VERSION 5.7 ;
  NOWIREEXTENSIONATPIN ON ;
  DIVIDERCHAR "/" ;
  BUSBITCHARS "[]" ;
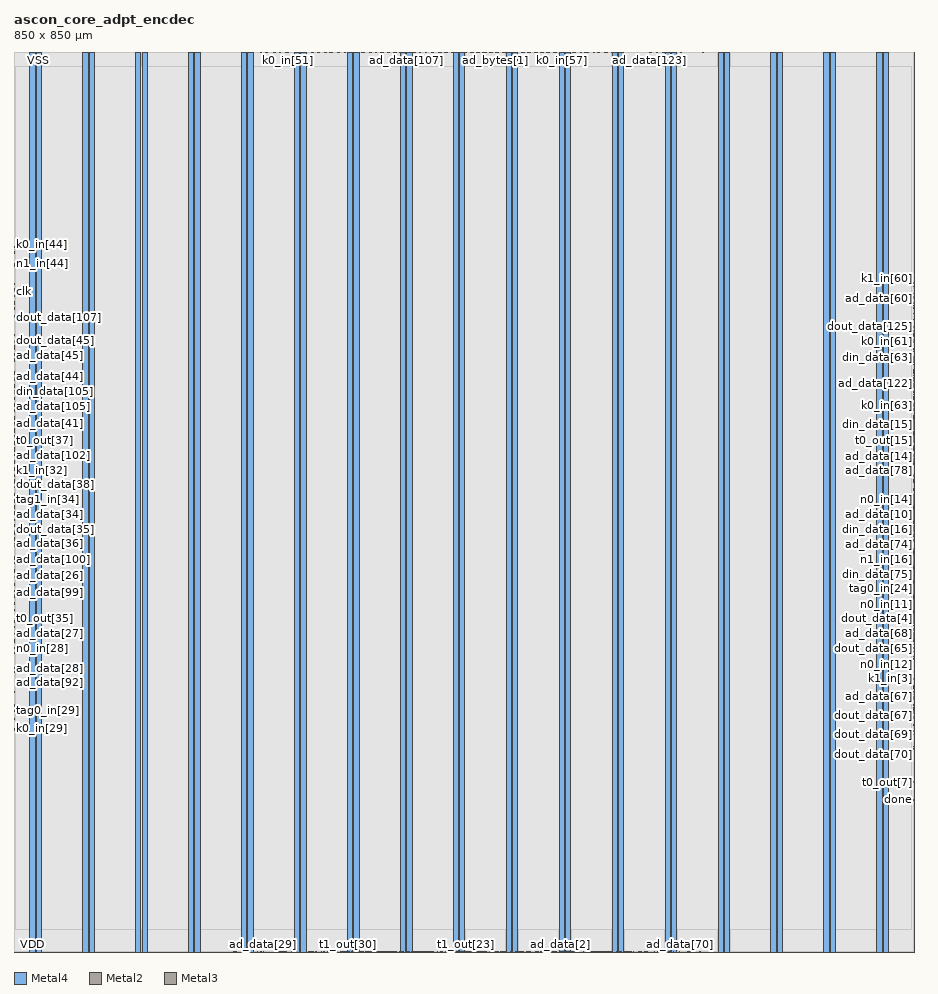
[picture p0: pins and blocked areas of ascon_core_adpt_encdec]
MACRO ascon_core_adpt_encdec
  CLASS BLOCK ;
  FOREIGN ascon_core_adpt_encdec ;
  ORIGIN 0.000 0.000 ;
  SIZE 850.000 BY 850.000 ;
  PIN VDD
    DIRECTION INOUT ;
    USE POWER ;
    PORT
      LAYER Metal4 ;
        RECT 14.940 0.000 19.940 850.000 ;
    END
    PORT
      LAYER Metal4 ;
        RECT 64.940 0.000 69.940 850.000 ;
    END
    PORT
      LAYER Metal4 ;
        RECT 114.940 0.000 119.940 850.000 ;
    END
    PORT
      LAYER Metal4 ;
        RECT 164.940 0.000 169.940 850.000 ;
    END
    PORT
      LAYER Metal4 ;
        RECT 214.940 0.000 219.940 850.000 ;
    END
    PORT
      LAYER Metal4 ;
        RECT 264.940 0.000 269.940 850.000 ;
    END
    PORT
      LAYER Metal4 ;
        RECT 314.940 0.000 319.940 850.000 ;
    END
    PORT
      LAYER Metal4 ;
        RECT 364.940 0.000 369.940 850.000 ;
    END
    PORT
      LAYER Metal4 ;
        RECT 414.940 0.000 419.940 850.000 ;
    END
    PORT
      LAYER Metal4 ;
        RECT 464.940 0.000 469.940 850.000 ;
    END
    PORT
      LAYER Metal4 ;
        RECT 514.940 0.000 519.940 850.000 ;
    END
    PORT
      LAYER Metal4 ;
        RECT 564.940 0.000 569.940 850.000 ;
    END
    PORT
      LAYER Metal4 ;
        RECT 614.940 0.000 619.940 850.000 ;
    END
    PORT
      LAYER Metal4 ;
        RECT 664.940 0.000 669.940 850.000 ;
    END
    PORT
      LAYER Metal4 ;
        RECT 714.940 0.000 719.940 850.000 ;
    END
    PORT
      LAYER Metal4 ;
        RECT 764.940 0.000 769.940 850.000 ;
    END
    PORT
      LAYER Metal4 ;
        RECT 814.940 0.000 819.940 850.000 ;
    END
  END VDD
  PIN VSS
    DIRECTION INOUT ;
    USE GROUND ;
    PORT
      LAYER Metal4 ;
        RECT 20.940 0.000 25.940 850.000 ;
    END
    PORT
      LAYER Metal4 ;
        RECT 70.940 0.000 75.940 850.000 ;
    END
    PORT
      LAYER Metal4 ;
        RECT 120.940 0.000 125.940 850.000 ;
    END
    PORT
      LAYER Metal4 ;
        RECT 170.940 0.000 175.940 850.000 ;
    END
    PORT
      LAYER Metal4 ;
        RECT 220.940 0.000 225.940 850.000 ;
    END
    PORT
      LAYER Metal4 ;
        RECT 270.940 0.000 275.940 850.000 ;
    END
    PORT
      LAYER Metal4 ;
        RECT 320.940 0.000 325.940 850.000 ;
    END
    PORT
      LAYER Metal4 ;
        RECT 370.940 0.000 375.940 850.000 ;
    END
    PORT
      LAYER Metal4 ;
        RECT 420.940 0.000 425.940 850.000 ;
    END
    PORT
      LAYER Metal4 ;
        RECT 470.940 0.000 475.940 850.000 ;
    END
    PORT
      LAYER Metal4 ;
        RECT 520.940 0.000 525.940 850.000 ;
    END
    PORT
      LAYER Metal4 ;
        RECT 570.940 0.000 575.940 850.000 ;
    END
    PORT
      LAYER Metal4 ;
        RECT 620.940 0.000 625.940 850.000 ;
    END
    PORT
      LAYER Metal4 ;
        RECT 670.940 0.000 675.940 850.000 ;
    END
    PORT
      LAYER Metal4 ;
        RECT 720.940 0.000 725.940 850.000 ;
    END
    PORT
      LAYER Metal4 ;
        RECT 770.940 0.000 775.940 850.000 ;
    END
    PORT
      LAYER Metal4 ;
        RECT 820.940 0.000 825.940 850.000 ;
    END
  END VSS
  PIN ad_bytes[0]
    DIRECTION INPUT ;
    USE SIGNAL ;
    ANTENNAGATEAREA 0.741000 ;
    PORT
      LAYER Metal2 ;
        RECT 453.600 849.440 454.160 850.000 ;
    END
  END ad_bytes[0]
  PIN ad_bytes[1]
    DIRECTION INPUT ;
    USE SIGNAL ;
    ANTENNAGATEAREA 1.102000 ;
    PORT
      LAYER Metal2 ;
        RECT 454.720 849.440 455.280 850.000 ;
    END
  END ad_bytes[1]
  PIN ad_bytes[2]
    DIRECTION INPUT ;
    USE SIGNAL ;
    ANTENNAGATEAREA 0.741000 ;
    PORT
      LAYER Metal2 ;
        RECT 448.000 849.440 448.560 850.000 ;
    END
  END ad_bytes[2]
  PIN ad_bytes[3]
    DIRECTION INPUT ;
    USE SIGNAL ;
    ANTENNAGATEAREA 0.741000 ;
    PORT
      LAYER Metal2 ;
        RECT 461.440 849.440 462.000 850.000 ;
    END
  END ad_bytes[3]
  PIN ad_bytes[4]
    DIRECTION INPUT ;
    USE SIGNAL ;
    ANTENNAGATEAREA 1.102000 ;
    PORT
      LAYER Metal2 ;
        RECT 462.560 849.440 463.120 850.000 ;
    END
  END ad_bytes[4]
  PIN ad_data[0]
    DIRECTION INPUT ;
    USE SIGNAL ;
    ANTENNAGATEAREA 0.741000 ;
    PORT
      LAYER Metal3 ;
        RECT 849.440 374.080 850.000 374.640 ;
    END
  END ad_data[0]
  PIN ad_data[100]
    DIRECTION INPUT ;
    USE SIGNAL ;
    ANTENNAGATEAREA 0.741000 ;
    PORT
      LAYER Metal3 ;
        RECT 0.000 370.720 0.560 371.280 ;
    END
  END ad_data[100]
  PIN ad_data[101]
    DIRECTION INPUT ;
    USE SIGNAL ;
    ANTENNAGATEAREA 0.741000 ;
    PORT
      LAYER Metal3 ;
        RECT 0.000 458.080 0.560 458.640 ;
    END
  END ad_data[101]
  PIN ad_data[102]
    DIRECTION INPUT ;
    USE SIGNAL ;
    ANTENNAGATEAREA 0.741000 ;
    PORT
      LAYER Metal3 ;
        RECT 0.000 476.000 0.560 476.560 ;
    END
  END ad_data[102]
  PIN ad_data[103]
    DIRECTION INPUT ;
    USE SIGNAL ;
    ANTENNAGATEAREA 0.741000 ;
    PORT
      LAYER Metal3 ;
        RECT 0.000 449.120 0.560 449.680 ;
    END
  END ad_data[103]
  PIN ad_data[104]
    DIRECTION INPUT ;
    USE SIGNAL ;
    ANTENNAGATEAREA 0.741000 ;
    PORT
      LAYER Metal2 ;
        RECT 430.080 849.440 430.640 850.000 ;
    END
  END ad_data[104]
  PIN ad_data[105]
    DIRECTION INPUT ;
    USE SIGNAL ;
    ANTENNAGATEAREA 0.741000 ;
    PORT
      LAYER Metal3 ;
        RECT 0.000 515.200 0.560 515.760 ;
    END
  END ad_data[105]
  PIN ad_data[106]
    DIRECTION INPUT ;
    USE SIGNAL ;
    ANTENNAGATEAREA 0.741000 ;
    PORT
      LAYER Metal3 ;
        RECT 0.000 511.840 0.560 512.400 ;
    END
  END ad_data[106]
  PIN ad_data[107]
    DIRECTION INPUT ;
    USE SIGNAL ;
    ANTENNAGATEAREA 0.741000 ;
    PORT
      LAYER Metal2 ;
        RECT 370.720 849.440 371.280 850.000 ;
    END
  END ad_data[107]
  PIN ad_data[108]
    DIRECTION INPUT ;
    USE SIGNAL ;
    ANTENNAGATEAREA 0.741000 ;
    PORT
      LAYER Metal3 ;
        RECT 0.000 612.640 0.560 613.200 ;
    END
  END ad_data[108]
  PIN ad_data[109]
    DIRECTION INPUT ;
    USE SIGNAL ;
    ANTENNAGATEAREA 0.741000 ;
    PORT
      LAYER Metal3 ;
        RECT 0.000 608.160 0.560 608.720 ;
    END
  END ad_data[109]
  PIN ad_data[10]
    DIRECTION INPUT ;
    USE SIGNAL ;
    ANTENNAGATEAREA 0.741000 ;
    PORT
      LAYER Metal3 ;
        RECT 849.440 413.280 850.000 413.840 ;
    END
  END ad_data[10]
  PIN ad_data[110]
    DIRECTION INPUT ;
    USE SIGNAL ;
    ANTENNAGATEAREA 0.741000 ;
    PORT
      LAYER Metal2 ;
        RECT 246.400 849.440 246.960 850.000 ;
    END
  END ad_data[110]
  PIN ad_data[111]
    DIRECTION INPUT ;
    USE SIGNAL ;
    ANTENNAGATEAREA 0.741000 ;
    PORT
      LAYER Metal3 ;
        RECT 0.000 558.880 0.560 559.440 ;
    END
  END ad_data[111]
  PIN ad_data[112]
    DIRECTION INPUT ;
    USE SIGNAL ;
    ANTENNAGATEAREA 0.741000 ;
    PORT
      LAYER Metal2 ;
        RECT 418.880 849.440 419.440 850.000 ;
    END
  END ad_data[112]
  PIN ad_data[113]
    DIRECTION INPUT ;
    USE SIGNAL ;
    ANTENNAGATEAREA 0.741000 ;
    PORT
      LAYER Metal2 ;
        RECT 296.800 849.440 297.360 850.000 ;
    END
  END ad_data[113]
  PIN ad_data[114]
    DIRECTION INPUT ;
    USE SIGNAL ;
    ANTENNAGATEAREA 0.741000 ;
    PORT
      LAYER Metal2 ;
        RECT 348.320 849.440 348.880 850.000 ;
    END
  END ad_data[114]
  PIN ad_data[115]
    DIRECTION INPUT ;
    USE SIGNAL ;
    ANTENNAGATEAREA 0.741000 ;
    PORT
      LAYER Metal2 ;
        RECT 287.840 849.440 288.400 850.000 ;
    END
  END ad_data[115]
  PIN ad_data[116]
    DIRECTION INPUT ;
    USE SIGNAL ;
    ANTENNAGATEAREA 0.741000 ;
    PORT
      LAYER Metal2 ;
        RECT 327.040 849.440 327.600 850.000 ;
    END
  END ad_data[116]
  PIN ad_data[117]
    DIRECTION INPUT ;
    USE SIGNAL ;
    ANTENNAGATEAREA 0.741000 ;
    PORT
      LAYER Metal2 ;
        RECT 427.840 849.440 428.400 850.000 ;
    END
  END ad_data[117]
  PIN ad_data[118]
    DIRECTION INPUT ;
    USE SIGNAL ;
    ANTENNAGATEAREA 0.741000 ;
    PORT
      LAYER Metal2 ;
        RECT 465.920 849.440 466.480 850.000 ;
    END
  END ad_data[118]
  PIN ad_data[119]
    DIRECTION INPUT ;
    USE SIGNAL ;
    ANTENNAGATEAREA 0.741000 ;
    PORT
      LAYER Metal2 ;
        RECT 452.480 849.440 453.040 850.000 ;
    END
  END ad_data[119]
  PIN ad_data[11]
    DIRECTION INPUT ;
    USE SIGNAL ;
    ANTENNAGATEAREA 0.741000 ;
    PORT
      LAYER Metal3 ;
        RECT 849.440 409.920 850.000 410.480 ;
    END
  END ad_data[11]
  PIN ad_data[120]
    DIRECTION INPUT ;
    USE SIGNAL ;
    ANTENNAGATEAREA 0.741000 ;
    PORT
      LAYER Metal2 ;
        RECT 474.880 849.440 475.440 850.000 ;
    END
  END ad_data[120]
  PIN ad_data[121]
    DIRECTION INPUT ;
    USE SIGNAL ;
    ANTENNAGATEAREA 0.741000 ;
    PORT
      LAYER Metal2 ;
        RECT 523.040 849.440 523.600 850.000 ;
    END
  END ad_data[121]
  PIN ad_data[122]
    DIRECTION INPUT ;
    USE SIGNAL ;
    ANTENNAGATEAREA 0.741000 ;
    PORT
      LAYER Metal3 ;
        RECT 849.440 536.480 850.000 537.040 ;
    END
  END ad_data[122]
  PIN ad_data[123]
    DIRECTION INPUT ;
    USE SIGNAL ;
    ANTENNAGATEAREA 0.741000 ;
    PORT
      LAYER Metal2 ;
        RECT 600.320 849.440 600.880 850.000 ;
    END
  END ad_data[123]
  PIN ad_data[124]
    DIRECTION INPUT ;
    USE SIGNAL ;
    ANTENNAGATEAREA 0.741000 ;
    PORT
      LAYER Metal2 ;
        RECT 619.360 849.440 619.920 850.000 ;
    END
  END ad_data[124]
  PIN ad_data[125]
    DIRECTION INPUT ;
    USE SIGNAL ;
    ANTENNAGATEAREA 0.741000 ;
    PORT
      LAYER Metal3 ;
        RECT 849.440 577.920 850.000 578.480 ;
    END
  END ad_data[125]
  PIN ad_data[126]
    DIRECTION INPUT ;
    USE SIGNAL ;
    ANTENNAGATEAREA 0.741000 ;
    PORT
      LAYER Metal2 ;
        RECT 560.000 849.440 560.560 850.000 ;
    END
  END ad_data[126]
  PIN ad_data[127]
    DIRECTION INPUT ;
    USE SIGNAL ;
    ANTENNAGATEAREA 0.741000 ;
    PORT
      LAYER Metal3 ;
        RECT 849.440 538.720 850.000 539.280 ;
    END
  END ad_data[127]
  PIN ad_data[12]
    DIRECTION INPUT ;
    USE SIGNAL ;
    ANTENNAGATEAREA 0.741000 ;
    PORT
      LAYER Metal3 ;
        RECT 849.440 412.160 850.000 412.720 ;
    END
  END ad_data[12]
  PIN ad_data[13]
    DIRECTION INPUT ;
    USE SIGNAL ;
    ANTENNAGATEAREA 0.741000 ;
    PORT
      LAYER Metal3 ;
        RECT 849.440 418.880 850.000 419.440 ;
    END
  END ad_data[13]
  PIN ad_data[14]
    DIRECTION INPUT ;
    USE SIGNAL ;
    ANTENNAGATEAREA 0.741000 ;
    PORT
      LAYER Metal3 ;
        RECT 849.440 474.880 850.000 475.440 ;
    END
  END ad_data[14]
  PIN ad_data[15]
    DIRECTION INPUT ;
    USE SIGNAL ;
    ANTENNAGATEAREA 0.741000 ;
    PORT
      LAYER Metal3 ;
        RECT 849.440 481.600 850.000 482.160 ;
    END
  END ad_data[15]
  PIN ad_data[16]
    DIRECTION INPUT ;
    USE SIGNAL ;
    ANTENNAGATEAREA 0.741000 ;
    PORT
      LAYER Metal3 ;
        RECT 849.440 428.960 850.000 429.520 ;
    END
  END ad_data[16]
  PIN ad_data[17]
    DIRECTION INPUT ;
    USE SIGNAL ;
    ANTENNAGATEAREA 0.741000 ;
    PORT
      LAYER Metal2 ;
        RECT 385.280 0.000 385.840 0.560 ;
    END
  END ad_data[17]
  PIN ad_data[18]
    DIRECTION INPUT ;
    USE SIGNAL ;
    ANTENNAGATEAREA 0.741000 ;
    PORT
      LAYER Metal2 ;
        RECT 445.760 0.000 446.320 0.560 ;
    END
  END ad_data[18]
  PIN ad_data[19]
    DIRECTION INPUT ;
    USE SIGNAL ;
    ANTENNAGATEAREA 0.741000 ;
    PORT
      LAYER Metal2 ;
        RECT 389.760 0.000 390.320 0.560 ;
    END
  END ad_data[19]
  PIN ad_data[1]
    DIRECTION INPUT ;
    USE SIGNAL ;
    ANTENNAGATEAREA 0.741000 ;
    PORT
      LAYER Metal2 ;
        RECT 524.160 0.000 524.720 0.560 ;
    END
  END ad_data[1]
  PIN ad_data[20]
    DIRECTION INPUT ;
    USE SIGNAL ;
    ANTENNAGATEAREA 0.741000 ;
    PORT
      LAYER Metal2 ;
        RECT 443.520 0.000 444.080 0.560 ;
    END
  END ad_data[20]
  PIN ad_data[21]
    DIRECTION INPUT ;
    USE SIGNAL ;
    ANTENNAGATEAREA 0.741000 ;
    PORT
      LAYER Metal2 ;
        RECT 422.240 0.000 422.800 0.560 ;
    END
  END ad_data[21]
  PIN ad_data[22]
    DIRECTION INPUT ;
    USE SIGNAL ;
    ANTENNAGATEAREA 0.741000 ;
    PORT
      LAYER Metal2 ;
        RECT 381.920 0.000 382.480 0.560 ;
    END
  END ad_data[22]
  PIN ad_data[23]
    DIRECTION INPUT ;
    USE SIGNAL ;
    ANTENNAGATEAREA 0.741000 ;
    PORT
      LAYER Metal2 ;
        RECT 384.160 0.000 384.720 0.560 ;
    END
  END ad_data[23]
  PIN ad_data[24]
    DIRECTION INPUT ;
    USE SIGNAL ;
    ANTENNAGATEAREA 0.741000 ;
    PORT
      LAYER Metal3 ;
        RECT 0.000 432.320 0.560 432.880 ;
    END
  END ad_data[24]
  PIN ad_data[25]
    DIRECTION INPUT ;
    USE SIGNAL ;
    ANTENNAGATEAREA 0.741000 ;
    PORT
      LAYER Metal2 ;
        RECT 255.360 0.000 255.920 0.560 ;
    END
  END ad_data[25]
  PIN ad_data[26]
    DIRECTION INPUT ;
    USE SIGNAL ;
    ANTENNAGATEAREA 0.741000 ;
    PORT
      LAYER Metal3 ;
        RECT 0.000 362.880 0.560 363.440 ;
    END
  END ad_data[26]
  PIN ad_data[27]
    DIRECTION INPUT ;
    USE SIGNAL ;
    ANTENNAGATEAREA 0.741000 ;
    PORT
      LAYER Metal3 ;
        RECT 0.000 293.440 0.560 294.000 ;
    END
  END ad_data[27]
  PIN ad_data[28]
    DIRECTION INPUT ;
    USE SIGNAL ;
    ANTENNAGATEAREA 0.741000 ;
    PORT
      LAYER Metal3 ;
        RECT 0.000 267.680 0.560 268.240 ;
    END
  END ad_data[28]
  PIN ad_data[29]
    DIRECTION INPUT ;
    USE SIGNAL ;
    ANTENNAGATEAREA 0.741000 ;
    PORT
      LAYER Metal2 ;
        RECT 235.200 0.000 235.760 0.560 ;
    END
  END ad_data[29]
  PIN ad_data[2]
    DIRECTION INPUT ;
    USE SIGNAL ;
    ANTENNAGATEAREA 0.741000 ;
    PORT
      LAYER Metal2 ;
        RECT 516.320 0.000 516.880 0.560 ;
    END
  END ad_data[2]
  PIN ad_data[30]
    DIRECTION INPUT ;
    USE SIGNAL ;
    ANTENNAGATEAREA 0.741000 ;
    PORT
      LAYER Metal2 ;
        RECT 285.600 0.000 286.160 0.560 ;
    END
  END ad_data[30]
  PIN ad_data[31]
    DIRECTION INPUT ;
    USE SIGNAL ;
    ANTENNAGATEAREA 0.741000 ;
    PORT
      LAYER Metal3 ;
        RECT 0.000 359.520 0.560 360.080 ;
    END
  END ad_data[31]
  PIN ad_data[32]
    DIRECTION INPUT ;
    USE SIGNAL ;
    ANTENNAGATEAREA 0.741000 ;
    PORT
      LAYER Metal3 ;
        RECT 0.000 439.040 0.560 439.600 ;
    END
  END ad_data[32]
  PIN ad_data[33]
    DIRECTION INPUT ;
    USE SIGNAL ;
    ANTENNAGATEAREA 0.741000 ;
    PORT
      LAYER Metal3 ;
        RECT 0.000 399.840 0.560 400.400 ;
    END
  END ad_data[33]
  PIN ad_data[34]
    DIRECTION INPUT ;
    USE SIGNAL ;
    ANTENNAGATEAREA 0.741000 ;
    PORT
      LAYER Metal3 ;
        RECT 0.000 413.280 0.560 413.840 ;
    END
  END ad_data[34]
  PIN ad_data[35]
    DIRECTION INPUT ;
    USE SIGNAL ;
    ANTENNAGATEAREA 0.741000 ;
    PORT
      LAYER Metal3 ;
        RECT 0.000 397.600 0.560 398.160 ;
    END
  END ad_data[35]
  PIN ad_data[36]
    DIRECTION INPUT ;
    USE SIGNAL ;
    ANTENNAGATEAREA 0.741000 ;
    PORT
      LAYER Metal3 ;
        RECT 0.000 385.280 0.560 385.840 ;
    END
  END ad_data[36]
  PIN ad_data[37]
    DIRECTION INPUT ;
    USE SIGNAL ;
    ANTENNAGATEAREA 0.741000 ;
    PORT
      LAYER Metal3 ;
        RECT 0.000 421.120 0.560 421.680 ;
    END
  END ad_data[37]
  PIN ad_data[38]
    DIRECTION INPUT ;
    USE SIGNAL ;
    ANTENNAGATEAREA 0.741000 ;
    PORT
      LAYER Metal3 ;
        RECT 0.000 444.640 0.560 445.200 ;
    END
  END ad_data[38]
  PIN ad_data[39]
    DIRECTION INPUT ;
    USE SIGNAL ;
    ANTENNAGATEAREA 0.741000 ;
    PORT
      LAYER Metal3 ;
        RECT 0.000 431.200 0.560 431.760 ;
    END
  END ad_data[39]
  PIN ad_data[3]
    DIRECTION INPUT ;
    USE SIGNAL ;
    ANTENNAGATEAREA 0.741000 ;
    PORT
      LAYER Metal2 ;
        RECT 525.280 0.000 525.840 0.560 ;
    END
  END ad_data[3]
  PIN ad_data[40]
    DIRECTION INPUT ;
    USE SIGNAL ;
    ANTENNAGATEAREA 0.741000 ;
    PORT
      LAYER Metal3 ;
        RECT 0.000 470.400 0.560 470.960 ;
    END
  END ad_data[40]
  PIN ad_data[41]
    DIRECTION INPUT ;
    USE SIGNAL ;
    ANTENNAGATEAREA 0.741000 ;
    PORT
      LAYER Metal3 ;
        RECT 0.000 498.400 0.560 498.960 ;
    END
  END ad_data[41]
  PIN ad_data[42]
    DIRECTION INPUT ;
    USE SIGNAL ;
    ANTENNAGATEAREA 0.741000 ;
    PORT
      LAYER Metal3 ;
        RECT 0.000 510.720 0.560 511.280 ;
    END
  END ad_data[42]
  PIN ad_data[43]
    DIRECTION INPUT ;
    USE SIGNAL ;
    ANTENNAGATEAREA 0.741000 ;
    PORT
      LAYER Metal2 ;
        RECT 360.640 849.440 361.200 850.000 ;
    END
  END ad_data[43]
  PIN ad_data[44]
    DIRECTION INPUT ;
    USE SIGNAL ;
    ANTENNAGATEAREA 0.741000 ;
    PORT
      LAYER Metal3 ;
        RECT 0.000 543.200 0.560 543.760 ;
    END
  END ad_data[44]
  PIN ad_data[45]
    DIRECTION INPUT ;
    USE SIGNAL ;
    ANTENNAGATEAREA 0.741000 ;
    PORT
      LAYER Metal3 ;
        RECT 0.000 563.360 0.560 563.920 ;
    END
  END ad_data[45]
  PIN ad_data[46]
    DIRECTION INPUT ;
    USE SIGNAL ;
    ANTENNAGATEAREA 0.741000 ;
    PORT
      LAYER Metal3 ;
        RECT 0.000 564.480 0.560 565.040 ;
    END
  END ad_data[46]
  PIN ad_data[47]
    DIRECTION INPUT ;
    USE SIGNAL ;
    ANTENNAGATEAREA 0.741000 ;
    PORT
      LAYER Metal3 ;
        RECT 0.000 555.520 0.560 556.080 ;
    END
  END ad_data[47]
  PIN ad_data[48]
    DIRECTION INPUT ;
    USE SIGNAL ;
    ANTENNAGATEAREA 0.741000 ;
    PORT
      LAYER Metal2 ;
        RECT 450.240 849.440 450.800 850.000 ;
    END
  END ad_data[48]
  PIN ad_data[49]
    DIRECTION INPUT ;
    USE SIGNAL ;
    ANTENNAGATEAREA 0.741000 ;
    PORT
      LAYER Metal2 ;
        RECT 394.240 849.440 394.800 850.000 ;
    END
  END ad_data[49]
  PIN ad_data[4]
    DIRECTION INPUT ;
    USE SIGNAL ;
    ANTENNAGATEAREA 0.741000 ;
    PORT
      LAYER Metal3 ;
        RECT 849.440 310.240 850.000 310.800 ;
    END
  END ad_data[4]
  PIN ad_data[50]
    DIRECTION INPUT ;
    USE SIGNAL ;
    ANTENNAGATEAREA 0.741000 ;
    PORT
      LAYER Metal2 ;
        RECT 379.680 849.440 380.240 850.000 ;
    END
  END ad_data[50]
  PIN ad_data[51]
    DIRECTION INPUT ;
    USE SIGNAL ;
    ANTENNAGATEAREA 0.741000 ;
    PORT
      LAYER Metal2 ;
        RECT 378.560 849.440 379.120 850.000 ;
    END
  END ad_data[51]
  PIN ad_data[52]
    DIRECTION INPUT ;
    USE SIGNAL ;
    ANTENNAGATEAREA 0.741000 ;
    PORT
      LAYER Metal2 ;
        RECT 377.440 849.440 378.000 850.000 ;
    END
  END ad_data[52]
  PIN ad_data[53]
    DIRECTION INPUT ;
    USE SIGNAL ;
    ANTENNAGATEAREA 0.741000 ;
    PORT
      LAYER Metal2 ;
        RECT 402.080 849.440 402.640 850.000 ;
    END
  END ad_data[53]
  PIN ad_data[54]
    DIRECTION INPUT ;
    USE SIGNAL ;
    ANTENNAGATEAREA 0.741000 ;
    PORT
      LAYER Metal2 ;
        RECT 467.040 849.440 467.600 850.000 ;
    END
  END ad_data[54]
  PIN ad_data[55]
    DIRECTION INPUT ;
    USE SIGNAL ;
    ANTENNAGATEAREA 0.741000 ;
    PORT
      LAYER Metal2 ;
        RECT 420.000 849.440 420.560 850.000 ;
    END
  END ad_data[55]
  PIN ad_data[56]
    DIRECTION INPUT ;
    USE SIGNAL ;
    ANTENNAGATEAREA 0.741000 ;
    PORT
      LAYER Metal2 ;
        RECT 471.520 849.440 472.080 850.000 ;
    END
  END ad_data[56]
  PIN ad_data[57]
    DIRECTION INPUT ;
    USE SIGNAL ;
    ANTENNAGATEAREA 0.741000 ;
    PORT
      LAYER Metal2 ;
        RECT 521.920 849.440 522.480 850.000 ;
    END
  END ad_data[57]
  PIN ad_data[58]
    DIRECTION INPUT ;
    USE SIGNAL ;
    ANTENNAGATEAREA 0.741000 ;
    PORT
      LAYER Metal2 ;
        RECT 520.800 849.440 521.360 850.000 ;
    END
  END ad_data[58]
  PIN ad_data[59]
    DIRECTION INPUT ;
    USE SIGNAL ;
    ANTENNAGATEAREA 0.741000 ;
    PORT
      LAYER Metal2 ;
        RECT 574.560 849.440 575.120 850.000 ;
    END
  END ad_data[59]
  PIN ad_data[5]
    DIRECTION INPUT ;
    USE SIGNAL ;
    ANTENNAGATEAREA 0.741000 ;
    PORT
      LAYER Metal2 ;
        RECT 527.520 0.000 528.080 0.560 ;
    END
  END ad_data[5]
  PIN ad_data[60]
    DIRECTION INPUT ;
    USE SIGNAL ;
    ANTENNAGATEAREA 0.741000 ;
    PORT
      LAYER Metal3 ;
        RECT 849.440 617.120 850.000 617.680 ;
    END
  END ad_data[60]
  PIN ad_data[61]
    DIRECTION INPUT ;
    USE SIGNAL ;
    ANTENNAGATEAREA 0.741000 ;
    PORT
      LAYER Metal3 ;
        RECT 849.440 582.400 850.000 582.960 ;
    END
  END ad_data[61]
  PIN ad_data[62]
    DIRECTION INPUT ;
    USE SIGNAL ;
    ANTENNAGATEAREA 0.741000 ;
    PORT
      LAYER Metal2 ;
        RECT 526.400 849.440 526.960 850.000 ;
    END
  END ad_data[62]
  PIN ad_data[63]
    DIRECTION INPUT ;
    USE SIGNAL ;
    ANTENNAGATEAREA 0.741000 ;
    PORT
      LAYER Metal3 ;
        RECT 849.440 554.400 850.000 554.960 ;
    END
  END ad_data[63]
  PIN ad_data[64]
    DIRECTION INPUT ;
    USE SIGNAL ;
    ANTENNAGATEAREA 0.741000 ;
    PORT
      LAYER Metal2 ;
        RECT 488.320 849.440 488.880 850.000 ;
    END
  END ad_data[64]
  PIN ad_data[65]
    DIRECTION INPUT ;
    USE SIGNAL ;
    ANTENNAGATEAREA 0.741000 ;
    PORT
      LAYER Metal2 ;
        RECT 571.200 0.000 571.760 0.560 ;
    END
  END ad_data[65]
  PIN ad_data[66]
    DIRECTION INPUT ;
    USE SIGNAL ;
    ANTENNAGATEAREA 0.741000 ;
    PORT
      LAYER Metal2 ;
        RECT 544.320 0.000 544.880 0.560 ;
    END
  END ad_data[66]
  PIN ad_data[67]
    DIRECTION INPUT ;
    USE SIGNAL ;
    ANTENNAGATEAREA 0.741000 ;
    PORT
      LAYER Metal3 ;
        RECT 849.440 240.800 850.000 241.360 ;
    END
  END ad_data[67]
  PIN ad_data[68]
    DIRECTION INPUT ;
    USE SIGNAL ;
    ANTENNAGATEAREA 0.741000 ;
    PORT
      LAYER Metal3 ;
        RECT 849.440 293.440 850.000 294.000 ;
    END
  END ad_data[68]
  PIN ad_data[69]
    DIRECTION INPUT ;
    USE SIGNAL ;
    ANTENNAGATEAREA 0.741000 ;
    PORT
      LAYER Metal2 ;
        RECT 547.680 0.000 548.240 0.560 ;
    END
  END ad_data[69]
  PIN ad_data[6]
    DIRECTION INPUT ;
    USE SIGNAL ;
    ANTENNAGATEAREA 0.741000 ;
    PORT
      LAYER Metal2 ;
        RECT 579.040 0.000 579.600 0.560 ;
    END
  END ad_data[6]
  PIN ad_data[70]
    DIRECTION INPUT ;
    USE SIGNAL ;
    ANTENNAGATEAREA 0.741000 ;
    PORT
      LAYER Metal2 ;
        RECT 628.320 0.000 628.880 0.560 ;
    END
  END ad_data[70]
  PIN ad_data[71]
    DIRECTION INPUT ;
    USE SIGNAL ;
    ANTENNAGATEAREA 0.741000 ;
    PORT
      LAYER Metal2 ;
        RECT 608.160 0.000 608.720 0.560 ;
    END
  END ad_data[71]
  PIN ad_data[72]
    DIRECTION INPUT ;
    USE SIGNAL ;
    ANTENNAGATEAREA 0.741000 ;
    PORT
      LAYER Metal3 ;
        RECT 849.440 423.360 850.000 423.920 ;
    END
  END ad_data[72]
  PIN ad_data[73]
    DIRECTION INPUT ;
    USE SIGNAL ;
    ANTENNAGATEAREA 0.741000 ;
    PORT
      LAYER Metal3 ;
        RECT 849.440 484.960 850.000 485.520 ;
    END
  END ad_data[73]
  PIN ad_data[74]
    DIRECTION INPUT ;
    USE SIGNAL ;
    ANTENNAGATEAREA 0.741000 ;
    PORT
      LAYER Metal3 ;
        RECT 849.440 392.000 850.000 392.560 ;
    END
  END ad_data[74]
  PIN ad_data[75]
    DIRECTION INPUT ;
    USE SIGNAL ;
    ANTENNAGATEAREA 0.741000 ;
    PORT
      LAYER Metal3 ;
        RECT 849.440 367.360 850.000 367.920 ;
    END
  END ad_data[75]
  PIN ad_data[76]
    DIRECTION INPUT ;
    USE SIGNAL ;
    ANTENNAGATEAREA 0.741000 ;
    PORT
      LAYER Metal3 ;
        RECT 849.440 330.400 850.000 330.960 ;
    END
  END ad_data[76]
  PIN ad_data[77]
    DIRECTION INPUT ;
    USE SIGNAL ;
    ANTENNAGATEAREA 0.741000 ;
    PORT
      LAYER Metal3 ;
        RECT 849.440 394.240 850.000 394.800 ;
    END
  END ad_data[77]
  PIN ad_data[78]
    DIRECTION INPUT ;
    USE SIGNAL ;
    ANTENNAGATEAREA 0.741000 ;
    PORT
      LAYER Metal3 ;
        RECT 849.440 461.440 850.000 462.000 ;
    END
  END ad_data[78]
  PIN ad_data[79]
    DIRECTION INPUT ;
    USE SIGNAL ;
    ANTENNAGATEAREA 0.741000 ;
    PORT
      LAYER Metal3 ;
        RECT 849.440 488.320 850.000 488.880 ;
    END
  END ad_data[79]
  PIN ad_data[7]
    DIRECTION INPUT ;
    USE SIGNAL ;
    ANTENNAGATEAREA 0.741000 ;
    PORT
      LAYER Metal2 ;
        RECT 581.280 0.000 581.840 0.560 ;
    END
  END ad_data[7]
  PIN ad_data[80]
    DIRECTION INPUT ;
    USE SIGNAL ;
    ANTENNAGATEAREA 0.741000 ;
    PORT
      LAYER Metal2 ;
        RECT 468.160 849.440 468.720 850.000 ;
    END
  END ad_data[80]
  PIN ad_data[81]
    DIRECTION INPUT ;
    USE SIGNAL ;
    ANTENNAGATEAREA 0.741000 ;
    PORT
      LAYER Metal2 ;
        RECT 420.000 0.000 420.560 0.560 ;
    END
  END ad_data[81]
  PIN ad_data[82]
    DIRECTION INPUT ;
    USE SIGNAL ;
    ANTENNAGATEAREA 0.741000 ;
    PORT
      LAYER Metal2 ;
        RECT 473.760 0.000 474.320 0.560 ;
    END
  END ad_data[82]
  PIN ad_data[83]
    DIRECTION INPUT ;
    USE SIGNAL ;
    ANTENNAGATEAREA 0.741000 ;
    PORT
      LAYER Metal2 ;
        RECT 430.080 0.000 430.640 0.560 ;
    END
  END ad_data[83]
  PIN ad_data[84]
    DIRECTION INPUT ;
    USE SIGNAL ;
    ANTENNAGATEAREA 0.741000 ;
    PORT
      LAYER Metal2 ;
        RECT 469.280 0.000 469.840 0.560 ;
    END
  END ad_data[84]
  PIN ad_data[85]
    DIRECTION INPUT ;
    USE SIGNAL ;
    ANTENNAGATEAREA 0.741000 ;
    PORT
      LAYER Metal2 ;
        RECT 454.720 0.000 455.280 0.560 ;
    END
  END ad_data[85]
  PIN ad_data[86]
    DIRECTION INPUT ;
    USE SIGNAL ;
    ANTENNAGATEAREA 0.741000 ;
    PORT
      LAYER Metal2 ;
        RECT 356.160 0.000 356.720 0.560 ;
    END
  END ad_data[86]
  PIN ad_data[87]
    DIRECTION INPUT ;
    USE SIGNAL ;
    ANTENNAGATEAREA 0.741000 ;
    PORT
      LAYER Metal2 ;
        RECT 359.520 0.000 360.080 0.560 ;
    END
  END ad_data[87]
  PIN ad_data[88]
    DIRECTION INPUT ;
    USE SIGNAL ;
    ANTENNAGATEAREA 0.741000 ;
    PORT
      LAYER Metal2 ;
        RECT 349.440 0.000 350.000 0.560 ;
    END
  END ad_data[88]
  PIN ad_data[89]
    DIRECTION INPUT ;
    USE SIGNAL ;
    ANTENNAGATEAREA 0.741000 ;
    PORT
      LAYER Metal2 ;
        RECT 247.520 0.000 248.080 0.560 ;
    END
  END ad_data[89]
  PIN ad_data[8]
    DIRECTION INPUT ;
    USE SIGNAL ;
    ANTENNAGATEAREA 0.741000 ;
    PORT
      LAYER Metal3 ;
        RECT 849.440 416.640 850.000 417.200 ;
    END
  END ad_data[8]
  PIN ad_data[90]
    DIRECTION INPUT ;
    USE SIGNAL ;
    ANTENNAGATEAREA 0.741000 ;
    PORT
      LAYER Metal3 ;
        RECT 0.000 313.600 0.560 314.160 ;
    END
  END ad_data[90]
  PIN ad_data[91]
    DIRECTION INPUT ;
    USE SIGNAL ;
    ANTENNAGATEAREA 0.741000 ;
    PORT
      LAYER Metal3 ;
        RECT 0.000 272.160 0.560 272.720 ;
    END
  END ad_data[91]
  PIN ad_data[92]
    DIRECTION INPUT ;
    USE SIGNAL ;
    ANTENNAGATEAREA 0.741000 ;
    PORT
      LAYER Metal3 ;
        RECT 0.000 254.240 0.560 254.800 ;
    END
  END ad_data[92]
  PIN ad_data[93]
    DIRECTION INPUT ;
    USE SIGNAL ;
    ANTENNAGATEAREA 0.741000 ;
    PORT
      LAYER Metal2 ;
        RECT 207.200 0.000 207.760 0.560 ;
    END
  END ad_data[93]
  PIN ad_data[94]
    DIRECTION INPUT ;
    USE SIGNAL ;
    ANTENNAGATEAREA 0.741000 ;
    PORT
      LAYER Metal2 ;
        RECT 250.880 0.000 251.440 0.560 ;
    END
  END ad_data[94]
  PIN ad_data[95]
    DIRECTION INPUT ;
    USE SIGNAL ;
    ANTENNAGATEAREA 0.741000 ;
    PORT
      LAYER Metal2 ;
        RECT 324.800 0.000 325.360 0.560 ;
    END
  END ad_data[95]
  PIN ad_data[96]
    DIRECTION INPUT ;
    USE SIGNAL ;
    ANTENNAGATEAREA 0.741000 ;
    PORT
      LAYER Metal2 ;
        RECT 445.760 849.440 446.320 850.000 ;
    END
  END ad_data[96]
  PIN ad_data[97]
    DIRECTION INPUT ;
    USE SIGNAL ;
    ANTENNAGATEAREA 0.741000 ;
    PORT
      LAYER Metal3 ;
        RECT 0.000 409.920 0.560 410.480 ;
    END
  END ad_data[97]
  PIN ad_data[98]
    DIRECTION INPUT ;
    USE SIGNAL ;
    ANTENNAGATEAREA 0.741000 ;
    PORT
      LAYER Metal3 ;
        RECT 0.000 430.080 0.560 430.640 ;
    END
  END ad_data[98]
  PIN ad_data[99]
    DIRECTION INPUT ;
    USE SIGNAL ;
    ANTENNAGATEAREA 0.741000 ;
    PORT
      LAYER Metal3 ;
        RECT 0.000 346.080 0.560 346.640 ;
    END
  END ad_data[99]
  PIN ad_data[9]
    DIRECTION INPUT ;
    USE SIGNAL ;
    ANTENNAGATEAREA 0.741000 ;
    PORT
      LAYER Metal3 ;
        RECT 849.440 460.320 850.000 460.880 ;
    END
  END ad_data[9]
  PIN ad_empty
    DIRECTION INPUT ;
    USE SIGNAL ;
    ANTENNAGATEAREA 0.741000 ;
    PORT
      LAYER Metal3 ;
        RECT 849.440 445.760 850.000 446.320 ;
    END
  END ad_empty
  PIN ad_last
    DIRECTION INPUT ;
    USE SIGNAL ;
    ANTENNAGATEAREA 0.741000 ;
    PORT
      LAYER Metal2 ;
        RECT 528.640 849.440 529.200 850.000 ;
    END
  END ad_last
  PIN ad_ready
    DIRECTION OUTPUT ;
    USE SIGNAL ;
    ANTENNADIFFAREA 1.182800 ;
    PORT
      LAYER Metal2 ;
        RECT 623.840 849.440 624.400 850.000 ;
    END
  END ad_ready
  PIN ad_valid
    DIRECTION INPUT ;
    USE SIGNAL ;
    ANTENNAGATEAREA 0.741000 ;
    PORT
      LAYER Metal3 ;
        RECT 849.440 444.640 850.000 445.200 ;
    END
  END ad_valid
  PIN auth_ok
    DIRECTION OUTPUT ;
    USE SIGNAL ;
    ANTENNADIFFAREA 1.182800 ;
    PORT
      LAYER Metal2 ;
        RECT 441.280 849.440 441.840 850.000 ;
    END
  END auth_ok
  PIN busy
    DIRECTION OUTPUT ;
    USE SIGNAL ;
    ANTENNADIFFAREA 1.182800 ;
    PORT
      LAYER Metal3 ;
        RECT 849.440 476.000 850.000 476.560 ;
    END
  END busy
  PIN clk
    DIRECTION INPUT ;
    USE SIGNAL ;
    ANTENNAGATEAREA 1.183000 ;
    PORT
      LAYER Metal3 ;
        RECT 0.000 623.840 0.560 624.400 ;
    END
  END clk
  PIN dec_mode
    DIRECTION INPUT ;
    USE SIGNAL ;
    ANTENNAGATEAREA 0.741000 ;
    PORT
      LAYER Metal2 ;
        RECT 613.760 849.440 614.320 850.000 ;
    END
  END dec_mode
  PIN din_bytes[0]
    DIRECTION INPUT ;
    USE SIGNAL ;
    ANTENNAGATEAREA 0.741000 ;
    PORT
      LAYER Metal2 ;
        RECT 489.440 849.440 490.000 850.000 ;
    END
  END din_bytes[0]
  PIN din_bytes[1]
    DIRECTION INPUT ;
    USE SIGNAL ;
    ANTENNAGATEAREA 0.741000 ;
    PORT
      LAYER Metal2 ;
        RECT 509.600 849.440 510.160 850.000 ;
    END
  END din_bytes[1]
  PIN din_bytes[2]
    DIRECTION INPUT ;
    USE SIGNAL ;
    ANTENNAGATEAREA 0.741000 ;
    PORT
      LAYER Metal2 ;
        RECT 510.720 849.440 511.280 850.000 ;
    END
  END din_bytes[2]
  PIN din_bytes[3]
    DIRECTION INPUT ;
    USE SIGNAL ;
    ANTENNAGATEAREA 0.741000 ;
    PORT
      LAYER Metal2 ;
        RECT 492.800 849.440 493.360 850.000 ;
    END
  END din_bytes[3]
  PIN din_bytes[4]
    DIRECTION INPUT ;
    USE SIGNAL ;
    ANTENNAGATEAREA 0.741000 ;
    PORT
      LAYER Metal2 ;
        RECT 499.520 849.440 500.080 850.000 ;
    END
  END din_bytes[4]
  PIN din_data[0]
    DIRECTION INPUT ;
    USE SIGNAL ;
    ANTENNAGATEAREA 0.741000 ;
    PORT
      LAYER Metal3 ;
        RECT 849.440 372.960 850.000 373.520 ;
    END
  END din_data[0]
  PIN din_data[100]
    DIRECTION INPUT ;
    USE SIGNAL ;
    ANTENNAGATEAREA 0.741000 ;
    PORT
      LAYER Metal3 ;
        RECT 0.000 375.200 0.560 375.760 ;
    END
  END din_data[100]
  PIN din_data[101]
    DIRECTION INPUT ;
    USE SIGNAL ;
    ANTENNAGATEAREA 0.741000 ;
    PORT
      LAYER Metal3 ;
        RECT 0.000 453.600 0.560 454.160 ;
    END
  END din_data[101]
  PIN din_data[102]
    DIRECTION INPUT ;
    USE SIGNAL ;
    ANTENNAGATEAREA 0.741000 ;
    PORT
      LAYER Metal3 ;
        RECT 0.000 461.440 0.560 462.000 ;
    END
  END din_data[102]
  PIN din_data[103]
    DIRECTION INPUT ;
    USE SIGNAL ;
    ANTENNAGATEAREA 0.741000 ;
    PORT
      LAYER Metal3 ;
        RECT 0.000 450.240 0.560 450.800 ;
    END
  END din_data[103]
  PIN din_data[104]
    DIRECTION INPUT ;
    USE SIGNAL ;
    ANTENNAGATEAREA 0.741000 ;
    PORT
      LAYER Metal3 ;
        RECT 0.000 519.680 0.560 520.240 ;
    END
  END din_data[104]
  PIN din_data[105]
    DIRECTION INPUT ;
    USE SIGNAL ;
    ANTENNAGATEAREA 0.741000 ;
    PORT
      LAYER Metal3 ;
        RECT 0.000 521.920 0.560 522.480 ;
    END
  END din_data[105]
  PIN din_data[106]
    DIRECTION INPUT ;
    USE SIGNAL ;
    ANTENNAGATEAREA 0.741000 ;
    PORT
      LAYER Metal3 ;
        RECT 0.000 518.560 0.560 519.120 ;
    END
  END din_data[106]
  PIN din_data[107]
    DIRECTION INPUT ;
    USE SIGNAL ;
    ANTENNAGATEAREA 0.741000 ;
    PORT
      LAYER Metal2 ;
        RECT 366.240 849.440 366.800 850.000 ;
    END
  END din_data[107]
  PIN din_data[108]
    DIRECTION INPUT ;
    USE SIGNAL ;
    ANTENNAGATEAREA 0.741000 ;
    PORT
      LAYER Metal3 ;
        RECT 0.000 626.080 0.560 626.640 ;
    END
  END din_data[108]
  PIN din_data[109]
    DIRECTION INPUT ;
    USE SIGNAL ;
    ANTENNAGATEAREA 0.741000 ;
    PORT
      LAYER Metal3 ;
        RECT 0.000 614.880 0.560 615.440 ;
    END
  END din_data[109]
  PIN din_data[10]
    DIRECTION INPUT ;
    USE SIGNAL ;
    ANTENNAGATEAREA 0.741000 ;
    PORT
      LAYER Metal3 ;
        RECT 849.440 421.120 850.000 421.680 ;
    END
  END din_data[10]
  PIN din_data[110]
    DIRECTION INPUT ;
    USE SIGNAL ;
    ANTENNAGATEAREA 0.741000 ;
    PORT
      LAYER Metal2 ;
        RECT 247.520 849.440 248.080 850.000 ;
    END
  END din_data[110]
  PIN din_data[111]
    DIRECTION INPUT ;
    USE SIGNAL ;
    ANTENNAGATEAREA 0.741000 ;
    PORT
      LAYER Metal3 ;
        RECT 0.000 562.240 0.560 562.800 ;
    END
  END din_data[111]
  PIN din_data[112]
    DIRECTION INPUT ;
    USE SIGNAL ;
    ANTENNAGATEAREA 0.741000 ;
    PORT
      LAYER Metal2 ;
        RECT 444.640 849.440 445.200 850.000 ;
    END
  END din_data[112]
  PIN din_data[113]
    DIRECTION INPUT ;
    USE SIGNAL ;
    ANTENNAGATEAREA 0.741000 ;
    PORT
      LAYER Metal2 ;
        RECT 300.160 849.440 300.720 850.000 ;
    END
  END din_data[113]
  PIN din_data[114]
    DIRECTION INPUT ;
    USE SIGNAL ;
    ANTENNAGATEAREA 0.741000 ;
    PORT
      LAYER Metal2 ;
        RECT 352.800 849.440 353.360 850.000 ;
    END
  END din_data[114]
  PIN din_data[115]
    DIRECTION INPUT ;
    USE SIGNAL ;
    ANTENNAGATEAREA 0.741000 ;
    PORT
      LAYER Metal2 ;
        RECT 281.120 849.440 281.680 850.000 ;
    END
  END din_data[115]
  PIN din_data[116]
    DIRECTION INPUT ;
    USE SIGNAL ;
    ANTENNAGATEAREA 0.741000 ;
    PORT
      LAYER Metal2 ;
        RECT 328.160 849.440 328.720 850.000 ;
    END
  END din_data[116]
  PIN din_data[117]
    DIRECTION INPUT ;
    USE SIGNAL ;
    ANTENNAGATEAREA 0.741000 ;
    PORT
      LAYER Metal2 ;
        RECT 436.800 849.440 437.360 850.000 ;
    END
  END din_data[117]
  PIN din_data[118]
    DIRECTION INPUT ;
    USE SIGNAL ;
    ANTENNAGATEAREA 0.741000 ;
    PORT
      LAYER Metal2 ;
        RECT 464.800 849.440 465.360 850.000 ;
    END
  END din_data[118]
  PIN din_data[119]
    DIRECTION INPUT ;
    USE SIGNAL ;
    ANTENNAGATEAREA 0.741000 ;
    PORT
      LAYER Metal2 ;
        RECT 456.960 849.440 457.520 850.000 ;
    END
  END din_data[119]
  PIN din_data[11]
    DIRECTION INPUT ;
    USE SIGNAL ;
    ANTENNAGATEAREA 0.741000 ;
    PORT
      LAYER Metal3 ;
        RECT 849.440 404.320 850.000 404.880 ;
    END
  END din_data[11]
  PIN din_data[120]
    DIRECTION INPUT ;
    USE SIGNAL ;
    ANTENNAGATEAREA 0.741000 ;
    PORT
      LAYER Metal2 ;
        RECT 486.080 849.440 486.640 850.000 ;
    END
  END din_data[120]
  PIN din_data[121]
    DIRECTION INPUT ;
    USE SIGNAL ;
    ANTENNAGATEAREA 0.741000 ;
    PORT
      LAYER Metal2 ;
        RECT 524.160 849.440 524.720 850.000 ;
    END
  END din_data[121]
  PIN din_data[122]
    DIRECTION INPUT ;
    USE SIGNAL ;
    ANTENNAGATEAREA 0.741000 ;
    PORT
      LAYER Metal3 ;
        RECT 849.440 535.360 850.000 535.920 ;
    END
  END din_data[122]
  PIN din_data[123]
    DIRECTION INPUT ;
    USE SIGNAL ;
    ANTENNAGATEAREA 0.741000 ;
    PORT
      LAYER Metal2 ;
        RECT 601.440 849.440 602.000 850.000 ;
    END
  END din_data[123]
  PIN din_data[124]
    DIRECTION INPUT ;
    USE SIGNAL ;
    ANTENNAGATEAREA 0.741000 ;
    PORT
      LAYER Metal2 ;
        RECT 622.720 849.440 623.280 850.000 ;
    END
  END din_data[124]
  PIN din_data[125]
    DIRECTION INPUT ;
    USE SIGNAL ;
    ANTENNAGATEAREA 0.741000 ;
    PORT
      LAYER Metal3 ;
        RECT 849.440 583.520 850.000 584.080 ;
    END
  END din_data[125]
  PIN din_data[126]
    DIRECTION INPUT ;
    USE SIGNAL ;
    ANTENNAGATEAREA 0.741000 ;
    PORT
      LAYER Metal2 ;
        RECT 558.880 849.440 559.440 850.000 ;
    END
  END din_data[126]
  PIN din_data[127]
    DIRECTION INPUT ;
    USE SIGNAL ;
    ANTENNAGATEAREA 0.741000 ;
    PORT
      LAYER Metal3 ;
        RECT 849.440 542.080 850.000 542.640 ;
    END
  END din_data[127]
  PIN din_data[12]
    DIRECTION INPUT ;
    USE SIGNAL ;
    ANTENNAGATEAREA 0.741000 ;
    PORT
      LAYER Metal3 ;
        RECT 849.440 405.440 850.000 406.000 ;
    END
  END din_data[12]
  PIN din_data[13]
    DIRECTION INPUT ;
    USE SIGNAL ;
    ANTENNAGATEAREA 0.741000 ;
    PORT
      LAYER Metal3 ;
        RECT 849.440 425.600 850.000 426.160 ;
    END
  END din_data[13]
  PIN din_data[14]
    DIRECTION INPUT ;
    USE SIGNAL ;
    ANTENNAGATEAREA 0.741000 ;
    PORT
      LAYER Metal3 ;
        RECT 849.440 473.760 850.000 474.320 ;
    END
  END din_data[14]
  PIN din_data[15]
    DIRECTION INPUT ;
    USE SIGNAL ;
    ANTENNAGATEAREA 0.741000 ;
    PORT
      LAYER Metal3 ;
        RECT 849.440 490.560 850.000 491.120 ;
    END
  END din_data[15]
  PIN din_data[16]
    DIRECTION INPUT ;
    USE SIGNAL ;
    ANTENNAGATEAREA 0.741000 ;
    PORT
      LAYER Metal3 ;
        RECT 849.440 398.720 850.000 399.280 ;
    END
  END din_data[16]
  PIN din_data[17]
    DIRECTION INPUT ;
    USE SIGNAL ;
    ANTENNAGATEAREA 0.741000 ;
    PORT
      LAYER Metal2 ;
        RECT 388.640 0.000 389.200 0.560 ;
    END
  END din_data[17]
  PIN din_data[18]
    DIRECTION INPUT ;
    USE SIGNAL ;
    ANTENNAGATEAREA 0.741000 ;
    PORT
      LAYER Metal2 ;
        RECT 449.120 0.000 449.680 0.560 ;
    END
  END din_data[18]
  PIN din_data[19]
    DIRECTION INPUT ;
    USE SIGNAL ;
    ANTENNAGATEAREA 0.741000 ;
    PORT
      LAYER Metal2 ;
        RECT 393.120 0.000 393.680 0.560 ;
    END
  END din_data[19]
  PIN din_data[1]
    DIRECTION INPUT ;
    USE SIGNAL ;
    ANTENNAGATEAREA 0.741000 ;
    PORT
      LAYER Metal2 ;
        RECT 521.920 0.000 522.480 0.560 ;
    END
  END din_data[1]
  PIN din_data[20]
    DIRECTION INPUT ;
    USE SIGNAL ;
    ANTENNAGATEAREA 0.741000 ;
    PORT
      LAYER Metal2 ;
        RECT 453.600 0.000 454.160 0.560 ;
    END
  END din_data[20]
  PIN din_data[21]
    DIRECTION INPUT ;
    USE SIGNAL ;
    ANTENNAGATEAREA 0.741000 ;
    PORT
      LAYER Metal2 ;
        RECT 427.840 0.000 428.400 0.560 ;
    END
  END din_data[21]
  PIN din_data[22]
    DIRECTION INPUT ;
    USE SIGNAL ;
    ANTENNAGATEAREA 0.741000 ;
    PORT
      LAYER Metal2 ;
        RECT 375.200 0.000 375.760 0.560 ;
    END
  END din_data[22]
  PIN din_data[23]
    DIRECTION INPUT ;
    USE SIGNAL ;
    ANTENNAGATEAREA 0.741000 ;
    PORT
      LAYER Metal2 ;
        RECT 379.680 0.000 380.240 0.560 ;
    END
  END din_data[23]
  PIN din_data[24]
    DIRECTION INPUT ;
    USE SIGNAL ;
    ANTENNAGATEAREA 0.741000 ;
    PORT
      LAYER Metal2 ;
        RECT 378.560 0.000 379.120 0.560 ;
    END
  END din_data[24]
  PIN din_data[25]
    DIRECTION INPUT ;
    USE SIGNAL ;
    ANTENNAGATEAREA 0.741000 ;
    PORT
      LAYER Metal2 ;
        RECT 254.240 0.000 254.800 0.560 ;
    END
  END din_data[25]
  PIN din_data[26]
    DIRECTION INPUT ;
    USE SIGNAL ;
    ANTENNAGATEAREA 0.741000 ;
    PORT
      LAYER Metal3 ;
        RECT 0.000 356.160 0.560 356.720 ;
    END
  END din_data[26]
  PIN din_data[27]
    DIRECTION INPUT ;
    USE SIGNAL ;
    ANTENNAGATEAREA 0.741000 ;
    PORT
      LAYER Metal3 ;
        RECT 0.000 292.320 0.560 292.880 ;
    END
  END din_data[27]
  PIN din_data[28]
    DIRECTION INPUT ;
    USE SIGNAL ;
    ANTENNAGATEAREA 0.741000 ;
    PORT
      LAYER Metal3 ;
        RECT 0.000 266.560 0.560 267.120 ;
    END
  END din_data[28]
  PIN din_data[29]
    DIRECTION INPUT ;
    USE SIGNAL ;
    ANTENNAGATEAREA 0.741000 ;
    PORT
      LAYER Metal2 ;
        RECT 229.600 0.000 230.160 0.560 ;
    END
  END din_data[29]
  PIN din_data[2]
    DIRECTION INPUT ;
    USE SIGNAL ;
    ANTENNAGATEAREA 0.741000 ;
    PORT
      LAYER Metal2 ;
        RECT 518.560 0.000 519.120 0.560 ;
    END
  END din_data[2]
  PIN din_data[30]
    DIRECTION INPUT ;
    USE SIGNAL ;
    ANTENNAGATEAREA 0.741000 ;
    PORT
      LAYER Metal2 ;
        RECT 281.120 0.000 281.680 0.560 ;
    END
  END din_data[30]
  PIN din_data[31]
    DIRECTION INPUT ;
    USE SIGNAL ;
    ANTENNAGATEAREA 0.741000 ;
    PORT
      LAYER Metal3 ;
        RECT 0.000 358.400 0.560 358.960 ;
    END
  END din_data[31]
  PIN din_data[32]
    DIRECTION INPUT ;
    USE SIGNAL ;
    ANTENNAGATEAREA 0.741000 ;
    PORT
      LAYER Metal3 ;
        RECT 0.000 443.520 0.560 444.080 ;
    END
  END din_data[32]
  PIN din_data[33]
    DIRECTION INPUT ;
    USE SIGNAL ;
    ANTENNAGATEAREA 0.741000 ;
    PORT
      LAYER Metal3 ;
        RECT 0.000 403.200 0.560 403.760 ;
    END
  END din_data[33]
  PIN din_data[34]
    DIRECTION INPUT ;
    USE SIGNAL ;
    ANTENNAGATEAREA 0.741000 ;
    PORT
      LAYER Metal3 ;
        RECT 0.000 418.880 0.560 419.440 ;
    END
  END din_data[34]
  PIN din_data[35]
    DIRECTION INPUT ;
    USE SIGNAL ;
    ANTENNAGATEAREA 0.741000 ;
    PORT
      LAYER Metal3 ;
        RECT 0.000 394.240 0.560 394.800 ;
    END
  END din_data[35]
  PIN din_data[36]
    DIRECTION INPUT ;
    USE SIGNAL ;
    ANTENNAGATEAREA 0.741000 ;
    PORT
      LAYER Metal3 ;
        RECT 0.000 390.880 0.560 391.440 ;
    END
  END din_data[36]
  PIN din_data[37]
    DIRECTION INPUT ;
    USE SIGNAL ;
    ANTENNAGATEAREA 0.741000 ;
    PORT
      LAYER Metal3 ;
        RECT 0.000 428.960 0.560 429.520 ;
    END
  END din_data[37]
  PIN din_data[38]
    DIRECTION INPUT ;
    USE SIGNAL ;
    ANTENNAGATEAREA 0.741000 ;
    PORT
      LAYER Metal3 ;
        RECT 0.000 445.760 0.560 446.320 ;
    END
  END din_data[38]
  PIN din_data[39]
    DIRECTION INPUT ;
    USE SIGNAL ;
    ANTENNAGATEAREA 0.741000 ;
    PORT
      LAYER Metal3 ;
        RECT 0.000 422.240 0.560 422.800 ;
    END
  END din_data[39]
  PIN din_data[3]
    DIRECTION INPUT ;
    USE SIGNAL ;
    ANTENNAGATEAREA 0.741000 ;
    PORT
      LAYER Metal2 ;
        RECT 526.400 0.000 526.960 0.560 ;
    END
  END din_data[3]
  PIN din_data[40]
    DIRECTION INPUT ;
    USE SIGNAL ;
    ANTENNAGATEAREA 0.741000 ;
    PORT
      LAYER Metal3 ;
        RECT 0.000 481.600 0.560 482.160 ;
    END
  END din_data[40]
  PIN din_data[41]
    DIRECTION INPUT ;
    USE SIGNAL ;
    ANTENNAGATEAREA 0.741000 ;
    PORT
      LAYER Metal3 ;
        RECT 0.000 504.000 0.560 504.560 ;
    END
  END din_data[41]
  PIN din_data[42]
    DIRECTION INPUT ;
    USE SIGNAL ;
    ANTENNAGATEAREA 0.741000 ;
    PORT
      LAYER Metal3 ;
        RECT 0.000 505.120 0.560 505.680 ;
    END
  END din_data[42]
  PIN din_data[43]
    DIRECTION INPUT ;
    USE SIGNAL ;
    ANTENNAGATEAREA 0.741000 ;
    PORT
      LAYER Metal2 ;
        RECT 364.000 849.440 364.560 850.000 ;
    END
  END din_data[43]
  PIN din_data[44]
    DIRECTION INPUT ;
    USE SIGNAL ;
    ANTENNAGATEAREA 0.741000 ;
    PORT
      LAYER Metal3 ;
        RECT 0.000 549.920 0.560 550.480 ;
    END
  END din_data[44]
  PIN din_data[45]
    DIRECTION INPUT ;
    USE SIGNAL ;
    ANTENNAGATEAREA 0.741000 ;
    PORT
      LAYER Metal3 ;
        RECT 0.000 568.960 0.560 569.520 ;
    END
  END din_data[45]
  PIN din_data[46]
    DIRECTION INPUT ;
    USE SIGNAL ;
    ANTENNAGATEAREA 0.741000 ;
    PORT
      LAYER Metal2 ;
        RECT 265.440 849.440 266.000 850.000 ;
    END
  END din_data[46]
  PIN din_data[47]
    DIRECTION INPUT ;
    USE SIGNAL ;
    ANTENNAGATEAREA 0.741000 ;
    PORT
      LAYER Metal3 ;
        RECT 0.000 556.640 0.560 557.200 ;
    END
  END din_data[47]
  PIN din_data[48]
    DIRECTION INPUT ;
    USE SIGNAL ;
    ANTENNAGATEAREA 0.741000 ;
    PORT
      LAYER Metal2 ;
        RECT 458.080 849.440 458.640 850.000 ;
    END
  END din_data[48]
  PIN din_data[49]
    DIRECTION INPUT ;
    USE SIGNAL ;
    ANTENNAGATEAREA 0.741000 ;
    PORT
      LAYER Metal2 ;
        RECT 395.360 849.440 395.920 850.000 ;
    END
  END din_data[49]
  PIN din_data[4]
    DIRECTION INPUT ;
    USE SIGNAL ;
    ANTENNAGATEAREA 0.741000 ;
    PORT
      LAYER Metal3 ;
        RECT 849.440 319.200 850.000 319.760 ;
    END
  END din_data[4]
  PIN din_data[50]
    DIRECTION INPUT ;
    USE SIGNAL ;
    ANTENNAGATEAREA 0.741000 ;
    PORT
      LAYER Metal2 ;
        RECT 372.960 849.440 373.520 850.000 ;
    END
  END din_data[50]
  PIN din_data[51]
    DIRECTION INPUT ;
    USE SIGNAL ;
    ANTENNAGATEAREA 0.741000 ;
    PORT
      LAYER Metal2 ;
        RECT 371.840 849.440 372.400 850.000 ;
    END
  END din_data[51]
  PIN din_data[52]
    DIRECTION INPUT ;
    USE SIGNAL ;
    ANTENNAGATEAREA 0.741000 ;
    PORT
      LAYER Metal2 ;
        RECT 375.200 849.440 375.760 850.000 ;
    END
  END din_data[52]
  PIN din_data[53]
    DIRECTION INPUT ;
    USE SIGNAL ;
    ANTENNAGATEAREA 0.741000 ;
    PORT
      LAYER Metal2 ;
        RECT 414.400 849.440 414.960 850.000 ;
    END
  END din_data[53]
  PIN din_data[54]
    DIRECTION INPUT ;
    USE SIGNAL ;
    ANTENNAGATEAREA 0.741000 ;
    PORT
      LAYER Metal2 ;
        RECT 472.640 849.440 473.200 850.000 ;
    END
  END din_data[54]
  PIN din_data[55]
    DIRECTION INPUT ;
    USE SIGNAL ;
    ANTENNAGATEAREA 0.741000 ;
    PORT
      LAYER Metal2 ;
        RECT 424.480 849.440 425.040 850.000 ;
    END
  END din_data[55]
  PIN din_data[56]
    DIRECTION INPUT ;
    USE SIGNAL ;
    ANTENNAGATEAREA 0.741000 ;
    PORT
      LAYER Metal2 ;
        RECT 483.840 849.440 484.400 850.000 ;
    END
  END din_data[56]
  PIN din_data[57]
    DIRECTION INPUT ;
    USE SIGNAL ;
    ANTENNAGATEAREA 0.741000 ;
    PORT
      LAYER Metal2 ;
        RECT 525.280 849.440 525.840 850.000 ;
    END
  END din_data[57]
  PIN din_data[58]
    DIRECTION INPUT ;
    USE SIGNAL ;
    ANTENNAGATEAREA 0.741000 ;
    PORT
      LAYER Metal2 ;
        RECT 527.520 849.440 528.080 850.000 ;
    END
  END din_data[58]
  PIN din_data[59]
    DIRECTION INPUT ;
    USE SIGNAL ;
    ANTENNAGATEAREA 0.741000 ;
    PORT
      LAYER Metal2 ;
        RECT 579.040 849.440 579.600 850.000 ;
    END
  END din_data[59]
  PIN din_data[5]
    DIRECTION INPUT ;
    USE SIGNAL ;
    ANTENNAGATEAREA 0.741000 ;
    PORT
      LAYER Metal2 ;
        RECT 519.680 0.000 520.240 0.560 ;
    END
  END din_data[5]
  PIN din_data[60]
    DIRECTION INPUT ;
    USE SIGNAL ;
    ANTENNAGATEAREA 0.741000 ;
    PORT
      LAYER Metal3 ;
        RECT 849.440 618.240 850.000 618.800 ;
    END
  END din_data[60]
  PIN din_data[61]
    DIRECTION INPUT ;
    USE SIGNAL ;
    ANTENNAGATEAREA 0.741000 ;
    PORT
      LAYER Metal3 ;
        RECT 849.440 586.880 850.000 587.440 ;
    END
  END din_data[61]
  PIN din_data[62]
    DIRECTION INPUT ;
    USE SIGNAL ;
    ANTENNAGATEAREA 0.741000 ;
    PORT
      LAYER Metal2 ;
        RECT 530.880 849.440 531.440 850.000 ;
    END
  END din_data[62]
  PIN din_data[63]
    DIRECTION INPUT ;
    USE SIGNAL ;
    ANTENNAGATEAREA 0.741000 ;
    PORT
      LAYER Metal3 ;
        RECT 849.440 561.120 850.000 561.680 ;
    END
  END din_data[63]
  PIN din_data[64]
    DIRECTION INPUT ;
    USE SIGNAL ;
    ANTENNAGATEAREA 0.741000 ;
    PORT
      LAYER Metal3 ;
        RECT 849.440 361.760 850.000 362.320 ;
    END
  END din_data[64]
  PIN din_data[65]
    DIRECTION INPUT ;
    USE SIGNAL ;
    ANTENNAGATEAREA 0.741000 ;
    PORT
      LAYER Metal2 ;
        RECT 576.800 0.000 577.360 0.560 ;
    END
  END din_data[65]
  PIN din_data[66]
    DIRECTION INPUT ;
    USE SIGNAL ;
    ANTENNAGATEAREA 0.741000 ;
    PORT
      LAYER Metal2 ;
        RECT 548.800 0.000 549.360 0.560 ;
    END
  END din_data[66]
  PIN din_data[67]
    DIRECTION INPUT ;
    USE SIGNAL ;
    ANTENNAGATEAREA 0.741000 ;
    PORT
      LAYER Metal3 ;
        RECT 849.440 238.560 850.000 239.120 ;
    END
  END din_data[67]
  PIN din_data[68]
    DIRECTION INPUT ;
    USE SIGNAL ;
    ANTENNAGATEAREA 0.741000 ;
    PORT
      LAYER Metal3 ;
        RECT 849.440 296.800 850.000 297.360 ;
    END
  END din_data[68]
  PIN din_data[69]
    DIRECTION INPUT ;
    USE SIGNAL ;
    ANTENNAGATEAREA 0.741000 ;
    PORT
      LAYER Metal2 ;
        RECT 554.400 0.000 554.960 0.560 ;
    END
  END din_data[69]
  PIN din_data[6]
    DIRECTION INPUT ;
    USE SIGNAL ;
    ANTENNAGATEAREA 0.741000 ;
    PORT
      LAYER Metal2 ;
        RECT 577.920 0.000 578.480 0.560 ;
    END
  END din_data[6]
  PIN din_data[70]
    DIRECTION INPUT ;
    USE SIGNAL ;
    ANTENNAGATEAREA 0.741000 ;
    PORT
      LAYER Metal2 ;
        RECT 637.280 0.000 637.840 0.560 ;
    END
  END din_data[70]
  PIN din_data[71]
    DIRECTION INPUT ;
    USE SIGNAL ;
    ANTENNAGATEAREA 0.741000 ;
    PORT
      LAYER Metal2 ;
        RECT 611.520 0.000 612.080 0.560 ;
    END
  END din_data[71]
  PIN din_data[72]
    DIRECTION INPUT ;
    USE SIGNAL ;
    ANTENNAGATEAREA 0.741000 ;
    PORT
      LAYER Metal3 ;
        RECT 849.440 414.400 850.000 414.960 ;
    END
  END din_data[72]
  PIN din_data[73]
    DIRECTION INPUT ;
    USE SIGNAL ;
    ANTENNAGATEAREA 0.741000 ;
    PORT
      LAYER Metal3 ;
        RECT 849.440 486.080 850.000 486.640 ;
    END
  END din_data[73]
  PIN din_data[74]
    DIRECTION INPUT ;
    USE SIGNAL ;
    ANTENNAGATEAREA 0.741000 ;
    PORT
      LAYER Metal3 ;
        RECT 849.440 397.600 850.000 398.160 ;
    END
  END din_data[74]
  PIN din_data[75]
    DIRECTION INPUT ;
    USE SIGNAL ;
    ANTENNAGATEAREA 0.741000 ;
    PORT
      LAYER Metal3 ;
        RECT 849.440 349.440 850.000 350.000 ;
    END
  END din_data[75]
  PIN din_data[76]
    DIRECTION INPUT ;
    USE SIGNAL ;
    ANTENNAGATEAREA 0.741000 ;
    PORT
      LAYER Metal3 ;
        RECT 849.440 323.680 850.000 324.240 ;
    END
  END din_data[76]
  PIN din_data[77]
    DIRECTION INPUT ;
    USE SIGNAL ;
    ANTENNAGATEAREA 0.741000 ;
    PORT
      LAYER Metal3 ;
        RECT 849.440 393.120 850.000 393.680 ;
    END
  END din_data[77]
  PIN din_data[78]
    DIRECTION INPUT ;
    USE SIGNAL ;
    ANTENNAGATEAREA 0.741000 ;
    PORT
      LAYER Metal3 ;
        RECT 849.440 465.920 850.000 466.480 ;
    END
  END din_data[78]
  PIN din_data[79]
    DIRECTION INPUT ;
    USE SIGNAL ;
    ANTENNAGATEAREA 0.741000 ;
    PORT
      LAYER Metal3 ;
        RECT 849.440 498.400 850.000 498.960 ;
    END
  END din_data[79]
  PIN din_data[7]
    DIRECTION INPUT ;
    USE SIGNAL ;
    ANTENNAGATEAREA 0.741000 ;
    PORT
      LAYER Metal2 ;
        RECT 580.160 0.000 580.720 0.560 ;
    END
  END din_data[7]
  PIN din_data[80]
    DIRECTION INPUT ;
    USE SIGNAL ;
    ANTENNAGATEAREA 0.741000 ;
    PORT
      LAYER Metal3 ;
        RECT 849.440 400.960 850.000 401.520 ;
    END
  END din_data[80]
  PIN din_data[81]
    DIRECTION INPUT ;
    USE SIGNAL ;
    ANTENNAGATEAREA 0.741000 ;
    PORT
      LAYER Metal2 ;
        RECT 425.600 0.000 426.160 0.560 ;
    END
  END din_data[81]
  PIN din_data[82]
    DIRECTION INPUT ;
    USE SIGNAL ;
    ANTENNAGATEAREA 0.741000 ;
    PORT
      LAYER Metal2 ;
        RECT 486.080 0.000 486.640 0.560 ;
    END
  END din_data[82]
  PIN din_data[83]
    DIRECTION INPUT ;
    USE SIGNAL ;
    ANTENNAGATEAREA 0.741000 ;
    PORT
      LAYER Metal2 ;
        RECT 432.320 0.000 432.880 0.560 ;
    END
  END din_data[83]
  PIN din_data[84]
    DIRECTION INPUT ;
    USE SIGNAL ;
    ANTENNAGATEAREA 0.741000 ;
    PORT
      LAYER Metal2 ;
        RECT 474.880 0.000 475.440 0.560 ;
    END
  END din_data[84]
  PIN din_data[85]
    DIRECTION INPUT ;
    USE SIGNAL ;
    ANTENNAGATEAREA 0.741000 ;
    PORT
      LAYER Metal2 ;
        RECT 459.200 0.000 459.760 0.560 ;
    END
  END din_data[85]
  PIN din_data[86]
    DIRECTION INPUT ;
    USE SIGNAL ;
    ANTENNAGATEAREA 0.741000 ;
    PORT
      LAYER Metal2 ;
        RECT 360.640 0.000 361.200 0.560 ;
    END
  END din_data[86]
  PIN din_data[87]
    DIRECTION INPUT ;
    USE SIGNAL ;
    ANTENNAGATEAREA 0.741000 ;
    PORT
      LAYER Metal2 ;
        RECT 364.000 0.000 364.560 0.560 ;
    END
  END din_data[87]
  PIN din_data[88]
    DIRECTION INPUT ;
    USE SIGNAL ;
    ANTENNAGATEAREA 0.741000 ;
    PORT
      LAYER Metal2 ;
        RECT 343.840 0.000 344.400 0.560 ;
    END
  END din_data[88]
  PIN din_data[89]
    DIRECTION INPUT ;
    USE SIGNAL ;
    ANTENNAGATEAREA 0.741000 ;
    PORT
      LAYER Metal2 ;
        RECT 249.760 0.000 250.320 0.560 ;
    END
  END din_data[89]
  PIN din_data[8]
    DIRECTION INPUT ;
    USE SIGNAL ;
    ANTENNAGATEAREA 0.741000 ;
    PORT
      LAYER Metal3 ;
        RECT 849.440 411.040 850.000 411.600 ;
    END
  END din_data[8]
  PIN din_data[90]
    DIRECTION INPUT ;
    USE SIGNAL ;
    ANTENNAGATEAREA 0.741000 ;
    PORT
      LAYER Metal3 ;
        RECT 0.000 312.480 0.560 313.040 ;
    END
  END din_data[90]
  PIN din_data[91]
    DIRECTION INPUT ;
    USE SIGNAL ;
    ANTENNAGATEAREA 0.741000 ;
    PORT
      LAYER Metal2 ;
        RECT 295.680 0.000 296.240 0.560 ;
    END
  END din_data[91]
  PIN din_data[92]
    DIRECTION INPUT ;
    USE SIGNAL ;
    ANTENNAGATEAREA 0.741000 ;
    PORT
      LAYER Metal3 ;
        RECT 0.000 253.120 0.560 253.680 ;
    END
  END din_data[92]
  PIN din_data[93]
    DIRECTION INPUT ;
    USE SIGNAL ;
    ANTENNAGATEAREA 0.741000 ;
    PORT
      LAYER Metal2 ;
        RECT 208.320 0.000 208.880 0.560 ;
    END
  END din_data[93]
  PIN din_data[94]
    DIRECTION INPUT ;
    USE SIGNAL ;
    ANTENNAGATEAREA 0.741000 ;
    PORT
      LAYER Metal2 ;
        RECT 252.000 0.000 252.560 0.560 ;
    END
  END din_data[94]
  PIN din_data[95]
    DIRECTION INPUT ;
    USE SIGNAL ;
    ANTENNAGATEAREA 0.741000 ;
    PORT
      LAYER Metal2 ;
        RECT 323.680 0.000 324.240 0.560 ;
    END
  END din_data[95]
  PIN din_data[96]
    DIRECTION INPUT ;
    USE SIGNAL ;
    ANTENNAGATEAREA 0.741000 ;
    PORT
      LAYER Metal2 ;
        RECT 371.840 0.000 372.400 0.560 ;
    END
  END din_data[96]
  PIN din_data[97]
    DIRECTION INPUT ;
    USE SIGNAL ;
    ANTENNAGATEAREA 0.741000 ;
    PORT
      LAYER Metal3 ;
        RECT 0.000 414.400 0.560 414.960 ;
    END
  END din_data[97]
  PIN din_data[98]
    DIRECTION INPUT ;
    USE SIGNAL ;
    ANTENNAGATEAREA 0.741000 ;
    PORT
      LAYER Metal3 ;
        RECT 0.000 427.840 0.560 428.400 ;
    END
  END din_data[98]
  PIN din_data[99]
    DIRECTION INPUT ;
    USE SIGNAL ;
    ANTENNAGATEAREA 0.741000 ;
    PORT
      LAYER Metal3 ;
        RECT 0.000 344.960 0.560 345.520 ;
    END
  END din_data[99]
  PIN din_data[9]
    DIRECTION INPUT ;
    USE SIGNAL ;
    ANTENNAGATEAREA 0.741000 ;
    PORT
      LAYER Metal3 ;
        RECT 849.440 464.800 850.000 465.360 ;
    END
  END din_data[9]
  PIN din_last
    DIRECTION INPUT ;
    USE SIGNAL ;
    ANTENNAGATEAREA 0.741000 ;
    PORT
      LAYER Metal3 ;
        RECT 849.440 430.080 850.000 430.640 ;
    END
  END din_last
  PIN din_ready
    DIRECTION OUTPUT ;
    USE SIGNAL ;
    ANTENNADIFFAREA 1.182800 ;
    PORT
      LAYER Metal2 ;
        RECT 282.240 0.000 282.800 0.560 ;
    END
  END din_ready
  PIN din_valid
    DIRECTION INPUT ;
    USE SIGNAL ;
    ANTENNAGATEAREA 0.741000 ;
    PORT
      LAYER Metal2 ;
        RECT 557.760 849.440 558.320 850.000 ;
    END
  END din_valid
  PIN done
    DIRECTION OUTPUT ;
    USE SIGNAL ;
    ANTENNADIFFAREA 1.182800 ;
    PORT
      LAYER Metal3 ;
        RECT 849.440 143.360 850.000 143.920 ;
    END
  END done
  PIN dout_bytes[0]
    DIRECTION OUTPUT ;
    USE SIGNAL ;
    ANTENNADIFFAREA 1.182800 ;
    PORT
      LAYER Metal2 ;
        RECT 493.920 849.440 494.480 850.000 ;
    END
  END dout_bytes[0]
  PIN dout_bytes[1]
    DIRECTION OUTPUT ;
    USE SIGNAL ;
    ANTENNADIFFAREA 1.182800 ;
    PORT
      LAYER Metal2 ;
        RECT 516.320 849.440 516.880 850.000 ;
    END
  END dout_bytes[1]
  PIN dout_bytes[2]
    DIRECTION OUTPUT ;
    USE SIGNAL ;
    ANTENNADIFFAREA 1.182800 ;
    PORT
      LAYER Metal2 ;
        RECT 512.960 849.440 513.520 850.000 ;
    END
  END dout_bytes[2]
  PIN dout_bytes[3]
    DIRECTION OUTPUT ;
    USE SIGNAL ;
    ANTENNADIFFAREA 1.182800 ;
    PORT
      LAYER Metal2 ;
        RECT 495.040 849.440 495.600 850.000 ;
    END
  END dout_bytes[3]
  PIN dout_bytes[4]
    DIRECTION OUTPUT ;
    USE SIGNAL ;
    ANTENNADIFFAREA 1.182800 ;
    PORT
      LAYER Metal2 ;
        RECT 629.440 849.440 630.000 850.000 ;
    END
  END dout_bytes[4]
  PIN dout_data[0]
    DIRECTION OUTPUT ;
    USE SIGNAL ;
    ANTENNADIFFAREA 1.182800 ;
    PORT
      LAYER Metal3 ;
        RECT 849.440 369.600 850.000 370.160 ;
    END
  END dout_data[0]
  PIN dout_data[100]
    DIRECTION OUTPUT ;
    USE SIGNAL ;
    ANTENNADIFFAREA 1.182800 ;
    PORT
      LAYER Metal3 ;
        RECT 0.000 367.360 0.560 367.920 ;
    END
  END dout_data[100]
  PIN dout_data[101]
    DIRECTION OUTPUT ;
    USE SIGNAL ;
    ANTENNADIFFAREA 1.182800 ;
    PORT
      LAYER Metal3 ;
        RECT 0.000 442.400 0.560 442.960 ;
    END
  END dout_data[101]
  PIN dout_data[102]
    DIRECTION OUTPUT ;
    USE SIGNAL ;
    ANTENNADIFFAREA 1.182800 ;
    PORT
      LAYER Metal3 ;
        RECT 0.000 452.480 0.560 453.040 ;
    END
  END dout_data[102]
  PIN dout_data[103]
    DIRECTION OUTPUT ;
    USE SIGNAL ;
    ANTENNADIFFAREA 1.182800 ;
    PORT
      LAYER Metal3 ;
        RECT 0.000 446.880 0.560 447.440 ;
    END
  END dout_data[103]
  PIN dout_data[104]
    DIRECTION OUTPUT ;
    USE SIGNAL ;
    ANTENNADIFFAREA 1.182800 ;
    PORT
      LAYER Metal3 ;
        RECT 0.000 526.400 0.560 526.960 ;
    END
  END dout_data[104]
  PIN dout_data[105]
    DIRECTION OUTPUT ;
    USE SIGNAL ;
    ANTENNADIFFAREA 1.182800 ;
    PORT
      LAYER Metal3 ;
        RECT 0.000 527.520 0.560 528.080 ;
    END
  END dout_data[105]
  PIN dout_data[106]
    DIRECTION OUTPUT ;
    USE SIGNAL ;
    ANTENNADIFFAREA 1.182800 ;
    PORT
      LAYER Metal3 ;
        RECT 0.000 523.040 0.560 523.600 ;
    END
  END dout_data[106]
  PIN dout_data[107]
    DIRECTION OUTPUT ;
    USE SIGNAL ;
    ANTENNADIFFAREA 1.182800 ;
    PORT
      LAYER Metal3 ;
        RECT 0.000 599.200 0.560 599.760 ;
    END
  END dout_data[107]
  PIN dout_data[108]
    DIRECTION OUTPUT ;
    USE SIGNAL ;
    ANTENNADIFFAREA 1.182800 ;
    PORT
      LAYER Metal3 ;
        RECT 0.000 630.560 0.560 631.120 ;
    END
  END dout_data[108]
  PIN dout_data[109]
    DIRECTION OUTPUT ;
    USE SIGNAL ;
    ANTENNADIFFAREA 1.182800 ;
    PORT
      LAYER Metal3 ;
        RECT 0.000 621.600 0.560 622.160 ;
    END
  END dout_data[109]
  PIN dout_data[10]
    DIRECTION OUTPUT ;
    USE SIGNAL ;
    ANTENNADIFFAREA 1.182800 ;
    PORT
      LAYER Metal3 ;
        RECT 849.440 424.480 850.000 425.040 ;
    END
  END dout_data[10]
  PIN dout_data[110]
    DIRECTION OUTPUT ;
    USE SIGNAL ;
    ANTENNADIFFAREA 1.182800 ;
    PORT
      LAYER Metal3 ;
        RECT 0.000 619.360 0.560 619.920 ;
    END
  END dout_data[110]
  PIN dout_data[111]
    DIRECTION OUTPUT ;
    USE SIGNAL ;
    ANTENNADIFFAREA 1.182800 ;
    PORT
      LAYER Metal3 ;
        RECT 0.000 567.840 0.560 568.400 ;
    END
  END dout_data[111]
  PIN dout_data[112]
    DIRECTION OUTPUT ;
    USE SIGNAL ;
    ANTENNADIFFAREA 1.182800 ;
    PORT
      LAYER Metal2 ;
        RECT 460.320 849.440 460.880 850.000 ;
    END
  END dout_data[112]
  PIN dout_data[113]
    DIRECTION OUTPUT ;
    USE SIGNAL ;
    ANTENNADIFFAREA 1.182800 ;
    PORT
      LAYER Metal2 ;
        RECT 303.520 849.440 304.080 850.000 ;
    END
  END dout_data[113]
  PIN dout_data[114]
    DIRECTION OUTPUT ;
    USE SIGNAL ;
    ANTENNADIFFAREA 1.182800 ;
    PORT
      LAYER Metal2 ;
        RECT 362.880 849.440 363.440 850.000 ;
    END
  END dout_data[114]
  PIN dout_data[115]
    DIRECTION OUTPUT ;
    USE SIGNAL ;
    ANTENNADIFFAREA 1.182800 ;
    PORT
      LAYER Metal2 ;
        RECT 290.080 849.440 290.640 850.000 ;
    END
  END dout_data[115]
  PIN dout_data[116]
    DIRECTION OUTPUT ;
    USE SIGNAL ;
    ANTENNADIFFAREA 1.182800 ;
    PORT
      LAYER Metal2 ;
        RECT 338.240 849.440 338.800 850.000 ;
    END
  END dout_data[116]
  PIN dout_data[117]
    DIRECTION OUTPUT ;
    USE SIGNAL ;
    ANTENNADIFFAREA 1.182800 ;
    PORT
      LAYER Metal2 ;
        RECT 446.880 849.440 447.440 850.000 ;
    END
  END dout_data[117]
  PIN dout_data[118]
    DIRECTION OUTPUT ;
    USE SIGNAL ;
    ANTENNADIFFAREA 1.182800 ;
    PORT
      LAYER Metal2 ;
        RECT 470.400 849.440 470.960 850.000 ;
    END
  END dout_data[118]
  PIN dout_data[119]
    DIRECTION OUTPUT ;
    USE SIGNAL ;
    ANTENNADIFFAREA 1.182800 ;
    PORT
      LAYER Metal2 ;
        RECT 479.360 849.440 479.920 850.000 ;
    END
  END dout_data[119]
  PIN dout_data[11]
    DIRECTION OUTPUT ;
    USE SIGNAL ;
    ANTENNADIFFAREA 1.182800 ;
    PORT
      LAYER Metal3 ;
        RECT 849.440 406.560 850.000 407.120 ;
    END
  END dout_data[11]
  PIN dout_data[120]
    DIRECTION OUTPUT ;
    USE SIGNAL ;
    ANTENNADIFFAREA 1.182800 ;
    PORT
      LAYER Metal2 ;
        RECT 500.640 849.440 501.200 850.000 ;
    END
  END dout_data[120]
  PIN dout_data[121]
    DIRECTION OUTPUT ;
    USE SIGNAL ;
    ANTENNADIFFAREA 1.182800 ;
    PORT
      LAYER Metal2 ;
        RECT 535.360 849.440 535.920 850.000 ;
    END
  END dout_data[121]
  PIN dout_data[122]
    DIRECTION OUTPUT ;
    USE SIGNAL ;
    ANTENNADIFFAREA 1.182800 ;
    PORT
      LAYER Metal3 ;
        RECT 849.440 539.840 850.000 540.400 ;
    END
  END dout_data[122]
  PIN dout_data[123]
    DIRECTION OUTPUT ;
    USE SIGNAL ;
    ANTENNADIFFAREA 1.182800 ;
    PORT
      LAYER Metal2 ;
        RECT 612.640 849.440 613.200 850.000 ;
    END
  END dout_data[123]
  PIN dout_data[124]
    DIRECTION OUTPUT ;
    USE SIGNAL ;
    ANTENNADIFFAREA 1.182800 ;
    PORT
      LAYER Metal2 ;
        RECT 635.040 849.440 635.600 850.000 ;
    END
  END dout_data[124]
  PIN dout_data[125]
    DIRECTION OUTPUT ;
    USE SIGNAL ;
    ANTENNADIFFAREA 1.182800 ;
    PORT
      LAYER Metal3 ;
        RECT 849.440 590.240 850.000 590.800 ;
    END
  END dout_data[125]
  PIN dout_data[126]
    DIRECTION OUTPUT ;
    USE SIGNAL ;
    ANTENNADIFFAREA 1.182800 ;
    PORT
      LAYER Metal2 ;
        RECT 568.960 849.440 569.520 850.000 ;
    END
  END dout_data[126]
  PIN dout_data[127]
    DIRECTION OUTPUT ;
    USE SIGNAL ;
    ANTENNADIFFAREA 1.182800 ;
    PORT
      LAYER Metal3 ;
        RECT 849.440 547.680 850.000 548.240 ;
    END
  END dout_data[127]
  PIN dout_data[12]
    DIRECTION OUTPUT ;
    USE SIGNAL ;
    ANTENNADIFFAREA 1.182800 ;
    PORT
      LAYER Metal3 ;
        RECT 849.440 407.680 850.000 408.240 ;
    END
  END dout_data[12]
  PIN dout_data[13]
    DIRECTION OUTPUT ;
    USE SIGNAL ;
    ANTENNADIFFAREA 1.182800 ;
    PORT
      LAYER Metal3 ;
        RECT 849.440 427.840 850.000 428.400 ;
    END
  END dout_data[13]
  PIN dout_data[14]
    DIRECTION OUTPUT ;
    USE SIGNAL ;
    ANTENNADIFFAREA 1.182800 ;
    PORT
      LAYER Metal3 ;
        RECT 849.440 477.120 850.000 477.680 ;
    END
  END dout_data[14]
  PIN dout_data[15]
    DIRECTION OUTPUT ;
    USE SIGNAL ;
    ANTENNADIFFAREA 1.182800 ;
    PORT
      LAYER Metal3 ;
        RECT 849.440 483.840 850.000 484.400 ;
    END
  END dout_data[15]
  PIN dout_data[16]
    DIRECTION OUTPUT ;
    USE SIGNAL ;
    ANTENNADIFFAREA 1.182800 ;
    PORT
      LAYER Metal2 ;
        RECT 461.440 0.000 462.000 0.560 ;
    END
  END dout_data[16]
  PIN dout_data[17]
    DIRECTION OUTPUT ;
    USE SIGNAL ;
    ANTENNADIFFAREA 1.182800 ;
    PORT
      LAYER Metal2 ;
        RECT 403.200 0.000 403.760 0.560 ;
    END
  END dout_data[17]
  PIN dout_data[18]
    DIRECTION OUTPUT ;
    USE SIGNAL ;
    ANTENNADIFFAREA 1.182800 ;
    PORT
      LAYER Metal2 ;
        RECT 455.840 0.000 456.400 0.560 ;
    END
  END dout_data[18]
  PIN dout_data[19]
    DIRECTION OUTPUT ;
    USE SIGNAL ;
    ANTENNADIFFAREA 1.182800 ;
    PORT
      LAYER Metal2 ;
        RECT 394.240 0.000 394.800 0.560 ;
    END
  END dout_data[19]
  PIN dout_data[1]
    DIRECTION OUTPUT ;
    USE SIGNAL ;
    ANTENNADIFFAREA 1.182800 ;
    PORT
      LAYER Metal2 ;
        RECT 529.760 0.000 530.320 0.560 ;
    END
  END dout_data[1]
  PIN dout_data[20]
    DIRECTION OUTPUT ;
    USE SIGNAL ;
    ANTENNADIFFAREA 1.182800 ;
    PORT
      LAYER Metal2 ;
        RECT 462.560 0.000 463.120 0.560 ;
    END
  END dout_data[20]
  PIN dout_data[21]
    DIRECTION OUTPUT ;
    USE SIGNAL ;
    ANTENNADIFFAREA 1.182800 ;
    PORT
      LAYER Metal2 ;
        RECT 434.560 0.000 435.120 0.560 ;
    END
  END dout_data[21]
  PIN dout_data[22]
    DIRECTION OUTPUT ;
    USE SIGNAL ;
    ANTENNADIFFAREA 1.182800 ;
    PORT
      LAYER Metal2 ;
        RECT 383.040 0.000 383.600 0.560 ;
    END
  END dout_data[22]
  PIN dout_data[23]
    DIRECTION OUTPUT ;
    USE SIGNAL ;
    ANTENNADIFFAREA 1.182800 ;
    PORT
      LAYER Metal2 ;
        RECT 387.520 0.000 388.080 0.560 ;
    END
  END dout_data[23]
  PIN dout_data[24]
    DIRECTION OUTPUT ;
    USE SIGNAL ;
    ANTENNADIFFAREA 1.182800 ;
    PORT
      LAYER Metal2 ;
        RECT 372.960 0.000 373.520 0.560 ;
    END
  END dout_data[24]
  PIN dout_data[25]
    DIRECTION OUTPUT ;
    USE SIGNAL ;
    ANTENNADIFFAREA 1.182800 ;
    PORT
      LAYER Metal2 ;
        RECT 253.120 0.000 253.680 0.560 ;
    END
  END dout_data[25]
  PIN dout_data[26]
    DIRECTION OUTPUT ;
    USE SIGNAL ;
    ANTENNADIFFAREA 1.182800 ;
    PORT
      LAYER Metal3 ;
        RECT 0.000 357.280 0.560 357.840 ;
    END
  END dout_data[26]
  PIN dout_data[27]
    DIRECTION OUTPUT ;
    USE SIGNAL ;
    ANTENNADIFFAREA 1.182800 ;
    PORT
      LAYER Metal3 ;
        RECT 0.000 284.480 0.560 285.040 ;
    END
  END dout_data[27]
  PIN dout_data[28]
    DIRECTION OUTPUT ;
    USE SIGNAL ;
    ANTENNADIFFAREA 1.182800 ;
    PORT
      LAYER Metal3 ;
        RECT 0.000 259.840 0.560 260.400 ;
    END
  END dout_data[28]
  PIN dout_data[29]
    DIRECTION OUTPUT ;
    USE SIGNAL ;
    ANTENNADIFFAREA 1.182800 ;
    PORT
      LAYER Metal2 ;
        RECT 232.960 0.000 233.520 0.560 ;
    END
  END dout_data[29]
  PIN dout_data[2]
    DIRECTION OUTPUT ;
    USE SIGNAL ;
    ANTENNADIFFAREA 1.182800 ;
    PORT
      LAYER Metal2 ;
        RECT 528.640 0.000 529.200 0.560 ;
    END
  END dout_data[2]
  PIN dout_data[30]
    DIRECTION OUTPUT ;
    USE SIGNAL ;
    ANTENNADIFFAREA 1.182800 ;
    PORT
      LAYER Metal2 ;
        RECT 278.880 0.000 279.440 0.560 ;
    END
  END dout_data[30]
  PIN dout_data[31]
    DIRECTION OUTPUT ;
    USE SIGNAL ;
    ANTENNADIFFAREA 1.182800 ;
    PORT
      LAYER Metal3 ;
        RECT 0.000 353.920 0.560 354.480 ;
    END
  END dout_data[31]
  PIN dout_data[32]
    DIRECTION OUTPUT ;
    USE SIGNAL ;
    ANTENNADIFFAREA 1.182800 ;
    PORT
      LAYER Metal2 ;
        RECT 439.040 849.440 439.600 850.000 ;
    END
  END dout_data[32]
  PIN dout_data[33]
    DIRECTION OUTPUT ;
    USE SIGNAL ;
    ANTENNADIFFAREA 1.182800 ;
    PORT
      LAYER Metal3 ;
        RECT 0.000 402.080 0.560 402.640 ;
    END
  END dout_data[33]
  PIN dout_data[34]
    DIRECTION OUTPUT ;
    USE SIGNAL ;
    ANTENNADIFFAREA 1.182800 ;
    PORT
      LAYER Metal3 ;
        RECT 0.000 415.520 0.560 416.080 ;
    END
  END dout_data[34]
  PIN dout_data[35]
    DIRECTION OUTPUT ;
    USE SIGNAL ;
    ANTENNADIFFAREA 1.182800 ;
    PORT
      LAYER Metal3 ;
        RECT 0.000 398.720 0.560 399.280 ;
    END
  END dout_data[35]
  PIN dout_data[36]
    DIRECTION OUTPUT ;
    USE SIGNAL ;
    ANTENNADIFFAREA 1.182800 ;
    PORT
      LAYER Metal3 ;
        RECT 0.000 393.120 0.560 393.680 ;
    END
  END dout_data[36]
  PIN dout_data[37]
    DIRECTION OUTPUT ;
    USE SIGNAL ;
    ANTENNADIFFAREA 1.182800 ;
    PORT
      LAYER Metal3 ;
        RECT 0.000 424.480 0.560 425.040 ;
    END
  END dout_data[37]
  PIN dout_data[38]
    DIRECTION OUTPUT ;
    USE SIGNAL ;
    ANTENNADIFFAREA 1.182800 ;
    PORT
      LAYER Metal3 ;
        RECT 0.000 441.280 0.560 441.840 ;
    END
  END dout_data[38]
  PIN dout_data[39]
    DIRECTION OUTPUT ;
    USE SIGNAL ;
    ANTENNADIFFAREA 1.182800 ;
    PORT
      LAYER Metal3 ;
        RECT 0.000 412.160 0.560 412.720 ;
    END
  END dout_data[39]
  PIN dout_data[3]
    DIRECTION OUTPUT ;
    USE SIGNAL ;
    ANTENNADIFFAREA 1.182800 ;
    PORT
      LAYER Metal2 ;
        RECT 530.880 0.000 531.440 0.560 ;
    END
  END dout_data[3]
  PIN dout_data[40]
    DIRECTION OUTPUT ;
    USE SIGNAL ;
    ANTENNADIFFAREA 1.182800 ;
    PORT
      LAYER Metal3 ;
        RECT 0.000 497.280 0.560 497.840 ;
    END
  END dout_data[40]
  PIN dout_data[41]
    DIRECTION OUTPUT ;
    USE SIGNAL ;
    ANTENNADIFFAREA 1.182800 ;
    PORT
      LAYER Metal3 ;
        RECT 0.000 502.880 0.560 503.440 ;
    END
  END dout_data[41]
  PIN dout_data[42]
    DIRECTION OUTPUT ;
    USE SIGNAL ;
    ANTENNADIFFAREA 1.182800 ;
    PORT
      LAYER Metal3 ;
        RECT 0.000 499.520 0.560 500.080 ;
    END
  END dout_data[42]
  PIN dout_data[43]
    DIRECTION OUTPUT ;
    USE SIGNAL ;
    ANTENNADIFFAREA 1.182800 ;
    PORT
      LAYER Metal2 ;
        RECT 376.320 849.440 376.880 850.000 ;
    END
  END dout_data[43]
  PIN dout_data[44]
    DIRECTION OUTPUT ;
    USE SIGNAL ;
    ANTENNADIFFAREA 1.182800 ;
    PORT
      LAYER Metal3 ;
        RECT 0.000 548.800 0.560 549.360 ;
    END
  END dout_data[44]
  PIN dout_data[45]
    DIRECTION OUTPUT ;
    USE SIGNAL ;
    ANTENNADIFFAREA 1.182800 ;
    PORT
      LAYER Metal3 ;
        RECT 0.000 570.080 0.560 570.640 ;
    END
  END dout_data[45]
  PIN dout_data[46]
    DIRECTION OUTPUT ;
    USE SIGNAL ;
    ANTENNADIFFAREA 1.182800 ;
    PORT
      LAYER Metal2 ;
        RECT 274.400 849.440 274.960 850.000 ;
    END
  END dout_data[46]
  PIN dout_data[47]
    DIRECTION OUTPUT ;
    USE SIGNAL ;
    ANTENNADIFFAREA 1.182800 ;
    PORT
      LAYER Metal3 ;
        RECT 0.000 557.760 0.560 558.320 ;
    END
  END dout_data[47]
  PIN dout_data[48]
    DIRECTION OUTPUT ;
    USE SIGNAL ;
    ANTENNADIFFAREA 1.182800 ;
    PORT
      LAYER Metal2 ;
        RECT 476.000 849.440 476.560 850.000 ;
    END
  END dout_data[48]
  PIN dout_data[49]
    DIRECTION OUTPUT ;
    USE SIGNAL ;
    ANTENNADIFFAREA 1.182800 ;
    PORT
      LAYER Metal2 ;
        RECT 406.560 849.440 407.120 850.000 ;
    END
  END dout_data[49]
  PIN dout_data[4]
    DIRECTION OUTPUT ;
    USE SIGNAL ;
    ANTENNADIFFAREA 1.182800 ;
    PORT
      LAYER Metal3 ;
        RECT 849.440 314.720 850.000 315.280 ;
    END
  END dout_data[4]
  PIN dout_data[50]
    DIRECTION OUTPUT ;
    USE SIGNAL ;
    ANTENNADIFFAREA 1.182800 ;
    PORT
      LAYER Metal2 ;
        RECT 388.640 849.440 389.200 850.000 ;
    END
  END dout_data[50]
  PIN dout_data[51]
    DIRECTION OUTPUT ;
    USE SIGNAL ;
    ANTENNADIFFAREA 1.182800 ;
    PORT
      LAYER Metal2 ;
        RECT 383.040 849.440 383.600 850.000 ;
    END
  END dout_data[51]
  PIN dout_data[52]
    DIRECTION OUTPUT ;
    USE SIGNAL ;
    ANTENNADIFFAREA 1.182800 ;
    PORT
      LAYER Metal2 ;
        RECT 393.120 849.440 393.680 850.000 ;
    END
  END dout_data[52]
  PIN dout_data[53]
    DIRECTION OUTPUT ;
    USE SIGNAL ;
    ANTENNADIFFAREA 1.182800 ;
    PORT
      LAYER Metal2 ;
        RECT 431.200 849.440 431.760 850.000 ;
    END
  END dout_data[53]
  PIN dout_data[54]
    DIRECTION OUTPUT ;
    USE SIGNAL ;
    ANTENNADIFFAREA 1.182800 ;
    PORT
      LAYER Metal2 ;
        RECT 477.120 849.440 477.680 850.000 ;
    END
  END dout_data[54]
  PIN dout_data[55]
    DIRECTION OUTPUT ;
    USE SIGNAL ;
    ANTENNADIFFAREA 1.182800 ;
    PORT
      LAYER Metal2 ;
        RECT 440.160 849.440 440.720 850.000 ;
    END
  END dout_data[55]
  PIN dout_data[56]
    DIRECTION OUTPUT ;
    USE SIGNAL ;
    ANTENNADIFFAREA 1.182800 ;
    PORT
      LAYER Metal3 ;
        RECT 849.440 493.920 850.000 494.480 ;
    END
  END dout_data[56]
  PIN dout_data[57]
    DIRECTION OUTPUT ;
    USE SIGNAL ;
    ANTENNADIFFAREA 1.182800 ;
    PORT
      LAYER Metal2 ;
        RECT 547.680 849.440 548.240 850.000 ;
    END
  END dout_data[57]
  PIN dout_data[58]
    DIRECTION OUTPUT ;
    USE SIGNAL ;
    ANTENNADIFFAREA 1.182800 ;
    PORT
      LAYER Metal3 ;
        RECT 849.440 496.160 850.000 496.720 ;
    END
  END dout_data[58]
  PIN dout_data[59]
    DIRECTION OUTPUT ;
    USE SIGNAL ;
    ANTENNADIFFAREA 1.182800 ;
    PORT
      LAYER Metal3 ;
        RECT 849.440 612.640 850.000 613.200 ;
    END
  END dout_data[59]
  PIN dout_data[5]
    DIRECTION OUTPUT ;
    USE SIGNAL ;
    ANTENNADIFFAREA 1.182800 ;
    PORT
      LAYER Metal2 ;
        RECT 517.440 0.000 518.000 0.560 ;
    END
  END dout_data[5]
  PIN dout_data[60]
    DIRECTION OUTPUT ;
    USE SIGNAL ;
    ANTENNADIFFAREA 1.182800 ;
    PORT
      LAYER Metal3 ;
        RECT 849.440 610.400 850.000 610.960 ;
    END
  END dout_data[60]
  PIN dout_data[61]
    DIRECTION OUTPUT ;
    USE SIGNAL ;
    ANTENNADIFFAREA 1.182800 ;
    PORT
      LAYER Metal3 ;
        RECT 849.440 596.960 850.000 597.520 ;
    END
  END dout_data[61]
  PIN dout_data[62]
    DIRECTION OUTPUT ;
    USE SIGNAL ;
    ANTENNADIFFAREA 1.182800 ;
    PORT
      LAYER Metal2 ;
        RECT 551.040 849.440 551.600 850.000 ;
    END
  END dout_data[62]
  PIN dout_data[63]
    DIRECTION OUTPUT ;
    USE SIGNAL ;
    ANTENNADIFFAREA 1.182800 ;
    PORT
      LAYER Metal3 ;
        RECT 849.440 562.240 850.000 562.800 ;
    END
  END dout_data[63]
  PIN dout_data[64]
    DIRECTION OUTPUT ;
    USE SIGNAL ;
    ANTENNADIFFAREA 1.182800 ;
    PORT
      LAYER Metal3 ;
        RECT 849.440 357.280 850.000 357.840 ;
    END
  END dout_data[64]
  PIN dout_data[65]
    DIRECTION OUTPUT ;
    USE SIGNAL ;
    ANTENNADIFFAREA 1.182800 ;
    PORT
      LAYER Metal3 ;
        RECT 849.440 286.720 850.000 287.280 ;
    END
  END dout_data[65]
  PIN dout_data[66]
    DIRECTION OUTPUT ;
    USE SIGNAL ;
    ANTENNADIFFAREA 1.182800 ;
    PORT
      LAYER Metal2 ;
        RECT 558.880 0.000 559.440 0.560 ;
    END
  END dout_data[66]
  PIN dout_data[67]
    DIRECTION OUTPUT ;
    USE SIGNAL ;
    ANTENNADIFFAREA 1.182800 ;
    PORT
      LAYER Metal3 ;
        RECT 849.440 230.720 850.000 231.280 ;
    END
  END dout_data[67]
  PIN dout_data[68]
    DIRECTION OUTPUT ;
    USE SIGNAL ;
    ANTENNADIFFAREA 1.182800 ;
    PORT
      LAYER Metal3 ;
        RECT 849.440 295.680 850.000 296.240 ;
    END
  END dout_data[68]
  PIN dout_data[69]
    DIRECTION OUTPUT ;
    USE SIGNAL ;
    ANTENNADIFFAREA 1.182800 ;
    PORT
      LAYER Metal3 ;
        RECT 849.440 204.960 850.000 205.520 ;
    END
  END dout_data[69]
  PIN dout_data[6]
    DIRECTION OUTPUT ;
    USE SIGNAL ;
    ANTENNADIFFAREA 1.182800 ;
    PORT
      LAYER Metal2 ;
        RECT 582.400 0.000 582.960 0.560 ;
    END
  END dout_data[6]
  PIN dout_data[70]
    DIRECTION OUTPUT ;
    USE SIGNAL ;
    ANTENNADIFFAREA 1.182800 ;
    PORT
      LAYER Metal3 ;
        RECT 849.440 193.760 850.000 194.320 ;
    END
  END dout_data[70]
  PIN dout_data[71]
    DIRECTION OUTPUT ;
    USE SIGNAL ;
    ANTENNADIFFAREA 1.182800 ;
    PORT
      LAYER Metal2 ;
        RECT 618.240 0.000 618.800 0.560 ;
    END
  END dout_data[71]
  PIN dout_data[72]
    DIRECTION OUTPUT ;
    USE SIGNAL ;
    ANTENNADIFFAREA 1.182800 ;
    PORT
      LAYER Metal3 ;
        RECT 849.440 422.240 850.000 422.800 ;
    END
  END dout_data[72]
  PIN dout_data[73]
    DIRECTION OUTPUT ;
    USE SIGNAL ;
    ANTENNADIFFAREA 1.182800 ;
    PORT
      LAYER Metal3 ;
        RECT 849.440 489.440 850.000 490.000 ;
    END
  END dout_data[73]
  PIN dout_data[74]
    DIRECTION OUTPUT ;
    USE SIGNAL ;
    ANTENNADIFFAREA 1.182800 ;
    PORT
      LAYER Metal3 ;
        RECT 849.440 402.080 850.000 402.640 ;
    END
  END dout_data[74]
  PIN dout_data[75]
    DIRECTION OUTPUT ;
    USE SIGNAL ;
    ANTENNADIFFAREA 1.182800 ;
    PORT
      LAYER Metal3 ;
        RECT 849.440 343.840 850.000 344.400 ;
    END
  END dout_data[75]
  PIN dout_data[76]
    DIRECTION OUTPUT ;
    USE SIGNAL ;
    ANTENNADIFFAREA 1.182800 ;
    PORT
      LAYER Metal3 ;
        RECT 849.440 324.800 850.000 325.360 ;
    END
  END dout_data[76]
  PIN dout_data[77]
    DIRECTION OUTPUT ;
    USE SIGNAL ;
    ANTENNADIFFAREA 1.182800 ;
    PORT
      LAYER Metal3 ;
        RECT 849.440 388.640 850.000 389.200 ;
    END
  END dout_data[77]
  PIN dout_data[78]
    DIRECTION OUTPUT ;
    USE SIGNAL ;
    ANTENNADIFFAREA 1.182800 ;
    PORT
      LAYER Metal3 ;
        RECT 849.440 463.680 850.000 464.240 ;
    END
  END dout_data[78]
  PIN dout_data[79]
    DIRECTION OUTPUT ;
    USE SIGNAL ;
    ANTENNADIFFAREA 1.182800 ;
    PORT
      LAYER Metal3 ;
        RECT 849.440 499.520 850.000 500.080 ;
    END
  END dout_data[79]
  PIN dout_data[7]
    DIRECTION OUTPUT ;
    USE SIGNAL ;
    ANTENNADIFFAREA 1.182800 ;
    PORT
      LAYER Metal2 ;
        RECT 584.640 0.000 585.200 0.560 ;
    END
  END dout_data[7]
  PIN dout_data[80]
    DIRECTION OUTPUT ;
    USE SIGNAL ;
    ANTENNADIFFAREA 1.182800 ;
    PORT
      LAYER Metal3 ;
        RECT 849.440 399.840 850.000 400.400 ;
    END
  END dout_data[80]
  PIN dout_data[81]
    DIRECTION OUTPUT ;
    USE SIGNAL ;
    ANTENNADIFFAREA 1.182800 ;
    PORT
      LAYER Metal2 ;
        RECT 433.440 0.000 434.000 0.560 ;
    END
  END dout_data[81]
  PIN dout_data[82]
    DIRECTION OUTPUT ;
    USE SIGNAL ;
    ANTENNADIFFAREA 1.182800 ;
    PORT
      LAYER Metal2 ;
        RECT 493.920 0.000 494.480 0.560 ;
    END
  END dout_data[82]
  PIN dout_data[83]
    DIRECTION OUTPUT ;
    USE SIGNAL ;
    ANTENNADIFFAREA 1.182800 ;
    PORT
      LAYER Metal2 ;
        RECT 439.040 0.000 439.600 0.560 ;
    END
  END dout_data[83]
  PIN dout_data[84]
    DIRECTION OUTPUT ;
    USE SIGNAL ;
    ANTENNADIFFAREA 1.182800 ;
    PORT
      LAYER Metal2 ;
        RECT 487.200 0.000 487.760 0.560 ;
    END
  END dout_data[84]
  PIN dout_data[85]
    DIRECTION OUTPUT ;
    USE SIGNAL ;
    ANTENNADIFFAREA 1.182800 ;
    PORT
      LAYER Metal2 ;
        RECT 463.680 0.000 464.240 0.560 ;
    END
  END dout_data[85]
  PIN dout_data[86]
    DIRECTION OUTPUT ;
    USE SIGNAL ;
    ANTENNADIFFAREA 1.182800 ;
    PORT
      LAYER Metal2 ;
        RECT 365.120 0.000 365.680 0.560 ;
    END
  END dout_data[86]
  PIN dout_data[87]
    DIRECTION OUTPUT ;
    USE SIGNAL ;
    ANTENNADIFFAREA 1.182800 ;
    PORT
      LAYER Metal2 ;
        RECT 367.360 0.000 367.920 0.560 ;
    END
  END dout_data[87]
  PIN dout_data[88]
    DIRECTION OUTPUT ;
    USE SIGNAL ;
    ANTENNADIFFAREA 1.182800 ;
    PORT
      LAYER Metal2 ;
        RECT 344.960 0.000 345.520 0.560 ;
    END
  END dout_data[88]
  PIN dout_data[89]
    DIRECTION OUTPUT ;
    USE SIGNAL ;
    ANTENNADIFFAREA 1.182800 ;
    PORT
      LAYER Metal2 ;
        RECT 248.640 0.000 249.200 0.560 ;
    END
  END dout_data[89]
  PIN dout_data[8]
    DIRECTION OUTPUT ;
    USE SIGNAL ;
    ANTENNADIFFAREA 1.182800 ;
    PORT
      LAYER Metal3 ;
        RECT 849.440 420.000 850.000 420.560 ;
    END
  END dout_data[8]
  PIN dout_data[90]
    DIRECTION OUTPUT ;
    USE SIGNAL ;
    ANTENNADIFFAREA 1.182800 ;
    PORT
      LAYER Metal3 ;
        RECT 0.000 306.880 0.560 307.440 ;
    END
  END dout_data[90]
  PIN dout_data[91]
    DIRECTION OUTPUT ;
    USE SIGNAL ;
    ANTENNADIFFAREA 1.182800 ;
    PORT
      LAYER Metal2 ;
        RECT 304.640 0.000 305.200 0.560 ;
    END
  END dout_data[91]
  PIN dout_data[92]
    DIRECTION OUTPUT ;
    USE SIGNAL ;
    ANTENNADIFFAREA 1.182800 ;
    PORT
      LAYER Metal3 ;
        RECT 0.000 247.520 0.560 248.080 ;
    END
  END dout_data[92]
  PIN dout_data[93]
    DIRECTION OUTPUT ;
    USE SIGNAL ;
    ANTENNADIFFAREA 1.182800 ;
    PORT
      LAYER Metal2 ;
        RECT 209.440 0.000 210.000 0.560 ;
    END
  END dout_data[93]
  PIN dout_data[94]
    DIRECTION OUTPUT ;
    USE SIGNAL ;
    ANTENNADIFFAREA 1.182800 ;
    PORT
      LAYER Metal2 ;
        RECT 256.480 0.000 257.040 0.560 ;
    END
  END dout_data[94]
  PIN dout_data[95]
    DIRECTION OUTPUT ;
    USE SIGNAL ;
    ANTENNADIFFAREA 1.182800 ;
    PORT
      LAYER Metal2 ;
        RECT 322.560 0.000 323.120 0.560 ;
    END
  END dout_data[95]
  PIN dout_data[96]
    DIRECTION OUTPUT ;
    USE SIGNAL ;
    ANTENNADIFFAREA 1.182800 ;
    PORT
      LAYER Metal2 ;
        RECT 376.320 0.000 376.880 0.560 ;
    END
  END dout_data[96]
  PIN dout_data[97]
    DIRECTION OUTPUT ;
    USE SIGNAL ;
    ANTENNADIFFAREA 1.182800 ;
    PORT
      LAYER Metal3 ;
        RECT 0.000 417.760 0.560 418.320 ;
    END
  END dout_data[97]
  PIN dout_data[98]
    DIRECTION OUTPUT ;
    USE SIGNAL ;
    ANTENNADIFFAREA 1.182800 ;
    PORT
      LAYER Metal3 ;
        RECT 0.000 423.360 0.560 423.920 ;
    END
  END dout_data[98]
  PIN dout_data[99]
    DIRECTION OUTPUT ;
    USE SIGNAL ;
    ANTENNADIFFAREA 1.182800 ;
    PORT
      LAYER Metal3 ;
        RECT 0.000 347.200 0.560 347.760 ;
    END
  END dout_data[99]
  PIN dout_data[9]
    DIRECTION OUTPUT ;
    USE SIGNAL ;
    ANTENNADIFFAREA 1.182800 ;
    PORT
      LAYER Metal3 ;
        RECT 849.440 468.160 850.000 468.720 ;
    END
  END dout_data[9]
  PIN dout_last
    DIRECTION OUTPUT ;
    USE SIGNAL ;
    ANTENNADIFFAREA 1.182800 ;
    PORT
      LAYER Metal2 ;
        RECT 518.560 849.440 519.120 850.000 ;
    END
  END dout_last
  PIN dout_valid
    DIRECTION OUTPUT ;
    USE SIGNAL ;
    ANTENNADIFFAREA 1.182800 ;
    PORT
      LAYER Metal2 ;
        RECT 607.040 849.440 607.600 850.000 ;
    END
  END dout_valid
  PIN k0_in[0]
    DIRECTION INPUT ;
    USE SIGNAL ;
    ANTENNAGATEAREA 0.741000 ;
    PORT
      LAYER Metal3 ;
        RECT 849.440 313.600 850.000 314.160 ;
    END
  END k0_in[0]
  PIN k0_in[10]
    DIRECTION INPUT ;
    USE SIGNAL ;
    ANTENNAGATEAREA 0.741000 ;
    PORT
      LAYER Metal3 ;
        RECT 849.440 376.320 850.000 376.880 ;
    END
  END k0_in[10]
  PIN k0_in[11]
    DIRECTION INPUT ;
    USE SIGNAL ;
    ANTENNAGATEAREA 0.741000 ;
    PORT
      LAYER Metal3 ;
        RECT 849.440 341.600 850.000 342.160 ;
    END
  END k0_in[11]
  PIN k0_in[12]
    DIRECTION INPUT ;
    USE SIGNAL ;
    ANTENNAGATEAREA 0.741000 ;
    PORT
      LAYER Metal3 ;
        RECT 849.440 300.160 850.000 300.720 ;
    END
  END k0_in[12]
  PIN k0_in[13]
    DIRECTION INPUT ;
    USE SIGNAL ;
    ANTENNAGATEAREA 0.741000 ;
    PORT
      LAYER Metal3 ;
        RECT 849.440 375.200 850.000 375.760 ;
    END
  END k0_in[13]
  PIN k0_in[14]
    DIRECTION INPUT ;
    USE SIGNAL ;
    ANTENNAGATEAREA 0.741000 ;
    PORT
      LAYER Metal3 ;
        RECT 849.440 449.120 850.000 449.680 ;
    END
  END k0_in[14]
  PIN k0_in[15]
    DIRECTION INPUT ;
    USE SIGNAL ;
    ANTENNAGATEAREA 0.741000 ;
    PORT
      LAYER Metal3 ;
        RECT 849.440 495.040 850.000 495.600 ;
    END
  END k0_in[15]
  PIN k0_in[16]
    DIRECTION INPUT ;
    USE SIGNAL ;
    ANTENNAGATEAREA 0.741000 ;
    PORT
      LAYER Metal3 ;
        RECT 849.440 371.840 850.000 372.400 ;
    END
  END k0_in[16]
  PIN k0_in[17]
    DIRECTION INPUT ;
    USE SIGNAL ;
    ANTENNAGATEAREA 0.741000 ;
    PORT
      LAYER Metal2 ;
        RECT 395.360 0.000 395.920 0.560 ;
    END
  END k0_in[17]
  PIN k0_in[18]
    DIRECTION INPUT ;
    USE SIGNAL ;
    ANTENNAGATEAREA 0.741000 ;
    PORT
      LAYER Metal2 ;
        RECT 476.000 0.000 476.560 0.560 ;
    END
  END k0_in[18]
  PIN k0_in[19]
    DIRECTION INPUT ;
    USE SIGNAL ;
    ANTENNAGATEAREA 0.741000 ;
    PORT
      LAYER Metal2 ;
        RECT 424.480 0.000 425.040 0.560 ;
    END
  END k0_in[19]
  PIN k0_in[1]
    DIRECTION INPUT ;
    USE SIGNAL ;
    ANTENNAGATEAREA 0.741000 ;
    PORT
      LAYER Metal2 ;
        RECT 560.000 0.000 560.560 0.560 ;
    END
  END k0_in[1]
  PIN k0_in[20]
    DIRECTION INPUT ;
    USE SIGNAL ;
    ANTENNAGATEAREA 0.741000 ;
    PORT
      LAYER Metal2 ;
        RECT 477.120 0.000 477.680 0.560 ;
    END
  END k0_in[20]
  PIN k0_in[21]
    DIRECTION INPUT ;
    USE SIGNAL ;
    ANTENNAGATEAREA 0.741000 ;
    PORT
      LAYER Metal2 ;
        RECT 456.960 0.000 457.520 0.560 ;
    END
  END k0_in[21]
  PIN k0_in[22]
    DIRECTION INPUT ;
    USE SIGNAL ;
    ANTENNAGATEAREA 0.741000 ;
    PORT
      LAYER Metal2 ;
        RECT 332.640 0.000 333.200 0.560 ;
    END
  END k0_in[22]
  PIN k0_in[23]
    DIRECTION INPUT ;
    USE SIGNAL ;
    ANTENNAGATEAREA 0.741000 ;
    PORT
      LAYER Metal2 ;
        RECT 357.280 0.000 357.840 0.560 ;
    END
  END k0_in[23]
  PIN k0_in[24]
    DIRECTION INPUT ;
    USE SIGNAL ;
    ANTENNAGATEAREA 0.741000 ;
    PORT
      LAYER Metal2 ;
        RECT 339.360 0.000 339.920 0.560 ;
    END
  END k0_in[24]
  PIN k0_in[25]
    DIRECTION INPUT ;
    USE SIGNAL ;
    ANTENNAGATEAREA 0.741000 ;
    PORT
      LAYER Metal2 ;
        RECT 262.080 0.000 262.640 0.560 ;
    END
  END k0_in[25]
  PIN k0_in[26]
    DIRECTION INPUT ;
    USE SIGNAL ;
    ANTENNAGATEAREA 0.741000 ;
    PORT
      LAYER Metal3 ;
        RECT 0.000 322.560 0.560 323.120 ;
    END
  END k0_in[26]
  PIN k0_in[27]
    DIRECTION INPUT ;
    USE SIGNAL ;
    ANTENNAGATEAREA 0.741000 ;
    PORT
      LAYER Metal3 ;
        RECT 0.000 283.360 0.560 283.920 ;
    END
  END k0_in[27]
  PIN k0_in[28]
    DIRECTION INPUT ;
    USE SIGNAL ;
    ANTENNAGATEAREA 0.741000 ;
    PORT
      LAYER Metal3 ;
        RECT 0.000 278.880 0.560 279.440 ;
    END
  END k0_in[28]
  PIN k0_in[29]
    DIRECTION INPUT ;
    USE SIGNAL ;
    ANTENNAGATEAREA 0.741000 ;
    PORT
      LAYER Metal3 ;
        RECT 0.000 210.560 0.560 211.120 ;
    END
  END k0_in[29]
  PIN k0_in[2]
    DIRECTION INPUT ;
    USE SIGNAL ;
    ANTENNAGATEAREA 0.741000 ;
    PORT
      LAYER Metal2 ;
        RECT 561.120 0.000 561.680 0.560 ;
    END
  END k0_in[2]
  PIN k0_in[30]
    DIRECTION INPUT ;
    USE SIGNAL ;
    ANTENNAGATEAREA 0.741000 ;
    PORT
      LAYER Metal3 ;
        RECT 0.000 245.280 0.560 245.840 ;
    END
  END k0_in[30]
  PIN k0_in[31]
    DIRECTION INPUT ;
    USE SIGNAL ;
    ANTENNAGATEAREA 0.741000 ;
    PORT
      LAYER Metal2 ;
        RECT 334.880 0.000 335.440 0.560 ;
    END
  END k0_in[31]
  PIN k0_in[32]
    DIRECTION INPUT ;
    USE SIGNAL ;
    ANTENNAGATEAREA 0.741000 ;
    PORT
      LAYER Metal3 ;
        RECT 0.000 455.840 0.560 456.400 ;
    END
  END k0_in[32]
  PIN k0_in[33]
    DIRECTION INPUT ;
    USE SIGNAL ;
    ANTENNAGATEAREA 0.741000 ;
    PORT
      LAYER Metal3 ;
        RECT 0.000 407.680 0.560 408.240 ;
    END
  END k0_in[33]
  PIN k0_in[34]
    DIRECTION INPUT ;
    USE SIGNAL ;
    ANTENNAGATEAREA 0.741000 ;
    PORT
      LAYER Metal3 ;
        RECT 0.000 425.600 0.560 426.160 ;
    END
  END k0_in[34]
  PIN k0_in[35]
    DIRECTION INPUT ;
    USE SIGNAL ;
    ANTENNAGATEAREA 0.741000 ;
    PORT
      LAYER Metal3 ;
        RECT 0.000 343.840 0.560 344.400 ;
    END
  END k0_in[35]
  PIN k0_in[36]
    DIRECTION INPUT ;
    USE SIGNAL ;
    ANTENNAGATEAREA 0.741000 ;
    PORT
      LAYER Metal3 ;
        RECT 0.000 369.600 0.560 370.160 ;
    END
  END k0_in[36]
  PIN k0_in[37]
    DIRECTION INPUT ;
    USE SIGNAL ;
    ANTENNAGATEAREA 0.741000 ;
    PORT
      LAYER Metal3 ;
        RECT 0.000 472.640 0.560 473.200 ;
    END
  END k0_in[37]
  PIN k0_in[38]
    DIRECTION INPUT ;
    USE SIGNAL ;
    ANTENNAGATEAREA 0.741000 ;
    PORT
      LAYER Metal3 ;
        RECT 0.000 477.120 0.560 477.680 ;
    END
  END k0_in[38]
  PIN k0_in[39]
    DIRECTION INPUT ;
    USE SIGNAL ;
    ANTENNAGATEAREA 0.741000 ;
    PORT
      LAYER Metal3 ;
        RECT 0.000 471.520 0.560 472.080 ;
    END
  END k0_in[39]
  PIN k0_in[3]
    DIRECTION INPUT ;
    USE SIGNAL ;
    ANTENNAGATEAREA 0.741000 ;
    PORT
      LAYER Metal3 ;
        RECT 849.440 243.040 850.000 243.600 ;
    END
  END k0_in[3]
  PIN k0_in[40]
    DIRECTION INPUT ;
    USE SIGNAL ;
    ANTENNAGATEAREA 0.741000 ;
    PORT
      LAYER Metal3 ;
        RECT 0.000 542.080 0.560 542.640 ;
    END
  END k0_in[40]
  PIN k0_in[41]
    DIRECTION INPUT ;
    USE SIGNAL ;
    ANTENNAGATEAREA 0.741000 ;
    PORT
      LAYER Metal3 ;
        RECT 0.000 533.120 0.560 533.680 ;
    END
  END k0_in[41]
  PIN k0_in[42]
    DIRECTION INPUT ;
    USE SIGNAL ;
    ANTENNAGATEAREA 0.741000 ;
    PORT
      LAYER Metal3 ;
        RECT 0.000 539.840 0.560 540.400 ;
    END
  END k0_in[42]
  PIN k0_in[43]
    DIRECTION INPUT ;
    USE SIGNAL ;
    ANTENNAGATEAREA 0.741000 ;
    PORT
      LAYER Metal2 ;
        RECT 358.400 849.440 358.960 850.000 ;
    END
  END k0_in[43]
  PIN k0_in[44]
    DIRECTION INPUT ;
    USE SIGNAL ;
    ANTENNAGATEAREA 0.741000 ;
    PORT
      LAYER Metal3 ;
        RECT 0.000 660.800 0.560 661.360 ;
    END
  END k0_in[44]
  PIN k0_in[45]
    DIRECTION INPUT ;
    USE SIGNAL ;
    ANTENNAGATEAREA 0.741000 ;
    PORT
      LAYER Metal3 ;
        RECT 0.000 610.400 0.560 610.960 ;
    END
  END k0_in[45]
  PIN k0_in[46]
    DIRECTION INPUT ;
    USE SIGNAL ;
    ANTENNAGATEAREA 0.741000 ;
    PORT
      LAYER Metal2 ;
        RECT 269.920 849.440 270.480 850.000 ;
    END
  END k0_in[46]
  PIN k0_in[47]
    DIRECTION INPUT ;
    USE SIGNAL ;
    ANTENNAGATEAREA 0.741000 ;
    PORT
      LAYER Metal3 ;
        RECT 0.000 576.800 0.560 577.360 ;
    END
  END k0_in[47]
  PIN k0_in[48]
    DIRECTION INPUT ;
    USE SIGNAL ;
    ANTENNAGATEAREA 0.741000 ;
    PORT
      LAYER Metal2 ;
        RECT 422.240 849.440 422.800 850.000 ;
    END
  END k0_in[48]
  PIN k0_in[49]
    DIRECTION INPUT ;
    USE SIGNAL ;
    ANTENNAGATEAREA 0.741000 ;
    PORT
      LAYER Metal2 ;
        RECT 305.760 849.440 306.320 850.000 ;
    END
  END k0_in[49]
  PIN k0_in[4]
    DIRECTION INPUT ;
    USE SIGNAL ;
    ANTENNAGATEAREA 0.741000 ;
    PORT
      LAYER Metal3 ;
        RECT 849.440 301.280 850.000 301.840 ;
    END
  END k0_in[4]
  PIN k0_in[50]
    DIRECTION INPUT ;
    USE SIGNAL ;
    ANTENNAGATEAREA 0.741000 ;
    PORT
      LAYER Metal2 ;
        RECT 356.160 849.440 356.720 850.000 ;
    END
  END k0_in[50]
  PIN k0_in[51]
    DIRECTION INPUT ;
    USE SIGNAL ;
    ANTENNAGATEAREA 0.741000 ;
    PORT
      LAYER Metal2 ;
        RECT 258.720 849.440 259.280 850.000 ;
    END
  END k0_in[51]
  PIN k0_in[52]
    DIRECTION INPUT ;
    USE SIGNAL ;
    ANTENNAGATEAREA 0.741000 ;
    PORT
      LAYER Metal2 ;
        RECT 316.960 849.440 317.520 850.000 ;
    END
  END k0_in[52]
  PIN k0_in[53]
    DIRECTION INPUT ;
    USE SIGNAL ;
    ANTENNAGATEAREA 0.741000 ;
    PORT
      LAYER Metal2 ;
        RECT 433.440 849.440 434.000 850.000 ;
    END
  END k0_in[53]
  PIN k0_in[54]
    DIRECTION INPUT ;
    USE SIGNAL ;
    ANTENNAGATEAREA 0.741000 ;
    PORT
      LAYER Metal2 ;
        RECT 487.200 849.440 487.760 850.000 ;
    END
  END k0_in[54]
  PIN k0_in[55]
    DIRECTION INPUT ;
    USE SIGNAL ;
    ANTENNAGATEAREA 0.741000 ;
    PORT
      LAYER Metal2 ;
        RECT 463.680 849.440 464.240 850.000 ;
    END
  END k0_in[55]
  PIN k0_in[56]
    DIRECTION INPUT ;
    USE SIGNAL ;
    ANTENNAGATEAREA 0.741000 ;
    PORT
      LAYER Metal2 ;
        RECT 481.600 849.440 482.160 850.000 ;
    END
  END k0_in[56]
  PIN k0_in[57]
    DIRECTION INPUT ;
    USE SIGNAL ;
    ANTENNAGATEAREA 0.741000 ;
    PORT
      LAYER Metal2 ;
        RECT 517.440 849.440 518.000 850.000 ;
    END
  END k0_in[57]
  PIN k0_in[58]
    DIRECTION INPUT ;
    USE SIGNAL ;
    ANTENNAGATEAREA 0.741000 ;
    PORT
      LAYER Metal3 ;
        RECT 849.440 526.400 850.000 526.960 ;
    END
  END k0_in[58]
  PIN k0_in[59]
    DIRECTION INPUT ;
    USE SIGNAL ;
    ANTENNAGATEAREA 0.741000 ;
    PORT
      LAYER Metal2 ;
        RECT 585.760 849.440 586.320 850.000 ;
    END
  END k0_in[59]
  PIN k0_in[5]
    DIRECTION INPUT ;
    USE SIGNAL ;
    ANTENNAGATEAREA 0.741000 ;
    PORT
      LAYER Metal2 ;
        RECT 562.240 0.000 562.800 0.560 ;
    END
  END k0_in[5]
  PIN k0_in[60]
    DIRECTION INPUT ;
    USE SIGNAL ;
    ANTENNAGATEAREA 0.741000 ;
    PORT
      LAYER Metal3 ;
        RECT 849.440 631.680 850.000 632.240 ;
    END
  END k0_in[60]
  PIN k0_in[61]
    DIRECTION INPUT ;
    USE SIGNAL ;
    ANTENNAGATEAREA 0.741000 ;
    PORT
      LAYER Metal3 ;
        RECT 849.440 568.960 850.000 569.520 ;
    END
  END k0_in[61]
  PIN k0_in[62]
    DIRECTION INPUT ;
    USE SIGNAL ;
    ANTENNAGATEAREA 0.741000 ;
    PORT
      LAYER Metal3 ;
        RECT 849.440 575.680 850.000 576.240 ;
    END
  END k0_in[62]
  PIN k0_in[63]
    DIRECTION INPUT ;
    USE SIGNAL ;
    ANTENNAGATEAREA 0.741000 ;
    PORT
      LAYER Metal3 ;
        RECT 849.440 516.320 850.000 516.880 ;
    END
  END k0_in[63]
  PIN k0_in[6]
    DIRECTION INPUT ;
    USE SIGNAL ;
    ANTENNAGATEAREA 0.741000 ;
    PORT
      LAYER Metal2 ;
        RECT 640.640 0.000 641.200 0.560 ;
    END
  END k0_in[6]
  PIN k0_in[7]
    DIRECTION INPUT ;
    USE SIGNAL ;
    ANTENNAGATEAREA 0.741000 ;
    PORT
      LAYER Metal2 ;
        RECT 641.760 0.000 642.320 0.560 ;
    END
  END k0_in[7]
  PIN k0_in[8]
    DIRECTION INPUT ;
    USE SIGNAL ;
    ANTENNAGATEAREA 0.741000 ;
    PORT
      LAYER Metal3 ;
        RECT 849.440 380.800 850.000 381.360 ;
    END
  END k0_in[8]
  PIN k0_in[9]
    DIRECTION INPUT ;
    USE SIGNAL ;
    ANTENNAGATEAREA 0.741000 ;
    PORT
      LAYER Metal3 ;
        RECT 849.440 450.240 850.000 450.800 ;
    END
  END k0_in[9]
  PIN k1_in[0]
    DIRECTION INPUT ;
    USE SIGNAL ;
    ANTENNAGATEAREA 0.741000 ;
    PORT
      LAYER Metal3 ;
        RECT 849.440 311.360 850.000 311.920 ;
    END
  END k1_in[0]
  PIN k1_in[10]
    DIRECTION INPUT ;
    USE SIGNAL ;
    ANTENNAGATEAREA 0.741000 ;
    PORT
      LAYER Metal3 ;
        RECT 849.440 368.480 850.000 369.040 ;
    END
  END k1_in[10]
  PIN k1_in[11]
    DIRECTION INPUT ;
    USE SIGNAL ;
    ANTENNAGATEAREA 0.741000 ;
    PORT
      LAYER Metal3 ;
        RECT 849.440 338.240 850.000 338.800 ;
    END
  END k1_in[11]
  PIN k1_in[12]
    DIRECTION INPUT ;
    USE SIGNAL ;
    ANTENNAGATEAREA 0.741000 ;
    PORT
      LAYER Metal3 ;
        RECT 849.440 297.920 850.000 298.480 ;
    END
  END k1_in[12]
  PIN k1_in[13]
    DIRECTION INPUT ;
    USE SIGNAL ;
    ANTENNAGATEAREA 0.741000 ;
    PORT
      LAYER Metal3 ;
        RECT 849.440 377.440 850.000 378.000 ;
    END
  END k1_in[13]
  PIN k1_in[14]
    DIRECTION INPUT ;
    USE SIGNAL ;
    ANTENNAGATEAREA 0.741000 ;
    PORT
      LAYER Metal3 ;
        RECT 849.440 435.680 850.000 436.240 ;
    END
  END k1_in[14]
  PIN k1_in[15]
    DIRECTION INPUT ;
    USE SIGNAL ;
    ANTENNAGATEAREA 0.741000 ;
    PORT
      LAYER Metal3 ;
        RECT 849.440 505.120 850.000 505.680 ;
    END
  END k1_in[15]
  PIN k1_in[16]
    DIRECTION INPUT ;
    USE SIGNAL ;
    ANTENNAGATEAREA 0.741000 ;
    PORT
      LAYER Metal3 ;
        RECT 849.440 362.880 850.000 363.440 ;
    END
  END k1_in[16]
  PIN k1_in[17]
    DIRECTION INPUT ;
    USE SIGNAL ;
    ANTENNAGATEAREA 0.741000 ;
    PORT
      LAYER Metal2 ;
        RECT 380.800 0.000 381.360 0.560 ;
    END
  END k1_in[17]
  PIN k1_in[18]
    DIRECTION INPUT ;
    USE SIGNAL ;
    ANTENNAGATEAREA 0.741000 ;
    PORT
      LAYER Metal2 ;
        RECT 460.320 0.000 460.880 0.560 ;
    END
  END k1_in[18]
  PIN k1_in[19]
    DIRECTION INPUT ;
    USE SIGNAL ;
    ANTENNAGATEAREA 0.741000 ;
    PORT
      LAYER Metal2 ;
        RECT 416.640 0.000 417.200 0.560 ;
    END
  END k1_in[19]
  PIN k1_in[1]
    DIRECTION INPUT ;
    USE SIGNAL ;
    ANTENNAGATEAREA 0.741000 ;
    PORT
      LAYER Metal2 ;
        RECT 545.440 0.000 546.000 0.560 ;
    END
  END k1_in[1]
  PIN k1_in[20]
    DIRECTION INPUT ;
    USE SIGNAL ;
    ANTENNAGATEAREA 0.741000 ;
    PORT
      LAYER Metal2 ;
        RECT 470.400 0.000 470.960 0.560 ;
    END
  END k1_in[20]
  PIN k1_in[21]
    DIRECTION INPUT ;
    USE SIGNAL ;
    ANTENNAGATEAREA 0.741000 ;
    PORT
      LAYER Metal2 ;
        RECT 451.360 0.000 451.920 0.560 ;
    END
  END k1_in[21]
  PIN k1_in[22]
    DIRECTION INPUT ;
    USE SIGNAL ;
    ANTENNAGATEAREA 0.741000 ;
    PORT
      LAYER Metal2 ;
        RECT 331.520 0.000 332.080 0.560 ;
    END
  END k1_in[22]
  PIN k1_in[23]
    DIRECTION INPUT ;
    USE SIGNAL ;
    ANTENNAGATEAREA 0.741000 ;
    PORT
      LAYER Metal2 ;
        RECT 353.920 0.000 354.480 0.560 ;
    END
  END k1_in[23]
  PIN k1_in[24]
    DIRECTION INPUT ;
    USE SIGNAL ;
    ANTENNAGATEAREA 0.741000 ;
    PORT
      LAYER Metal2 ;
        RECT 333.760 0.000 334.320 0.560 ;
    END
  END k1_in[24]
  PIN k1_in[25]
    DIRECTION INPUT ;
    USE SIGNAL ;
    ANTENNAGATEAREA 0.741000 ;
    PORT
      LAYER Metal2 ;
        RECT 284.480 0.000 285.040 0.560 ;
    END
  END k1_in[25]
  PIN k1_in[26]
    DIRECTION INPUT ;
    USE SIGNAL ;
    ANTENNAGATEAREA 0.741000 ;
    PORT
      LAYER Metal3 ;
        RECT 0.000 334.880 0.560 335.440 ;
    END
  END k1_in[26]
  PIN k1_in[27]
    DIRECTION INPUT ;
    USE SIGNAL ;
    ANTENNAGATEAREA 0.741000 ;
    PORT
      LAYER Metal3 ;
        RECT 0.000 321.440 0.560 322.000 ;
    END
  END k1_in[27]
  PIN k1_in[28]
    DIRECTION INPUT ;
    USE SIGNAL ;
    ANTENNAGATEAREA 0.741000 ;
    PORT
      LAYER Metal3 ;
        RECT 0.000 277.760 0.560 278.320 ;
    END
  END k1_in[28]
  PIN k1_in[29]
    DIRECTION INPUT ;
    USE SIGNAL ;
    ANTENNAGATEAREA 0.741000 ;
    PORT
      LAYER Metal3 ;
        RECT 0.000 225.120 0.560 225.680 ;
    END
  END k1_in[29]
  PIN k1_in[2]
    DIRECTION INPUT ;
    USE SIGNAL ;
    ANTENNAGATEAREA 0.741000 ;
    PORT
      LAYER Metal2 ;
        RECT 537.600 0.000 538.160 0.560 ;
    END
  END k1_in[2]
  PIN k1_in[30]
    DIRECTION INPUT ;
    USE SIGNAL ;
    ANTENNAGATEAREA 0.741000 ;
    PORT
      LAYER Metal2 ;
        RECT 266.560 0.000 267.120 0.560 ;
    END
  END k1_in[30]
  PIN k1_in[31]
    DIRECTION INPUT ;
    USE SIGNAL ;
    ANTENNAGATEAREA 0.741000 ;
    PORT
      LAYER Metal2 ;
        RECT 337.120 0.000 337.680 0.560 ;
    END
  END k1_in[31]
  PIN k1_in[32]
    DIRECTION INPUT ;
    USE SIGNAL ;
    ANTENNAGATEAREA 0.741000 ;
    PORT
      LAYER Metal3 ;
        RECT 0.000 454.720 0.560 455.280 ;
    END
  END k1_in[32]
  PIN k1_in[33]
    DIRECTION INPUT ;
    USE SIGNAL ;
    ANTENNAGATEAREA 0.741000 ;
    PORT
      LAYER Metal3 ;
        RECT 0.000 392.000 0.560 392.560 ;
    END
  END k1_in[33]
  PIN k1_in[34]
    DIRECTION INPUT ;
    USE SIGNAL ;
    ANTENNAGATEAREA 0.741000 ;
    PORT
      LAYER Metal3 ;
        RECT 0.000 420.000 0.560 420.560 ;
    END
  END k1_in[34]
  PIN k1_in[35]
    DIRECTION INPUT ;
    USE SIGNAL ;
    ANTENNAGATEAREA 0.741000 ;
    PORT
      LAYER Metal3 ;
        RECT 0.000 329.280 0.560 329.840 ;
    END
  END k1_in[35]
  PIN k1_in[36]
    DIRECTION INPUT ;
    USE SIGNAL ;
    ANTENNAGATEAREA 0.741000 ;
    PORT
      LAYER Metal3 ;
        RECT 0.000 372.960 0.560 373.520 ;
    END
  END k1_in[36]
  PIN k1_in[37]
    DIRECTION INPUT ;
    USE SIGNAL ;
    ANTENNAGATEAREA 0.741000 ;
    PORT
      LAYER Metal3 ;
        RECT 0.000 478.240 0.560 478.800 ;
    END
  END k1_in[37]
  PIN k1_in[38]
    DIRECTION INPUT ;
    USE SIGNAL ;
    ANTENNAGATEAREA 0.741000 ;
    PORT
      LAYER Metal3 ;
        RECT 0.000 473.760 0.560 474.320 ;
    END
  END k1_in[38]
  PIN k1_in[39]
    DIRECTION INPUT ;
    USE SIGNAL ;
    ANTENNAGATEAREA 0.741000 ;
    PORT
      LAYER Metal3 ;
        RECT 0.000 479.360 0.560 479.920 ;
    END
  END k1_in[39]
  PIN k1_in[3]
    DIRECTION INPUT ;
    USE SIGNAL ;
    ANTENNAGATEAREA 0.741000 ;
    PORT
      LAYER Metal3 ;
        RECT 849.440 250.880 850.000 251.440 ;
    END
  END k1_in[3]
  PIN k1_in[40]
    DIRECTION INPUT ;
    USE SIGNAL ;
    ANTENNAGATEAREA 0.741000 ;
    PORT
      LAYER Metal2 ;
        RECT 336.000 849.440 336.560 850.000 ;
    END
  END k1_in[40]
  PIN k1_in[41]
    DIRECTION INPUT ;
    USE SIGNAL ;
    ANTENNAGATEAREA 0.741000 ;
    PORT
      LAYER Metal3 ;
        RECT 0.000 532.000 0.560 532.560 ;
    END
  END k1_in[41]
  PIN k1_in[42]
    DIRECTION INPUT ;
    USE SIGNAL ;
    ANTENNAGATEAREA 0.741000 ;
    PORT
      LAYER Metal3 ;
        RECT 0.000 540.960 0.560 541.520 ;
    END
  END k1_in[42]
  PIN k1_in[43]
    DIRECTION INPUT ;
    USE SIGNAL ;
    ANTENNAGATEAREA 0.741000 ;
    PORT
      LAYER Metal2 ;
        RECT 386.400 849.440 386.960 850.000 ;
    END
  END k1_in[43]
  PIN k1_in[44]
    DIRECTION INPUT ;
    USE SIGNAL ;
    ANTENNAGATEAREA 0.741000 ;
    PORT
      LAYER Metal3 ;
        RECT 0.000 659.680 0.560 660.240 ;
    END
  END k1_in[44]
  PIN k1_in[45]
    DIRECTION INPUT ;
    USE SIGNAL ;
    ANTENNAGATEAREA 0.741000 ;
    PORT
      LAYER Metal3 ;
        RECT 0.000 611.520 0.560 612.080 ;
    END
  END k1_in[45]
  PIN k1_in[46]
    DIRECTION INPUT ;
    USE SIGNAL ;
    ANTENNAGATEAREA 0.741000 ;
    PORT
      LAYER Metal2 ;
        RECT 282.240 849.440 282.800 850.000 ;
    END
  END k1_in[46]
  PIN k1_in[47]
    DIRECTION INPUT ;
    USE SIGNAL ;
    ANTENNAGATEAREA 0.741000 ;
    PORT
      LAYER Metal3 ;
        RECT 0.000 579.040 0.560 579.600 ;
    END
  END k1_in[47]
  PIN k1_in[48]
    DIRECTION INPUT ;
    USE SIGNAL ;
    ANTENNAGATEAREA 0.741000 ;
    PORT
      LAYER Metal2 ;
        RECT 428.960 849.440 429.520 850.000 ;
    END
  END k1_in[48]
  PIN k1_in[49]
    DIRECTION INPUT ;
    USE SIGNAL ;
    ANTENNAGATEAREA 0.741000 ;
    PORT
      LAYER Metal2 ;
        RECT 306.880 849.440 307.440 850.000 ;
    END
  END k1_in[49]
  PIN k1_in[4]
    DIRECTION INPUT ;
    USE SIGNAL ;
    ANTENNAGATEAREA 0.741000 ;
    PORT
      LAYER Metal3 ;
        RECT 849.440 316.960 850.000 317.520 ;
    END
  END k1_in[4]
  PIN k1_in[50]
    DIRECTION INPUT ;
    USE SIGNAL ;
    ANTENNAGATEAREA 0.741000 ;
    PORT
      LAYER Metal2 ;
        RECT 374.080 849.440 374.640 850.000 ;
    END
  END k1_in[50]
  PIN k1_in[51]
    DIRECTION INPUT ;
    USE SIGNAL ;
    ANTENNAGATEAREA 0.741000 ;
    PORT
      LAYER Metal2 ;
        RECT 256.480 849.440 257.040 850.000 ;
    END
  END k1_in[51]
  PIN k1_in[52]
    DIRECTION INPUT ;
    USE SIGNAL ;
    ANTENNAGATEAREA 0.741000 ;
    PORT
      LAYER Metal2 ;
        RECT 325.920 849.440 326.480 850.000 ;
    END
  END k1_in[52]
  PIN k1_in[53]
    DIRECTION INPUT ;
    USE SIGNAL ;
    ANTENNAGATEAREA 0.741000 ;
    PORT
      LAYER Metal2 ;
        RECT 435.680 849.440 436.240 850.000 ;
    END
  END k1_in[53]
  PIN k1_in[54]
    DIRECTION INPUT ;
    USE SIGNAL ;
    ANTENNAGATEAREA 0.741000 ;
    PORT
      LAYER Metal2 ;
        RECT 491.680 849.440 492.240 850.000 ;
    END
  END k1_in[54]
  PIN k1_in[55]
    DIRECTION INPUT ;
    USE SIGNAL ;
    ANTENNAGATEAREA 0.741000 ;
    PORT
      LAYER Metal2 ;
        RECT 473.760 849.440 474.320 850.000 ;
    END
  END k1_in[55]
  PIN k1_in[56]
    DIRECTION INPUT ;
    USE SIGNAL ;
    ANTENNAGATEAREA 0.741000 ;
    PORT
      LAYER Metal2 ;
        RECT 484.960 849.440 485.520 850.000 ;
    END
  END k1_in[56]
  PIN k1_in[57]
    DIRECTION INPUT ;
    USE SIGNAL ;
    ANTENNAGATEAREA 0.741000 ;
    PORT
      LAYER Metal2 ;
        RECT 515.200 849.440 515.760 850.000 ;
    END
  END k1_in[57]
  PIN k1_in[58]
    DIRECTION INPUT ;
    USE SIGNAL ;
    ANTENNAGATEAREA 0.741000 ;
    PORT
      LAYER Metal2 ;
        RECT 542.080 849.440 542.640 850.000 ;
    END
  END k1_in[58]
  PIN k1_in[59]
    DIRECTION INPUT ;
    USE SIGNAL ;
    ANTENNAGATEAREA 0.741000 ;
    PORT
      LAYER Metal2 ;
        RECT 564.480 849.440 565.040 850.000 ;
    END
  END k1_in[59]
  PIN k1_in[5]
    DIRECTION INPUT ;
    USE SIGNAL ;
    ANTENNAGATEAREA 0.741000 ;
    PORT
      LAYER Metal2 ;
        RECT 563.360 0.000 563.920 0.560 ;
    END
  END k1_in[5]
  PIN k1_in[60]
    DIRECTION INPUT ;
    USE SIGNAL ;
    ANTENNAGATEAREA 0.741000 ;
    PORT
      LAYER Metal3 ;
        RECT 849.440 628.320 850.000 628.880 ;
    END
  END k1_in[60]
  PIN k1_in[61]
    DIRECTION INPUT ;
    USE SIGNAL ;
    ANTENNAGATEAREA 0.741000 ;
    PORT
      LAYER Metal3 ;
        RECT 849.440 557.760 850.000 558.320 ;
    END
  END k1_in[61]
  PIN k1_in[62]
    DIRECTION INPUT ;
    USE SIGNAL ;
    ANTENNAGATEAREA 0.741000 ;
    PORT
      LAYER Metal3 ;
        RECT 849.440 566.720 850.000 567.280 ;
    END
  END k1_in[62]
  PIN k1_in[63]
    DIRECTION INPUT ;
    USE SIGNAL ;
    ANTENNAGATEAREA 0.741000 ;
    PORT
      LAYER Metal3 ;
        RECT 849.440 511.840 850.000 512.400 ;
    END
  END k1_in[63]
  PIN k1_in[6]
    DIRECTION INPUT ;
    USE SIGNAL ;
    ANTENNAGATEAREA 0.741000 ;
    PORT
      LAYER Metal2 ;
        RECT 622.720 0.000 623.280 0.560 ;
    END
  END k1_in[6]
  PIN k1_in[7]
    DIRECTION INPUT ;
    USE SIGNAL ;
    ANTENNAGATEAREA 0.741000 ;
    PORT
      LAYER Metal2 ;
        RECT 617.120 0.000 617.680 0.560 ;
    END
  END k1_in[7]
  PIN k1_in[8]
    DIRECTION INPUT ;
    USE SIGNAL ;
    ANTENNAGATEAREA 0.741000 ;
    PORT
      LAYER Metal3 ;
        RECT 849.440 378.560 850.000 379.120 ;
    END
  END k1_in[8]
  PIN k1_in[9]
    DIRECTION INPUT ;
    USE SIGNAL ;
    ANTENNAGATEAREA 0.741000 ;
    PORT
      LAYER Metal3 ;
        RECT 849.440 436.800 850.000 437.360 ;
    END
  END k1_in[9]
  PIN n0_in[0]
    DIRECTION INPUT ;
    USE SIGNAL ;
    ANTENNAGATEAREA 0.741000 ;
    PORT
      LAYER Metal3 ;
        RECT 849.440 312.480 850.000 313.040 ;
    END
  END n0_in[0]
  PIN n0_in[10]
    DIRECTION INPUT ;
    USE SIGNAL ;
    ANTENNAGATEAREA 0.741000 ;
    PORT
      LAYER Metal3 ;
        RECT 849.440 366.240 850.000 366.800 ;
    END
  END n0_in[10]
  PIN n0_in[11]
    DIRECTION INPUT ;
    USE SIGNAL ;
    ANTENNAGATEAREA 0.741000 ;
    PORT
      LAYER Metal3 ;
        RECT 849.440 328.160 850.000 328.720 ;
    END
  END n0_in[11]
  PIN n0_in[12]
    DIRECTION INPUT ;
    USE SIGNAL ;
    ANTENNAGATEAREA 0.741000 ;
    PORT
      LAYER Metal3 ;
        RECT 849.440 278.880 850.000 279.440 ;
    END
  END n0_in[12]
  PIN n0_in[13]
    DIRECTION INPUT ;
    USE SIGNAL ;
    ANTENNAGATEAREA 0.741000 ;
    PORT
      LAYER Metal3 ;
        RECT 849.440 276.640 850.000 277.200 ;
    END
  END n0_in[13]
  PIN n0_in[14]
    DIRECTION INPUT ;
    USE SIGNAL ;
    ANTENNAGATEAREA 0.741000 ;
    PORT
      LAYER Metal3 ;
        RECT 849.440 426.720 850.000 427.280 ;
    END
  END n0_in[14]
  PIN n0_in[15]
    DIRECTION INPUT ;
    USE SIGNAL ;
    ANTENNAGATEAREA 0.741000 ;
    PORT
      LAYER Metal3 ;
        RECT 849.440 504.000 850.000 504.560 ;
    END
  END n0_in[15]
  PIN n0_in[16]
    DIRECTION INPUT ;
    USE SIGNAL ;
    ANTENNAGATEAREA 0.741000 ;
    PORT
      LAYER Metal3 ;
        RECT 849.440 360.640 850.000 361.200 ;
    END
  END n0_in[16]
  PIN n0_in[17]
    DIRECTION INPUT ;
    USE SIGNAL ;
    ANTENNAGATEAREA 0.741000 ;
    PORT
      LAYER Metal2 ;
        RECT 390.880 0.000 391.440 0.560 ;
    END
  END n0_in[17]
  PIN n0_in[18]
    DIRECTION INPUT ;
    USE SIGNAL ;
    ANTENNAGATEAREA 0.741000 ;
    PORT
      LAYER Metal2 ;
        RECT 483.840 0.000 484.400 0.560 ;
    END
  END n0_in[18]
  PIN n0_in[19]
    DIRECTION INPUT ;
    USE SIGNAL ;
    ANTENNAGATEAREA 0.741000 ;
    PORT
      LAYER Metal2 ;
        RECT 417.760 0.000 418.320 0.560 ;
    END
  END n0_in[19]
  PIN n0_in[1]
    DIRECTION INPUT ;
    USE SIGNAL ;
    ANTENNAGATEAREA 0.741000 ;
    PORT
      LAYER Metal2 ;
        RECT 546.560 0.000 547.120 0.560 ;
    END
  END n0_in[1]
  PIN n0_in[20]
    DIRECTION INPUT ;
    USE SIGNAL ;
    ANTENNAGATEAREA 0.741000 ;
    PORT
      LAYER Metal2 ;
        RECT 484.960 0.000 485.520 0.560 ;
    END
  END n0_in[20]
  PIN n0_in[21]
    DIRECTION INPUT ;
    USE SIGNAL ;
    ANTENNAGATEAREA 0.741000 ;
    PORT
      LAYER Metal2 ;
        RECT 479.360 0.000 479.920 0.560 ;
    END
  END n0_in[21]
  PIN n0_in[22]
    DIRECTION INPUT ;
    USE SIGNAL ;
    ANTENNAGATEAREA 0.741000 ;
    PORT
      LAYER Metal2 ;
        RECT 321.440 0.000 322.000 0.560 ;
    END
  END n0_in[22]
  PIN n0_in[23]
    DIRECTION INPUT ;
    USE SIGNAL ;
    ANTENNAGATEAREA 0.741000 ;
    PORT
      LAYER Metal2 ;
        RECT 358.400 0.000 358.960 0.560 ;
    END
  END n0_in[23]
  PIN n0_in[24]
    DIRECTION INPUT ;
    USE SIGNAL ;
    ANTENNAGATEAREA 0.741000 ;
    PORT
      LAYER Metal2 ;
        RECT 319.200 0.000 319.760 0.560 ;
    END
  END n0_in[24]
  PIN n0_in[25]
    DIRECTION INPUT ;
    USE SIGNAL ;
    ANTENNAGATEAREA 0.741000 ;
    PORT
      LAYER Metal2 ;
        RECT 280.000 0.000 280.560 0.560 ;
    END
  END n0_in[25]
  PIN n0_in[26]
    DIRECTION INPUT ;
    USE SIGNAL ;
    ANTENNAGATEAREA 0.741000 ;
    PORT
      LAYER Metal3 ;
        RECT 0.000 336.000 0.560 336.560 ;
    END
  END n0_in[26]
  PIN n0_in[27]
    DIRECTION INPUT ;
    USE SIGNAL ;
    ANTENNAGATEAREA 0.741000 ;
    PORT
      LAYER Metal3 ;
        RECT 0.000 308.000 0.560 308.560 ;
    END
  END n0_in[27]
  PIN n0_in[28]
    DIRECTION INPUT ;
    USE SIGNAL ;
    ANTENNAGATEAREA 0.741000 ;
    PORT
      LAYER Metal3 ;
        RECT 0.000 286.720 0.560 287.280 ;
    END
  END n0_in[28]
  PIN n0_in[29]
    DIRECTION INPUT ;
    USE SIGNAL ;
    ANTENNAGATEAREA 0.741000 ;
    PORT
      LAYER Metal3 ;
        RECT 0.000 209.440 0.560 210.000 ;
    END
  END n0_in[29]
  PIN n0_in[2]
    DIRECTION INPUT ;
    USE SIGNAL ;
    ANTENNAGATEAREA 0.741000 ;
    PORT
      LAYER Metal2 ;
        RECT 555.520 0.000 556.080 0.560 ;
    END
  END n0_in[2]
  PIN n0_in[30]
    DIRECTION INPUT ;
    USE SIGNAL ;
    ANTENNAGATEAREA 0.741000 ;
    PORT
      LAYER Metal2 ;
        RECT 277.760 0.000 278.320 0.560 ;
    END
  END n0_in[30]
  PIN n0_in[31]
    DIRECTION INPUT ;
    USE SIGNAL ;
    ANTENNAGATEAREA 0.741000 ;
    PORT
      LAYER Metal2 ;
        RECT 328.160 0.000 328.720 0.560 ;
    END
  END n0_in[31]
  PIN n0_in[32]
    DIRECTION INPUT ;
    USE SIGNAL ;
    ANTENNAGATEAREA 0.741000 ;
    PORT
      LAYER Metal3 ;
        RECT 0.000 462.560 0.560 463.120 ;
    END
  END n0_in[32]
  PIN n0_in[33]
    DIRECTION INPUT ;
    USE SIGNAL ;
    ANTENNAGATEAREA 0.741000 ;
    PORT
      LAYER Metal3 ;
        RECT 0.000 379.680 0.560 380.240 ;
    END
  END n0_in[33]
  PIN n0_in[34]
    DIRECTION INPUT ;
    USE SIGNAL ;
    ANTENNAGATEAREA 0.741000 ;
    PORT
      LAYER Metal3 ;
        RECT 0.000 416.640 0.560 417.200 ;
    END
  END n0_in[34]
  PIN n0_in[35]
    DIRECTION INPUT ;
    USE SIGNAL ;
    ANTENNAGATEAREA 0.741000 ;
    PORT
      LAYER Metal3 ;
        RECT 0.000 311.360 0.560 311.920 ;
    END
  END n0_in[35]
  PIN n0_in[36]
    DIRECTION INPUT ;
    USE SIGNAL ;
    ANTENNAGATEAREA 0.741000 ;
    PORT
      LAYER Metal3 ;
        RECT 0.000 361.760 0.560 362.320 ;
    END
  END n0_in[36]
  PIN n0_in[37]
    DIRECTION INPUT ;
    USE SIGNAL ;
    ANTENNAGATEAREA 0.741000 ;
    PORT
      LAYER Metal3 ;
        RECT 0.000 488.320 0.560 488.880 ;
    END
  END n0_in[37]
  PIN n0_in[38]
    DIRECTION INPUT ;
    USE SIGNAL ;
    ANTENNAGATEAREA 0.741000 ;
    PORT
      LAYER Metal3 ;
        RECT 0.000 474.880 0.560 475.440 ;
    END
  END n0_in[38]
  PIN n0_in[39]
    DIRECTION INPUT ;
    USE SIGNAL ;
    ANTENNAGATEAREA 0.741000 ;
    PORT
      LAYER Metal3 ;
        RECT 0.000 464.800 0.560 465.360 ;
    END
  END n0_in[39]
  PIN n0_in[3]
    DIRECTION INPUT ;
    USE SIGNAL ;
    ANTENNAGATEAREA 0.741000 ;
    PORT
      LAYER Metal3 ;
        RECT 849.440 245.280 850.000 245.840 ;
    END
  END n0_in[3]
  PIN n0_in[40]
    DIRECTION INPUT ;
    USE SIGNAL ;
    ANTENNAGATEAREA 0.741000 ;
    PORT
      LAYER Metal2 ;
        RECT 318.080 849.440 318.640 850.000 ;
    END
  END n0_in[40]
  PIN n0_in[41]
    DIRECTION INPUT ;
    USE SIGNAL ;
    ANTENNAGATEAREA 0.741000 ;
    PORT
      LAYER Metal3 ;
        RECT 0.000 530.880 0.560 531.440 ;
    END
  END n0_in[41]
  PIN n0_in[42]
    DIRECTION INPUT ;
    USE SIGNAL ;
    ANTENNAGATEAREA 0.741000 ;
    PORT
      LAYER Metal3 ;
        RECT 0.000 547.680 0.560 548.240 ;
    END
  END n0_in[42]
  PIN n0_in[43]
    DIRECTION INPUT ;
    USE SIGNAL ;
    ANTENNAGATEAREA 0.741000 ;
    PORT
      LAYER Metal2 ;
        RECT 339.360 849.440 339.920 850.000 ;
    END
  END n0_in[43]
  PIN n0_in[44]
    DIRECTION INPUT ;
    USE SIGNAL ;
    ANTENNAGATEAREA 0.741000 ;
    PORT
      LAYER Metal3 ;
        RECT 0.000 665.280 0.560 665.840 ;
    END
  END n0_in[44]
  PIN n0_in[45]
    DIRECTION INPUT ;
    USE SIGNAL ;
    ANTENNAGATEAREA 0.741000 ;
    PORT
      LAYER Metal3 ;
        RECT 0.000 600.320 0.560 600.880 ;
    END
  END n0_in[45]
  PIN n0_in[46]
    DIRECTION INPUT ;
    USE SIGNAL ;
    ANTENNAGATEAREA 0.741000 ;
    PORT
      LAYER Metal2 ;
        RECT 268.800 849.440 269.360 850.000 ;
    END
  END n0_in[46]
  PIN n0_in[47]
    DIRECTION INPUT ;
    USE SIGNAL ;
    ANTENNAGATEAREA 0.741000 ;
    PORT
      LAYER Metal3 ;
        RECT 0.000 561.120 0.560 561.680 ;
    END
  END n0_in[47]
  PIN n0_in[48]
    DIRECTION INPUT ;
    USE SIGNAL ;
    ANTENNAGATEAREA 0.741000 ;
    PORT
      LAYER Metal2 ;
        RECT 442.400 849.440 442.960 850.000 ;
    END
  END n0_in[48]
  PIN n0_in[49]
    DIRECTION INPUT ;
    USE SIGNAL ;
    ANTENNAGATEAREA 0.741000 ;
    PORT
      LAYER Metal2 ;
        RECT 309.120 849.440 309.680 850.000 ;
    END
  END n0_in[49]
  PIN n0_in[4]
    DIRECTION INPUT ;
    USE SIGNAL ;
    ANTENNAGATEAREA 0.741000 ;
    PORT
      LAYER Metal3 ;
        RECT 849.440 320.320 850.000 320.880 ;
    END
  END n0_in[4]
  PIN n0_in[50]
    DIRECTION INPUT ;
    USE SIGNAL ;
    ANTENNAGATEAREA 0.741000 ;
    PORT
      LAYER Metal2 ;
        RECT 359.520 849.440 360.080 850.000 ;
    END
  END n0_in[50]
  PIN n0_in[51]
    DIRECTION INPUT ;
    USE SIGNAL ;
    ANTENNAGATEAREA 0.741000 ;
    PORT
      LAYER Metal2 ;
        RECT 245.280 849.440 245.840 850.000 ;
    END
  END n0_in[51]
  PIN n0_in[52]
    DIRECTION INPUT ;
    USE SIGNAL ;
    ANTENNAGATEAREA 0.741000 ;
    PORT
      LAYER Metal2 ;
        RECT 312.480 849.440 313.040 850.000 ;
    END
  END n0_in[52]
  PIN n0_in[53]
    DIRECTION INPUT ;
    USE SIGNAL ;
    ANTENNAGATEAREA 0.741000 ;
    PORT
      LAYER Metal2 ;
        RECT 432.320 849.440 432.880 850.000 ;
    END
  END n0_in[53]
  PIN n0_in[54]
    DIRECTION INPUT ;
    USE SIGNAL ;
    ANTENNAGATEAREA 0.741000 ;
    PORT
      LAYER Metal2 ;
        RECT 498.400 849.440 498.960 850.000 ;
    END
  END n0_in[54]
  PIN n0_in[55]
    DIRECTION INPUT ;
    USE SIGNAL ;
    ANTENNAGATEAREA 0.741000 ;
    PORT
      LAYER Metal2 ;
        RECT 459.200 849.440 459.760 850.000 ;
    END
  END n0_in[55]
  PIN n0_in[56]
    DIRECTION INPUT ;
    USE SIGNAL ;
    ANTENNAGATEAREA 0.741000 ;
    PORT
      LAYER Metal2 ;
        RECT 501.760 849.440 502.320 850.000 ;
    END
  END n0_in[56]
  PIN n0_in[57]
    DIRECTION INPUT ;
    USE SIGNAL ;
    ANTENNAGATEAREA 0.741000 ;
    PORT
      LAYER Metal2 ;
        RECT 540.960 849.440 541.520 850.000 ;
    END
  END n0_in[57]
  PIN n0_in[58]
    DIRECTION INPUT ;
    USE SIGNAL ;
    ANTENNAGATEAREA 0.741000 ;
    PORT
      LAYER Metal3 ;
        RECT 849.440 515.200 850.000 515.760 ;
    END
  END n0_in[58]
  PIN n0_in[59]
    DIRECTION INPUT ;
    USE SIGNAL ;
    ANTENNAGATEAREA 0.741000 ;
    PORT
      LAYER Metal2 ;
        RECT 572.320 849.440 572.880 850.000 ;
    END
  END n0_in[59]
  PIN n0_in[5]
    DIRECTION INPUT ;
    USE SIGNAL ;
    ANTENNAGATEAREA 0.741000 ;
    PORT
      LAYER Metal2 ;
        RECT 557.760 0.000 558.320 0.560 ;
    END
  END n0_in[5]
  PIN n0_in[60]
    DIRECTION INPUT ;
    USE SIGNAL ;
    ANTENNAGATEAREA 0.741000 ;
    PORT
      LAYER Metal3 ;
        RECT 849.440 621.600 850.000 622.160 ;
    END
  END n0_in[60]
  PIN n0_in[61]
    DIRECTION INPUT ;
    USE SIGNAL ;
    ANTENNAGATEAREA 0.741000 ;
    PORT
      LAYER Metal3 ;
        RECT 849.440 581.280 850.000 581.840 ;
    END
  END n0_in[61]
  PIN n0_in[62]
    DIRECTION INPUT ;
    USE SIGNAL ;
    ANTENNAGATEAREA 0.741000 ;
    PORT
      LAYER Metal3 ;
        RECT 849.440 585.760 850.000 586.320 ;
    END
  END n0_in[62]
  PIN n0_in[63]
    DIRECTION INPUT ;
    USE SIGNAL ;
    ANTENNAGATEAREA 0.741000 ;
    PORT
      LAYER Metal3 ;
        RECT 849.440 512.960 850.000 513.520 ;
    END
  END n0_in[63]
  PIN n0_in[6]
    DIRECTION INPUT ;
    USE SIGNAL ;
    ANTENNAGATEAREA 0.741000 ;
    PORT
      LAYER Metal2 ;
        RECT 636.160 0.000 636.720 0.560 ;
    END
  END n0_in[6]
  PIN n0_in[7]
    DIRECTION INPUT ;
    USE SIGNAL ;
    ANTENNAGATEAREA 0.741000 ;
    PORT
      LAYER Metal2 ;
        RECT 638.400 0.000 638.960 0.560 ;
    END
  END n0_in[7]
  PIN n0_in[8]
    DIRECTION INPUT ;
    USE SIGNAL ;
    ANTENNAGATEAREA 0.741000 ;
    PORT
      LAYER Metal3 ;
        RECT 849.440 359.520 850.000 360.080 ;
    END
  END n0_in[8]
  PIN n0_in[9]
    DIRECTION INPUT ;
    USE SIGNAL ;
    ANTENNAGATEAREA 0.741000 ;
    PORT
      LAYER Metal3 ;
        RECT 849.440 431.200 850.000 431.760 ;
    END
  END n0_in[9]
  PIN n1_in[0]
    DIRECTION INPUT ;
    USE SIGNAL ;
    ANTENNAGATEAREA 0.741000 ;
    PORT
      LAYER Metal3 ;
        RECT 849.440 347.200 850.000 347.760 ;
    END
  END n1_in[0]
  PIN n1_in[10]
    DIRECTION INPUT ;
    USE SIGNAL ;
    ANTENNAGATEAREA 0.741000 ;
    PORT
      LAYER Metal3 ;
        RECT 849.440 365.120 850.000 365.680 ;
    END
  END n1_in[10]
  PIN n1_in[11]
    DIRECTION INPUT ;
    USE SIGNAL ;
    ANTENNAGATEAREA 0.741000 ;
    PORT
      LAYER Metal3 ;
        RECT 849.440 340.480 850.000 341.040 ;
    END
  END n1_in[11]
  PIN n1_in[12]
    DIRECTION INPUT ;
    USE SIGNAL ;
    ANTENNAGATEAREA 0.741000 ;
    PORT
      LAYER Metal3 ;
        RECT 849.440 308.000 850.000 308.560 ;
    END
  END n1_in[12]
  PIN n1_in[13]
    DIRECTION INPUT ;
    USE SIGNAL ;
    ANTENNAGATEAREA 0.741000 ;
    PORT
      LAYER Metal3 ;
        RECT 849.440 387.520 850.000 388.080 ;
    END
  END n1_in[13]
  PIN n1_in[14]
    DIRECTION INPUT ;
    USE SIGNAL ;
    ANTENNAGATEAREA 0.741000 ;
    PORT
      LAYER Metal3 ;
        RECT 849.440 469.280 850.000 469.840 ;
    END
  END n1_in[14]
  PIN n1_in[15]
    DIRECTION INPUT ;
    USE SIGNAL ;
    ANTENNAGATEAREA 0.741000 ;
    PORT
      LAYER Metal3 ;
        RECT 849.440 524.160 850.000 524.720 ;
    END
  END n1_in[15]
  PIN n1_in[16]
    DIRECTION INPUT ;
    USE SIGNAL ;
    ANTENNAGATEAREA 0.741000 ;
    PORT
      LAYER Metal3 ;
        RECT 849.440 370.720 850.000 371.280 ;
    END
  END n1_in[16]
  PIN n1_in[17]
    DIRECTION INPUT ;
    USE SIGNAL ;
    ANTENNAGATEAREA 0.741000 ;
    PORT
      LAYER Metal2 ;
        RECT 369.600 0.000 370.160 0.560 ;
    END
  END n1_in[17]
  PIN n1_in[18]
    DIRECTION INPUT ;
    USE SIGNAL ;
    ANTENNAGATEAREA 0.741000 ;
    PORT
      LAYER Metal2 ;
        RECT 450.240 0.000 450.800 0.560 ;
    END
  END n1_in[18]
  PIN n1_in[19]
    DIRECTION INPUT ;
    USE SIGNAL ;
    ANTENNAGATEAREA 0.741000 ;
    PORT
      LAYER Metal2 ;
        RECT 399.840 0.000 400.400 0.560 ;
    END
  END n1_in[19]
  PIN n1_in[1]
    DIRECTION INPUT ;
    USE SIGNAL ;
    ANTENNAGATEAREA 0.741000 ;
    PORT
      LAYER Metal3 ;
        RECT 849.440 315.840 850.000 316.400 ;
    END
  END n1_in[1]
  PIN n1_in[20]
    DIRECTION INPUT ;
    USE SIGNAL ;
    ANTENNAGATEAREA 0.741000 ;
    PORT
      LAYER Metal2 ;
        RECT 478.240 0.000 478.800 0.560 ;
    END
  END n1_in[20]
  PIN n1_in[21]
    DIRECTION INPUT ;
    USE SIGNAL ;
    ANTENNAGATEAREA 0.741000 ;
    PORT
      LAYER Metal2 ;
        RECT 435.680 0.000 436.240 0.560 ;
    END
  END n1_in[21]
  PIN n1_in[22]
    DIRECTION INPUT ;
    USE SIGNAL ;
    ANTENNAGATEAREA 0.741000 ;
    PORT
      LAYER Metal2 ;
        RECT 327.040 0.000 327.600 0.560 ;
    END
  END n1_in[22]
  PIN n1_in[23]
    DIRECTION INPUT ;
    USE SIGNAL ;
    ANTENNAGATEAREA 0.741000 ;
    PORT
      LAYER Metal2 ;
        RECT 407.680 0.000 408.240 0.560 ;
    END
  END n1_in[23]
  PIN n1_in[24]
    DIRECTION INPUT ;
    USE SIGNAL ;
    ANTENNAGATEAREA 0.741000 ;
    PORT
      LAYER Metal2 ;
        RECT 346.080 0.000 346.640 0.560 ;
    END
  END n1_in[24]
  PIN n1_in[25]
    DIRECTION INPUT ;
    USE SIGNAL ;
    ANTENNAGATEAREA 0.741000 ;
    PORT
      LAYER Metal2 ;
        RECT 309.120 0.000 309.680 0.560 ;
    END
  END n1_in[25]
  PIN n1_in[26]
    DIRECTION INPUT ;
    USE SIGNAL ;
    ANTENNAGATEAREA 0.741000 ;
    PORT
      LAYER Metal3 ;
        RECT 0.000 384.160 0.560 384.720 ;
    END
  END n1_in[26]
  PIN n1_in[27]
    DIRECTION INPUT ;
    USE SIGNAL ;
    ANTENNAGATEAREA 0.741000 ;
    PORT
      LAYER Metal3 ;
        RECT 0.000 327.040 0.560 327.600 ;
    END
  END n1_in[27]
  PIN n1_in[28]
    DIRECTION INPUT ;
    USE SIGNAL ;
    ANTENNAGATEAREA 0.741000 ;
    PORT
      LAYER Metal3 ;
        RECT 0.000 282.240 0.560 282.800 ;
    END
  END n1_in[28]
  PIN n1_in[29]
    DIRECTION INPUT ;
    USE SIGNAL ;
    ANTENNAGATEAREA 0.741000 ;
    PORT
      LAYER Metal3 ;
        RECT 0.000 229.600 0.560 230.160 ;
    END
  END n1_in[29]
  PIN n1_in[2]
    DIRECTION INPUT ;
    USE SIGNAL ;
    ANTENNAGATEAREA 0.741000 ;
    PORT
      LAYER Metal2 ;
        RECT 511.840 0.000 512.400 0.560 ;
    END
  END n1_in[2]
  PIN n1_in[30]
    DIRECTION INPUT ;
    USE SIGNAL ;
    ANTENNAGATEAREA 0.741000 ;
    PORT
      LAYER Metal2 ;
        RECT 308.000 0.000 308.560 0.560 ;
    END
  END n1_in[30]
  PIN n1_in[31]
    DIRECTION INPUT ;
    USE SIGNAL ;
    ANTENNAGATEAREA 0.741000 ;
    PORT
      LAYER Metal2 ;
        RECT 355.040 0.000 355.600 0.560 ;
    END
  END n1_in[31]
  PIN n1_in[32]
    DIRECTION INPUT ;
    USE SIGNAL ;
    ANTENNAGATEAREA 0.741000 ;
    PORT
      LAYER Metal3 ;
        RECT 0.000 456.960 0.560 457.520 ;
    END
  END n1_in[32]
  PIN n1_in[33]
    DIRECTION INPUT ;
    USE SIGNAL ;
    ANTENNAGATEAREA 0.741000 ;
    PORT
      LAYER Metal2 ;
        RECT 336.000 0.000 336.560 0.560 ;
    END
  END n1_in[33]
  PIN n1_in[34]
    DIRECTION INPUT ;
    USE SIGNAL ;
    ANTENNAGATEAREA 0.741000 ;
    PORT
      LAYER Metal3 ;
        RECT 0.000 395.360 0.560 395.920 ;
    END
  END n1_in[34]
  PIN n1_in[35]
    DIRECTION INPUT ;
    USE SIGNAL ;
    ANTENNAGATEAREA 0.741000 ;
    PORT
      LAYER Metal3 ;
        RECT 0.000 328.160 0.560 328.720 ;
    END
  END n1_in[35]
  PIN n1_in[36]
    DIRECTION INPUT ;
    USE SIGNAL ;
    ANTENNAGATEAREA 0.741000 ;
    PORT
      LAYER Metal3 ;
        RECT 0.000 374.080 0.560 374.640 ;
    END
  END n1_in[36]
  PIN n1_in[37]
    DIRECTION INPUT ;
    USE SIGNAL ;
    ANTENNAGATEAREA 0.741000 ;
    PORT
      LAYER Metal3 ;
        RECT 0.000 463.680 0.560 464.240 ;
    END
  END n1_in[37]
  PIN n1_in[38]
    DIRECTION INPUT ;
    USE SIGNAL ;
    ANTENNAGATEAREA 0.741000 ;
    PORT
      LAYER Metal3 ;
        RECT 0.000 469.280 0.560 469.840 ;
    END
  END n1_in[38]
  PIN n1_in[39]
    DIRECTION INPUT ;
    USE SIGNAL ;
    ANTENNAGATEAREA 0.741000 ;
    PORT
      LAYER Metal3 ;
        RECT 0.000 480.480 0.560 481.040 ;
    END
  END n1_in[39]
  PIN n1_in[3]
    DIRECTION INPUT ;
    USE SIGNAL ;
    ANTENNAGATEAREA 0.741000 ;
    PORT
      LAYER Metal3 ;
        RECT 849.440 257.600 850.000 258.160 ;
    END
  END n1_in[3]
  PIN n1_in[40]
    DIRECTION INPUT ;
    USE SIGNAL ;
    ANTENNAGATEAREA 0.741000 ;
    PORT
      LAYER Metal3 ;
        RECT 0.000 528.640 0.560 529.200 ;
    END
  END n1_in[40]
  PIN n1_in[41]
    DIRECTION INPUT ;
    USE SIGNAL ;
    ANTENNAGATEAREA 0.741000 ;
    PORT
      LAYER Metal3 ;
        RECT 0.000 517.440 0.560 518.000 ;
    END
  END n1_in[41]
  PIN n1_in[42]
    DIRECTION INPUT ;
    USE SIGNAL ;
    ANTENNAGATEAREA 0.741000 ;
    PORT
      LAYER Metal3 ;
        RECT 0.000 529.760 0.560 530.320 ;
    END
  END n1_in[42]
  PIN n1_in[43]
    DIRECTION INPUT ;
    USE SIGNAL ;
    ANTENNAGATEAREA 0.741000 ;
    PORT
      LAYER Metal2 ;
        RECT 380.800 849.440 381.360 850.000 ;
    END
  END n1_in[43]
  PIN n1_in[44]
    DIRECTION INPUT ;
    USE SIGNAL ;
    ANTENNAGATEAREA 0.741000 ;
    PORT
      LAYER Metal3 ;
        RECT 0.000 649.600 0.560 650.160 ;
    END
  END n1_in[44]
  PIN n1_in[45]
    DIRECTION INPUT ;
    USE SIGNAL ;
    ANTENNAGATEAREA 0.741000 ;
    PORT
      LAYER Metal3 ;
        RECT 0.000 602.560 0.560 603.120 ;
    END
  END n1_in[45]
  PIN n1_in[46]
    DIRECTION INPUT ;
    USE SIGNAL ;
    ANTENNAGATEAREA 0.741000 ;
    PORT
      LAYER Metal2 ;
        RECT 285.600 849.440 286.160 850.000 ;
    END
  END n1_in[46]
  PIN n1_in[47]
    DIRECTION INPUT ;
    USE SIGNAL ;
    ANTENNAGATEAREA 0.741000 ;
    PORT
      LAYER Metal3 ;
        RECT 0.000 560.000 0.560 560.560 ;
    END
  END n1_in[47]
  PIN n1_in[48]
    DIRECTION INPUT ;
    USE SIGNAL ;
    ANTENNAGATEAREA 0.741000 ;
    PORT
      LAYER Metal2 ;
        RECT 416.640 849.440 417.200 850.000 ;
    END
  END n1_in[48]
  PIN n1_in[49]
    DIRECTION INPUT ;
    USE SIGNAL ;
    ANTENNAGATEAREA 0.741000 ;
    PORT
      LAYER Metal2 ;
        RECT 294.560 849.440 295.120 850.000 ;
    END
  END n1_in[49]
  PIN n1_in[4]
    DIRECTION INPUT ;
    USE SIGNAL ;
    ANTENNAGATEAREA 0.741000 ;
    PORT
      LAYER Metal3 ;
        RECT 849.440 337.120 850.000 337.680 ;
    END
  END n1_in[4]
  PIN n1_in[50]
    DIRECTION INPUT ;
    USE SIGNAL ;
    ANTENNAGATEAREA 0.741000 ;
    PORT
      LAYER Metal2 ;
        RECT 381.920 849.440 382.480 850.000 ;
    END
  END n1_in[50]
  PIN n1_in[51]
    DIRECTION INPUT ;
    USE SIGNAL ;
    ANTENNAGATEAREA 0.741000 ;
    PORT
      LAYER Metal2 ;
        RECT 250.880 849.440 251.440 850.000 ;
    END
  END n1_in[51]
  PIN n1_in[52]
    DIRECTION INPUT ;
    USE SIGNAL ;
    ANTENNAGATEAREA 0.741000 ;
    PORT
      LAYER Metal2 ;
        RECT 330.400 849.440 330.960 850.000 ;
    END
  END n1_in[52]
  PIN n1_in[53]
    DIRECTION INPUT ;
    USE SIGNAL ;
    ANTENNAGATEAREA 0.741000 ;
    PORT
      LAYER Metal2 ;
        RECT 412.160 849.440 412.720 850.000 ;
    END
  END n1_in[53]
  PIN n1_in[54]
    DIRECTION INPUT ;
    USE SIGNAL ;
    ANTENNAGATEAREA 0.741000 ;
    PORT
      LAYER Metal2 ;
        RECT 482.720 849.440 483.280 850.000 ;
    END
  END n1_in[54]
  PIN n1_in[55]
    DIRECTION INPUT ;
    USE SIGNAL ;
    ANTENNAGATEAREA 0.741000 ;
    PORT
      LAYER Metal2 ;
        RECT 408.800 849.440 409.360 850.000 ;
    END
  END n1_in[55]
  PIN n1_in[56]
    DIRECTION INPUT ;
    USE SIGNAL ;
    ANTENNAGATEAREA 0.741000 ;
    PORT
      LAYER Metal2 ;
        RECT 449.120 849.440 449.680 850.000 ;
    END
  END n1_in[56]
  PIN n1_in[57]
    DIRECTION INPUT ;
    USE SIGNAL ;
    ANTENNAGATEAREA 0.741000 ;
    PORT
      LAYER Metal2 ;
        RECT 506.240 849.440 506.800 850.000 ;
    END
  END n1_in[57]
  PIN n1_in[58]
    DIRECTION INPUT ;
    USE SIGNAL ;
    ANTENNAGATEAREA 0.741000 ;
    PORT
      LAYER Metal2 ;
        RECT 502.880 849.440 503.440 850.000 ;
    END
  END n1_in[58]
  PIN n1_in[59]
    DIRECTION INPUT ;
    USE SIGNAL ;
    ANTENNAGATEAREA 0.741000 ;
    PORT
      LAYER Metal2 ;
        RECT 556.640 849.440 557.200 850.000 ;
    END
  END n1_in[59]
  PIN n1_in[5]
    DIRECTION INPUT ;
    USE SIGNAL ;
    ANTENNAGATEAREA 0.741000 ;
    PORT
      LAYER Metal2 ;
        RECT 515.200 0.000 515.760 0.560 ;
    END
  END n1_in[5]
  PIN n1_in[60]
    DIRECTION INPUT ;
    USE SIGNAL ;
    ANTENNAGATEAREA 0.741000 ;
    PORT
      LAYER Metal2 ;
        RECT 596.960 849.440 597.520 850.000 ;
    END
  END n1_in[60]
  PIN n1_in[61]
    DIRECTION INPUT ;
    USE SIGNAL ;
    ANTENNAGATEAREA 0.741000 ;
    PORT
      LAYER Metal3 ;
        RECT 849.440 544.320 850.000 544.880 ;
    END
  END n1_in[61]
  PIN n1_in[62]
    DIRECTION INPUT ;
    USE SIGNAL ;
    ANTENNAGATEAREA 0.741000 ;
    PORT
      LAYER Metal2 ;
        RECT 529.760 849.440 530.320 850.000 ;
    END
  END n1_in[62]
  PIN n1_in[63]
    DIRECTION INPUT ;
    USE SIGNAL ;
    ANTENNAGATEAREA 0.741000 ;
    PORT
      LAYER Metal3 ;
        RECT 849.440 487.200 850.000 487.760 ;
    END
  END n1_in[63]
  PIN n1_in[6]
    DIRECTION INPUT ;
    USE SIGNAL ;
    ANTENNAGATEAREA 0.741000 ;
    PORT
      LAYER Metal2 ;
        RECT 492.800 0.000 493.360 0.560 ;
    END
  END n1_in[6]
  PIN n1_in[7]
    DIRECTION INPUT ;
    USE SIGNAL ;
    ANTENNAGATEAREA 0.741000 ;
    PORT
      LAYER Metal2 ;
        RECT 598.080 0.000 598.640 0.560 ;
    END
  END n1_in[7]
  PIN n1_in[8]
    DIRECTION INPUT ;
    USE SIGNAL ;
    ANTENNAGATEAREA 0.741000 ;
    PORT
      LAYER Metal3 ;
        RECT 849.440 379.680 850.000 380.240 ;
    END
  END n1_in[8]
  PIN n1_in[9]
    DIRECTION INPUT ;
    USE SIGNAL ;
    ANTENNAGATEAREA 0.741000 ;
    PORT
      LAYER Metal3 ;
        RECT 849.440 443.520 850.000 444.080 ;
    END
  END n1_in[9]
  PIN rst_n
    DIRECTION INPUT ;
    USE SIGNAL ;
    ANTENNAGATEAREA 2.369000 ;
    PORT
      LAYER Metal3 ;
        RECT 849.440 225.120 850.000 225.680 ;
    END
  END rst_n
  PIN start
    DIRECTION INPUT ;
    USE SIGNAL ;
    ANTENNAGATEAREA 0.741000 ;
    PORT
      LAYER Metal3 ;
        RECT 849.440 462.560 850.000 463.120 ;
    END
  END start
  PIN t0_out[0]
    DIRECTION OUTPUT ;
    USE SIGNAL ;
    ANTENNADIFFAREA 1.182800 ;
    PORT
      LAYER Metal2 ;
        RECT 510.720 0.000 511.280 0.560 ;
    END
  END t0_out[0]
  PIN t0_out[10]
    DIRECTION OUTPUT ;
    USE SIGNAL ;
    ANTENNADIFFAREA 1.182800 ;
    PORT
      LAYER Metal3 ;
        RECT 849.440 364.000 850.000 364.560 ;
    END
  END t0_out[10]
  PIN t0_out[11]
    DIRECTION OUTPUT ;
    USE SIGNAL ;
    ANTENNADIFFAREA 1.182800 ;
    PORT
      LAYER Metal3 ;
        RECT 849.440 318.080 850.000 318.640 ;
    END
  END t0_out[11]
  PIN t0_out[12]
    DIRECTION OUTPUT ;
    USE SIGNAL ;
    ANTENNADIFFAREA 1.182800 ;
    PORT
      LAYER Metal3 ;
        RECT 849.440 290.080 850.000 290.640 ;
    END
  END t0_out[12]
  PIN t0_out[13]
    DIRECTION OUTPUT ;
    USE SIGNAL ;
    ANTENNADIFFAREA 1.182800 ;
    PORT
      LAYER Metal3 ;
        RECT 849.440 350.560 850.000 351.120 ;
    END
  END t0_out[13]
  PIN t0_out[14]
    DIRECTION OUTPUT ;
    USE SIGNAL ;
    ANTENNADIFFAREA 1.182800 ;
    PORT
      LAYER Metal3 ;
        RECT 849.440 232.960 850.000 233.520 ;
    END
  END t0_out[14]
  PIN t0_out[15]
    DIRECTION OUTPUT ;
    USE SIGNAL ;
    ANTENNADIFFAREA 1.182800 ;
    PORT
      LAYER Metal3 ;
        RECT 849.440 482.720 850.000 483.280 ;
    END
  END t0_out[15]
  PIN t0_out[16]
    DIRECTION OUTPUT ;
    USE SIGNAL ;
    ANTENNADIFFAREA 1.182800 ;
    PORT
      LAYER Metal3 ;
        RECT 849.440 333.760 850.000 334.320 ;
    END
  END t0_out[16]
  PIN t0_out[17]
    DIRECTION OUTPUT ;
    USE SIGNAL ;
    ANTENNADIFFAREA 1.182800 ;
    PORT
      LAYER Metal2 ;
        RECT 551.040 0.000 551.600 0.560 ;
    END
  END t0_out[17]
  PIN t0_out[18]
    DIRECTION OUTPUT ;
    USE SIGNAL ;
    ANTENNADIFFAREA 1.182800 ;
    PORT
      LAYER Metal2 ;
        RECT 508.480 0.000 509.040 0.560 ;
    END
  END t0_out[18]
  PIN t0_out[19]
    DIRECTION OUTPUT ;
    USE SIGNAL ;
    ANTENNADIFFAREA 1.182800 ;
    PORT
      LAYER Metal2 ;
        RECT 592.480 0.000 593.040 0.560 ;
    END
  END t0_out[19]
  PIN t0_out[1]
    DIRECTION OUTPUT ;
    USE SIGNAL ;
    ANTENNADIFFAREA 1.182800 ;
    PORT
      LAYER Metal2 ;
        RECT 552.160 0.000 552.720 0.560 ;
    END
  END t0_out[1]
  PIN t0_out[20]
    DIRECTION OUTPUT ;
    USE SIGNAL ;
    ANTENNADIFFAREA 1.182800 ;
    PORT
      LAYER Metal3 ;
        RECT 849.440 208.320 850.000 208.880 ;
    END
  END t0_out[20]
  PIN t0_out[21]
    DIRECTION OUTPUT ;
    USE SIGNAL ;
    ANTENNADIFFAREA 1.182800 ;
    PORT
      LAYER Metal2 ;
        RECT 495.040 0.000 495.600 0.560 ;
    END
  END t0_out[21]
  PIN t0_out[22]
    DIRECTION OUTPUT ;
    USE SIGNAL ;
    ANTENNADIFFAREA 1.182800 ;
    PORT
      LAYER Metal2 ;
        RECT 325.920 0.000 326.480 0.560 ;
    END
  END t0_out[22]
  PIN t0_out[23]
    DIRECTION OUTPUT ;
    USE SIGNAL ;
    ANTENNADIFFAREA 1.182800 ;
    PORT
      LAYER Metal2 ;
        RECT 436.800 0.000 437.360 0.560 ;
    END
  END t0_out[23]
  PIN t0_out[24]
    DIRECTION OUTPUT ;
    USE SIGNAL ;
    ANTENNADIFFAREA 1.182800 ;
    PORT
      LAYER Metal2 ;
        RECT 329.280 0.000 329.840 0.560 ;
    END
  END t0_out[24]
  PIN t0_out[25]
    DIRECTION OUTPUT ;
    USE SIGNAL ;
    ANTENNADIFFAREA 1.182800 ;
    PORT
      LAYER Metal2 ;
        RECT 290.080 0.000 290.640 0.560 ;
    END
  END t0_out[25]
  PIN t0_out[26]
    DIRECTION OUTPUT ;
    USE SIGNAL ;
    ANTENNADIFFAREA 1.182800 ;
    PORT
      LAYER Metal3 ;
        RECT 0.000 300.160 0.560 300.720 ;
    END
  END t0_out[26]
  PIN t0_out[27]
    DIRECTION OUTPUT ;
    USE SIGNAL ;
    ANTENNADIFFAREA 1.182800 ;
    PORT
      LAYER Metal2 ;
        RECT 315.840 0.000 316.400 0.560 ;
    END
  END t0_out[27]
  PIN t0_out[28]
    DIRECTION OUTPUT ;
    USE SIGNAL ;
    ANTENNADIFFAREA 1.182800 ;
    PORT
      LAYER Metal3 ;
        RECT 0.000 285.600 0.560 286.160 ;
    END
  END t0_out[28]
  PIN t0_out[29]
    DIRECTION OUTPUT ;
    USE SIGNAL ;
    ANTENNADIFFAREA 1.182800 ;
    PORT
      LAYER Metal3 ;
        RECT 0.000 219.520 0.560 220.080 ;
    END
  END t0_out[29]
  PIN t0_out[2]
    DIRECTION OUTPUT ;
    USE SIGNAL ;
    ANTENNADIFFAREA 1.182800 ;
    PORT
      LAYER Metal2 ;
        RECT 572.320 0.000 572.880 0.560 ;
    END
  END t0_out[2]
  PIN t0_out[30]
    DIRECTION OUTPUT ;
    USE SIGNAL ;
    ANTENNADIFFAREA 1.182800 ;
    PORT
      LAYER Metal3 ;
        RECT 0.000 260.960 0.560 261.520 ;
    END
  END t0_out[30]
  PIN t0_out[31]
    DIRECTION OUTPUT ;
    USE SIGNAL ;
    ANTENNADIFFAREA 1.182800 ;
    PORT
      LAYER Metal2 ;
        RECT 386.400 0.000 386.960 0.560 ;
    END
  END t0_out[31]
  PIN t0_out[32]
    DIRECTION OUTPUT ;
    USE SIGNAL ;
    ANTENNADIFFAREA 1.182800 ;
    PORT
      LAYER Metal3 ;
        RECT 0.000 490.560 0.560 491.120 ;
    END
  END t0_out[32]
  PIN t0_out[33]
    DIRECTION OUTPUT ;
    USE SIGNAL ;
    ANTENNADIFFAREA 1.182800 ;
    PORT
      LAYER Metal3 ;
        RECT 0.000 386.400 0.560 386.960 ;
    END
  END t0_out[33]
  PIN t0_out[34]
    DIRECTION OUTPUT ;
    USE SIGNAL ;
    ANTENNADIFFAREA 1.182800 ;
    PORT
      LAYER Metal3 ;
        RECT 0.000 496.160 0.560 496.720 ;
    END
  END t0_out[34]
  PIN t0_out[35]
    DIRECTION OUTPUT ;
    USE SIGNAL ;
    ANTENNADIFFAREA 1.182800 ;
    PORT
      LAYER Metal3 ;
        RECT 0.000 314.720 0.560 315.280 ;
    END
  END t0_out[35]
  PIN t0_out[36]
    DIRECTION OUTPUT ;
    USE SIGNAL ;
    ANTENNADIFFAREA 1.182800 ;
    PORT
      LAYER Metal3 ;
        RECT 0.000 360.640 0.560 361.200 ;
    END
  END t0_out[36]
  PIN t0_out[37]
    DIRECTION OUTPUT ;
    USE SIGNAL ;
    ANTENNADIFFAREA 1.182800 ;
    PORT
      LAYER Metal3 ;
        RECT 0.000 482.720 0.560 483.280 ;
    END
  END t0_out[37]
  PIN t0_out[38]
    DIRECTION OUTPUT ;
    USE SIGNAL ;
    ANTENNADIFFAREA 1.182800 ;
    PORT
      LAYER Metal3 ;
        RECT 0.000 489.440 0.560 490.000 ;
    END
  END t0_out[38]
  PIN t0_out[39]
    DIRECTION OUTPUT ;
    USE SIGNAL ;
    ANTENNADIFFAREA 1.182800 ;
    PORT
      LAYER Metal3 ;
        RECT 0.000 484.960 0.560 485.520 ;
    END
  END t0_out[39]
  PIN t0_out[3]
    DIRECTION OUTPUT ;
    USE SIGNAL ;
    ANTENNADIFFAREA 1.182800 ;
    PORT
      LAYER Metal3 ;
        RECT 849.440 220.640 850.000 221.200 ;
    END
  END t0_out[3]
  PIN t0_out[40]
    DIRECTION OUTPUT ;
    USE SIGNAL ;
    ANTENNADIFFAREA 1.182800 ;
    PORT
      LAYER Metal2 ;
        RECT 323.680 849.440 324.240 850.000 ;
    END
  END t0_out[40]
  PIN t0_out[41]
    DIRECTION OUTPUT ;
    USE SIGNAL ;
    ANTENNADIFFAREA 1.182800 ;
    PORT
      LAYER Metal3 ;
        RECT 0.000 545.440 0.560 546.000 ;
    END
  END t0_out[41]
  PIN t0_out[42]
    DIRECTION OUTPUT ;
    USE SIGNAL ;
    ANTENNADIFFAREA 1.182800 ;
    PORT
      LAYER Metal2 ;
        RECT 293.440 849.440 294.000 850.000 ;
    END
  END t0_out[42]
  PIN t0_out[43]
    DIRECTION OUTPUT ;
    USE SIGNAL ;
    ANTENNADIFFAREA 1.182800 ;
    PORT
      LAYER Metal2 ;
        RECT 346.080 849.440 346.640 850.000 ;
    END
  END t0_out[43]
  PIN t0_out[44]
    DIRECTION OUTPUT ;
    USE SIGNAL ;
    ANTENNADIFFAREA 1.182800 ;
    PORT
      LAYER Metal2 ;
        RECT 206.080 849.440 206.640 850.000 ;
    END
  END t0_out[44]
  PIN t0_out[45]
    DIRECTION OUTPUT ;
    USE SIGNAL ;
    ANTENNADIFFAREA 1.182800 ;
    PORT
      LAYER Metal3 ;
        RECT 0.000 585.760 0.560 586.320 ;
    END
  END t0_out[45]
  PIN t0_out[46]
    DIRECTION OUTPUT ;
    USE SIGNAL ;
    ANTENNADIFFAREA 1.182800 ;
    PORT
      LAYER Metal2 ;
        RECT 286.720 849.440 287.280 850.000 ;
    END
  END t0_out[46]
  PIN t0_out[47]
    DIRECTION OUTPUT ;
    USE SIGNAL ;
    ANTENNADIFFAREA 1.182800 ;
    PORT
      LAYER Metal3 ;
        RECT 0.000 582.400 0.560 582.960 ;
    END
  END t0_out[47]
  PIN t0_out[48]
    DIRECTION OUTPUT ;
    USE SIGNAL ;
    ANTENNADIFFAREA 1.182800 ;
    PORT
      LAYER Metal2 ;
        RECT 437.920 849.440 438.480 850.000 ;
    END
  END t0_out[48]
  PIN t0_out[49]
    DIRECTION OUTPUT ;
    USE SIGNAL ;
    ANTENNADIFFAREA 1.182800 ;
    PORT
      LAYER Metal2 ;
        RECT 232.960 849.440 233.520 850.000 ;
    END
  END t0_out[49]
  PIN t0_out[4]
    DIRECTION OUTPUT ;
    USE SIGNAL ;
    ANTENNADIFFAREA 1.182800 ;
    PORT
      LAYER Metal3 ;
        RECT 849.440 248.640 850.000 249.200 ;
    END
  END t0_out[4]
  PIN t0_out[50]
    DIRECTION OUTPUT ;
    USE SIGNAL ;
    ANTENNADIFFAREA 1.182800 ;
    PORT
      LAYER Metal2 ;
        RECT 341.600 849.440 342.160 850.000 ;
    END
  END t0_out[50]
  PIN t0_out[51]
    DIRECTION OUTPUT ;
    USE SIGNAL ;
    ANTENNADIFFAREA 1.182800 ;
    PORT
      LAYER Metal2 ;
        RECT 230.720 849.440 231.280 850.000 ;
    END
  END t0_out[51]
  PIN t0_out[52]
    DIRECTION OUTPUT ;
    USE SIGNAL ;
    ANTENNADIFFAREA 1.182800 ;
    PORT
      LAYER Metal2 ;
        RECT 236.320 849.440 236.880 850.000 ;
    END
  END t0_out[52]
  PIN t0_out[53]
    DIRECTION OUTPUT ;
    USE SIGNAL ;
    ANTENNADIFFAREA 1.182800 ;
    PORT
      LAYER Metal2 ;
        RECT 415.520 849.440 416.080 850.000 ;
    END
  END t0_out[53]
  PIN t0_out[54]
    DIRECTION OUTPUT ;
    USE SIGNAL ;
    ANTENNADIFFAREA 1.182800 ;
    PORT
      LAYER Metal2 ;
        RECT 478.240 849.440 478.800 850.000 ;
    END
  END t0_out[54]
  PIN t0_out[55]
    DIRECTION OUTPUT ;
    USE SIGNAL ;
    ANTENNADIFFAREA 1.182800 ;
    PORT
      LAYER Metal2 ;
        RECT 392.000 849.440 392.560 850.000 ;
    END
  END t0_out[55]
  PIN t0_out[56]
    DIRECTION OUTPUT ;
    USE SIGNAL ;
    ANTENNADIFFAREA 1.182800 ;
    PORT
      LAYER Metal3 ;
        RECT 0.000 584.640 0.560 585.200 ;
    END
  END t0_out[56]
  PIN t0_out[57]
    DIRECTION OUTPUT ;
    USE SIGNAL ;
    ANTENNADIFFAREA 1.182800 ;
    PORT
      LAYER Metal2 ;
        RECT 538.720 849.440 539.280 850.000 ;
    END
  END t0_out[57]
  PIN t0_out[58]
    DIRECTION OUTPUT ;
    USE SIGNAL ;
    ANTENNADIFFAREA 1.182800 ;
    PORT
      LAYER Metal3 ;
        RECT 849.440 521.920 850.000 522.480 ;
    END
  END t0_out[58]
  PIN t0_out[59]
    DIRECTION OUTPUT ;
    USE SIGNAL ;
    ANTENNADIFFAREA 1.182800 ;
    PORT
      LAYER Metal2 ;
        RECT 548.800 849.440 549.360 850.000 ;
    END
  END t0_out[59]
  PIN t0_out[5]
    DIRECTION OUTPUT ;
    USE SIGNAL ;
    ANTENNADIFFAREA 1.182800 ;
    PORT
      LAYER Metal2 ;
        RECT 573.440 0.000 574.000 0.560 ;
    END
  END t0_out[5]
  PIN t0_out[60]
    DIRECTION OUTPUT ;
    USE SIGNAL ;
    ANTENNADIFFAREA 1.182800 ;
    PORT
      LAYER Metal3 ;
        RECT 849.440 608.160 850.000 608.720 ;
    END
  END t0_out[60]
  PIN t0_out[61]
    DIRECTION OUTPUT ;
    USE SIGNAL ;
    ANTENNADIFFAREA 1.182800 ;
    PORT
      LAYER Metal3 ;
        RECT 849.440 556.640 850.000 557.200 ;
    END
  END t0_out[61]
  PIN t0_out[62]
    DIRECTION OUTPUT ;
    USE SIGNAL ;
    ANTENNADIFFAREA 1.182800 ;
    PORT
      LAYER Metal3 ;
        RECT 849.440 548.800 850.000 549.360 ;
    END
  END t0_out[62]
  PIN t0_out[63]
    DIRECTION OUTPUT ;
    USE SIGNAL ;
    ANTENNADIFFAREA 1.182800 ;
    PORT
      LAYER Metal3 ;
        RECT 849.440 506.240 850.000 506.800 ;
    END
  END t0_out[63]
  PIN t0_out[6]
    DIRECTION OUTPUT ;
    USE SIGNAL ;
    ANTENNADIFFAREA 1.182800 ;
    PORT
      LAYER Metal3 ;
        RECT 849.440 213.920 850.000 214.480 ;
    END
  END t0_out[6]
  PIN t0_out[7]
    DIRECTION OUTPUT ;
    USE SIGNAL ;
    ANTENNADIFFAREA 1.182800 ;
    PORT
      LAYER Metal3 ;
        RECT 849.440 160.160 850.000 160.720 ;
    END
  END t0_out[7]
  PIN t0_out[8]
    DIRECTION OUTPUT ;
    USE SIGNAL ;
    ANTENNADIFFAREA 1.182800 ;
    PORT
      LAYER Metal3 ;
        RECT 849.440 346.080 850.000 346.640 ;
    END
  END t0_out[8]
  PIN t0_out[9]
    DIRECTION OUTPUT ;
    USE SIGNAL ;
    ANTENNADIFFAREA 1.182800 ;
    PORT
      LAYER Metal3 ;
        RECT 849.440 415.520 850.000 416.080 ;
    END
  END t0_out[9]
  PIN t1_out[0]
    DIRECTION OUTPUT ;
    USE SIGNAL ;
    ANTENNADIFFAREA 1.182800 ;
    PORT
      LAYER Metal3 ;
        RECT 849.440 355.040 850.000 355.600 ;
    END
  END t1_out[0]
  PIN t1_out[10]
    DIRECTION OUTPUT ;
    USE SIGNAL ;
    ANTENNADIFFAREA 1.182800 ;
    PORT
      LAYER Metal3 ;
        RECT 849.440 356.160 850.000 356.720 ;
    END
  END t1_out[10]
  PIN t1_out[11]
    DIRECTION OUTPUT ;
    USE SIGNAL ;
    ANTENNADIFFAREA 1.182800 ;
    PORT
      LAYER Metal3 ;
        RECT 849.440 221.760 850.000 222.320 ;
    END
  END t1_out[11]
  PIN t1_out[12]
    DIRECTION OUTPUT ;
    USE SIGNAL ;
    ANTENNADIFFAREA 1.182800 ;
    PORT
      LAYER Metal3 ;
        RECT 849.440 304.640 850.000 305.200 ;
    END
  END t1_out[12]
  PIN t1_out[13]
    DIRECTION OUTPUT ;
    USE SIGNAL ;
    ANTENNADIFFAREA 1.182800 ;
    PORT
      LAYER Metal3 ;
        RECT 849.440 344.960 850.000 345.520 ;
    END
  END t1_out[13]
  PIN t1_out[14]
    DIRECTION OUTPUT ;
    USE SIGNAL ;
    ANTENNADIFFAREA 1.182800 ;
    PORT
      LAYER Metal3 ;
        RECT 849.440 417.760 850.000 418.320 ;
    END
  END t1_out[14]
  PIN t1_out[15]
    DIRECTION OUTPUT ;
    USE SIGNAL ;
    ANTENNADIFFAREA 1.182800 ;
    PORT
      LAYER Metal3 ;
        RECT 849.440 528.640 850.000 529.200 ;
    END
  END t1_out[15]
  PIN t1_out[16]
    DIRECTION OUTPUT ;
    USE SIGNAL ;
    ANTENNADIFFAREA 1.182800 ;
    PORT
      LAYER Metal2 ;
        RECT 441.280 0.000 441.840 0.560 ;
    END
  END t1_out[16]
  PIN t1_out[17]
    DIRECTION OUTPUT ;
    USE SIGNAL ;
    ANTENNADIFFAREA 1.182800 ;
    PORT
      LAYER Metal2 ;
        RECT 348.320 0.000 348.880 0.560 ;
    END
  END t1_out[17]
  PIN t1_out[18]
    DIRECTION OUTPUT ;
    USE SIGNAL ;
    ANTENNADIFFAREA 1.182800 ;
    PORT
      LAYER Metal2 ;
        RECT 452.480 0.000 453.040 0.560 ;
    END
  END t1_out[18]
  PIN t1_out[19]
    DIRECTION OUTPUT ;
    USE SIGNAL ;
    ANTENNADIFFAREA 1.182800 ;
    PORT
      LAYER Metal2 ;
        RECT 404.320 0.000 404.880 0.560 ;
    END
  END t1_out[19]
  PIN t1_out[1]
    DIRECTION OUTPUT ;
    USE SIGNAL ;
    ANTENNADIFFAREA 1.182800 ;
    PORT
      LAYER Metal3 ;
        RECT 849.440 325.920 850.000 326.480 ;
    END
  END t1_out[1]
  PIN t1_out[20]
    DIRECTION OUTPUT ;
    USE SIGNAL ;
    ANTENNADIFFAREA 1.182800 ;
    PORT
      LAYER Metal2 ;
        RECT 504.000 0.000 504.560 0.560 ;
    END
  END t1_out[20]
  PIN t1_out[21]
    DIRECTION OUTPUT ;
    USE SIGNAL ;
    ANTENNADIFFAREA 1.182800 ;
    PORT
      LAYER Metal3 ;
        RECT 849.440 332.640 850.000 333.200 ;
    END
  END t1_out[21]
  PIN t1_out[22]
    DIRECTION OUTPUT ;
    USE SIGNAL ;
    ANTENNADIFFAREA 1.182800 ;
    PORT
      LAYER Metal2 ;
        RECT 352.800 0.000 353.360 0.560 ;
    END
  END t1_out[22]
  PIN t1_out[23]
    DIRECTION OUTPUT ;
    USE SIGNAL ;
    ANTENNADIFFAREA 1.182800 ;
    PORT
      LAYER Metal2 ;
        RECT 426.720 0.000 427.280 0.560 ;
    END
  END t1_out[23]
  PIN t1_out[24]
    DIRECTION OUTPUT ;
    USE SIGNAL ;
    ANTENNADIFFAREA 1.182800 ;
    PORT
      LAYER Metal2 ;
        RECT 350.560 0.000 351.120 0.560 ;
    END
  END t1_out[24]
  PIN t1_out[25]
    DIRECTION OUTPUT ;
    USE SIGNAL ;
    ANTENNADIFFAREA 1.182800 ;
    PORT
      LAYER Metal2 ;
        RECT 313.600 0.000 314.160 0.560 ;
    END
  END t1_out[25]
  PIN t1_out[26]
    DIRECTION OUTPUT ;
    USE SIGNAL ;
    ANTENNADIFFAREA 1.182800 ;
    PORT
      LAYER Metal3 ;
        RECT 0.000 340.480 0.560 341.040 ;
    END
  END t1_out[26]
  PIN t1_out[27]
    DIRECTION OUTPUT ;
    USE SIGNAL ;
    ANTENNADIFFAREA 1.182800 ;
    PORT
      LAYER Metal3 ;
        RECT 0.000 325.920 0.560 326.480 ;
    END
  END t1_out[27]
  PIN t1_out[28]
    DIRECTION OUTPUT ;
    USE SIGNAL ;
    ANTENNADIFFAREA 1.182800 ;
    PORT
      LAYER Metal3 ;
        RECT 0.000 232.960 0.560 233.520 ;
    END
  END t1_out[28]
  PIN t1_out[29]
    DIRECTION OUTPUT ;
    USE SIGNAL ;
    ANTENNADIFFAREA 1.182800 ;
    PORT
      LAYER Metal3 ;
        RECT 0.000 231.840 0.560 232.400 ;
    END
  END t1_out[29]
  PIN t1_out[2]
    DIRECTION OUTPUT ;
    USE SIGNAL ;
    ANTENNADIFFAREA 1.182800 ;
    PORT
      LAYER Metal2 ;
        RECT 509.600 0.000 510.160 0.560 ;
    END
  END t1_out[2]
  PIN t1_out[30]
    DIRECTION OUTPUT ;
    USE SIGNAL ;
    ANTENNADIFFAREA 1.182800 ;
    PORT
      LAYER Metal2 ;
        RECT 314.720 0.000 315.280 0.560 ;
    END
  END t1_out[30]
  PIN t1_out[31]
    DIRECTION OUTPUT ;
    USE SIGNAL ;
    ANTENNADIFFAREA 1.182800 ;
    PORT
      LAYER Metal3 ;
        RECT 849.440 348.320 850.000 348.880 ;
    END
  END t1_out[31]
  PIN t1_out[32]
    DIRECTION OUTPUT ;
    USE SIGNAL ;
    ANTENNADIFFAREA 1.182800 ;
    PORT
      LAYER Metal2 ;
        RECT 411.040 849.440 411.600 850.000 ;
    END
  END t1_out[32]
  PIN t1_out[33]
    DIRECTION OUTPUT ;
    USE SIGNAL ;
    ANTENNADIFFAREA 1.182800 ;
    PORT
      LAYER Metal2 ;
        RECT 283.360 849.440 283.920 850.000 ;
    END
  END t1_out[33]
  PIN t1_out[34]
    DIRECTION OUTPUT ;
    USE SIGNAL ;
    ANTENNADIFFAREA 1.182800 ;
    PORT
      LAYER Metal3 ;
        RECT 0.000 396.480 0.560 397.040 ;
    END
  END t1_out[34]
  PIN t1_out[35]
    DIRECTION OUTPUT ;
    USE SIGNAL ;
    ANTENNADIFFAREA 1.182800 ;
    PORT
      LAYER Metal3 ;
        RECT 0.000 333.760 0.560 334.320 ;
    END
  END t1_out[35]
  PIN t1_out[36]
    DIRECTION OUTPUT ;
    USE SIGNAL ;
    ANTENNADIFFAREA 1.182800 ;
    PORT
      LAYER Metal3 ;
        RECT 0.000 383.040 0.560 383.600 ;
    END
  END t1_out[36]
  PIN t1_out[37]
    DIRECTION OUTPUT ;
    USE SIGNAL ;
    ANTENNADIFFAREA 1.182800 ;
    PORT
      LAYER Metal3 ;
        RECT 0.000 493.920 0.560 494.480 ;
    END
  END t1_out[37]
  PIN t1_out[38]
    DIRECTION OUTPUT ;
    USE SIGNAL ;
    ANTENNADIFFAREA 1.182800 ;
    PORT
      LAYER Metal3 ;
        RECT 0.000 491.680 0.560 492.240 ;
    END
  END t1_out[38]
  PIN t1_out[39]
    DIRECTION OUTPUT ;
    USE SIGNAL ;
    ANTENNADIFFAREA 1.182800 ;
    PORT
      LAYER Metal3 ;
        RECT 0.000 495.040 0.560 495.600 ;
    END
  END t1_out[39]
  PIN t1_out[3]
    DIRECTION OUTPUT ;
    USE SIGNAL ;
    ANTENNADIFFAREA 1.182800 ;
    PORT
      LAYER Metal3 ;
        RECT 849.440 191.520 850.000 192.080 ;
    END
  END t1_out[3]
  PIN t1_out[40]
    DIRECTION OUTPUT ;
    USE SIGNAL ;
    ANTENNADIFFAREA 1.182800 ;
    PORT
      LAYER Metal2 ;
        RECT 353.920 849.440 354.480 850.000 ;
    END
  END t1_out[40]
  PIN t1_out[41]
    DIRECTION OUTPUT ;
    USE SIGNAL ;
    ANTENNADIFFAREA 1.182800 ;
    PORT
      LAYER Metal3 ;
        RECT 0.000 535.360 0.560 535.920 ;
    END
  END t1_out[41]
  PIN t1_out[42]
    DIRECTION OUTPUT ;
    USE SIGNAL ;
    ANTENNADIFFAREA 1.182800 ;
    PORT
      LAYER Metal2 ;
        RECT 301.280 849.440 301.840 850.000 ;
    END
  END t1_out[42]
  PIN t1_out[43]
    DIRECTION OUTPUT ;
    USE SIGNAL ;
    ANTENNADIFFAREA 1.182800 ;
    PORT
      LAYER Metal2 ;
        RECT 399.840 849.440 400.400 850.000 ;
    END
  END t1_out[43]
  PIN t1_out[44]
    DIRECTION OUTPUT ;
    USE SIGNAL ;
    ANTENNADIFFAREA 1.182800 ;
    PORT
      LAYER Metal3 ;
        RECT 0.000 647.360 0.560 647.920 ;
    END
  END t1_out[44]
  PIN t1_out[45]
    DIRECTION OUTPUT ;
    USE SIGNAL ;
    ANTENNADIFFAREA 1.182800 ;
    PORT
      LAYER Metal3 ;
        RECT 0.000 607.040 0.560 607.600 ;
    END
  END t1_out[45]
  PIN t1_out[46]
    DIRECTION OUTPUT ;
    USE SIGNAL ;
    ANTENNADIFFAREA 1.182800 ;
    PORT
      LAYER Metal2 ;
        RECT 295.680 849.440 296.240 850.000 ;
    END
  END t1_out[46]
  PIN t1_out[47]
    DIRECTION OUTPUT ;
    USE SIGNAL ;
    ANTENNADIFFAREA 1.182800 ;
    PORT
      LAYER Metal3 ;
        RECT 0.000 572.320 0.560 572.880 ;
    END
  END t1_out[47]
  PIN t1_out[48]
    DIRECTION OUTPUT ;
    USE SIGNAL ;
    ANTENNADIFFAREA 1.182800 ;
    PORT
      LAYER Metal2 ;
        RECT 417.760 849.440 418.320 850.000 ;
    END
  END t1_out[48]
  PIN t1_out[49]
    DIRECTION OUTPUT ;
    USE SIGNAL ;
    ANTENNADIFFAREA 1.182800 ;
    PORT
      LAYER Metal2 ;
        RECT 237.440 849.440 238.000 850.000 ;
    END
  END t1_out[49]
  PIN t1_out[4]
    DIRECTION OUTPUT ;
    USE SIGNAL ;
    ANTENNADIFFAREA 1.182800 ;
    PORT
      LAYER Metal3 ;
        RECT 849.440 336.000 850.000 336.560 ;
    END
  END t1_out[4]
  PIN t1_out[50]
    DIRECTION OUTPUT ;
    USE SIGNAL ;
    ANTENNADIFFAREA 1.182800 ;
    PORT
      LAYER Metal2 ;
        RECT 405.440 849.440 406.000 850.000 ;
    END
  END t1_out[50]
  PIN t1_out[51]
    DIRECTION OUTPUT ;
    USE SIGNAL ;
    ANTENNADIFFAREA 1.182800 ;
    PORT
      LAYER Metal2 ;
        RECT 225.120 849.440 225.680 850.000 ;
    END
  END t1_out[51]
  PIN t1_out[52]
    DIRECTION OUTPUT ;
    USE SIGNAL ;
    ANTENNADIFFAREA 1.182800 ;
    PORT
      LAYER Metal2 ;
        RECT 398.720 849.440 399.280 850.000 ;
    END
  END t1_out[52]
  PIN t1_out[53]
    DIRECTION OUTPUT ;
    USE SIGNAL ;
    ANTENNADIFFAREA 1.182800 ;
    PORT
      LAYER Metal2 ;
        RECT 443.520 849.440 444.080 850.000 ;
    END
  END t1_out[53]
  PIN t1_out[54]
    DIRECTION OUTPUT ;
    USE SIGNAL ;
    ANTENNADIFFAREA 1.182800 ;
    PORT
      LAYER Metal2 ;
        RECT 480.480 849.440 481.040 850.000 ;
    END
  END t1_out[54]
  PIN t1_out[55]
    DIRECTION OUTPUT ;
    USE SIGNAL ;
    ANTENNADIFFAREA 1.182800 ;
    PORT
      LAYER Metal2 ;
        RECT 407.680 849.440 408.240 850.000 ;
    END
  END t1_out[55]
  PIN t1_out[56]
    DIRECTION OUTPUT ;
    USE SIGNAL ;
    ANTENNADIFFAREA 1.182800 ;
    PORT
      LAYER Metal2 ;
        RECT 451.360 849.440 451.920 850.000 ;
    END
  END t1_out[56]
  PIN t1_out[57]
    DIRECTION OUTPUT ;
    USE SIGNAL ;
    ANTENNADIFFAREA 1.182800 ;
    PORT
      LAYER Metal2 ;
        RECT 511.840 849.440 512.400 850.000 ;
    END
  END t1_out[57]
  PIN t1_out[58]
    DIRECTION OUTPUT ;
    USE SIGNAL ;
    ANTENNADIFFAREA 1.182800 ;
    PORT
      LAYER Metal2 ;
        RECT 519.680 849.440 520.240 850.000 ;
    END
  END t1_out[58]
  PIN t1_out[59]
    DIRECTION OUTPUT ;
    USE SIGNAL ;
    ANTENNADIFFAREA 1.182800 ;
    PORT
      LAYER Metal2 ;
        RECT 552.160 849.440 552.720 850.000 ;
    END
  END t1_out[59]
  PIN t1_out[5]
    DIRECTION OUTPUT ;
    USE SIGNAL ;
    ANTENNADIFFAREA 1.182800 ;
    PORT
      LAYER Metal2 ;
        RECT 564.480 0.000 565.040 0.560 ;
    END
  END t1_out[5]
  PIN t1_out[60]
    DIRECTION OUTPUT ;
    USE SIGNAL ;
    ANTENNADIFFAREA 1.182800 ;
    PORT
      LAYER Metal2 ;
        RECT 650.720 849.440 651.280 850.000 ;
    END
  END t1_out[60]
  PIN t1_out[61]
    DIRECTION OUTPUT ;
    USE SIGNAL ;
    ANTENNADIFFAREA 1.182800 ;
    PORT
      LAYER Metal3 ;
        RECT 849.440 546.560 850.000 547.120 ;
    END
  END t1_out[61]
  PIN t1_out[62]
    DIRECTION OUTPUT ;
    USE SIGNAL ;
    ANTENNADIFFAREA 1.182800 ;
    PORT
      LAYER Metal3 ;
        RECT 849.440 560.000 850.000 560.560 ;
    END
  END t1_out[62]
  PIN t1_out[63]
    DIRECTION OUTPUT ;
    USE SIGNAL ;
    ANTENNADIFFAREA 1.182800 ;
    PORT
      LAYER Metal3 ;
        RECT 849.440 497.280 850.000 497.840 ;
    END
  END t1_out[63]
  PIN t1_out[6]
    DIRECTION OUTPUT ;
    USE SIGNAL ;
    ANTENNADIFFAREA 1.182800 ;
    PORT
      LAYER Metal3 ;
        RECT 849.440 249.760 850.000 250.320 ;
    END
  END t1_out[6]
  PIN t1_out[7]
    DIRECTION OUTPUT ;
    USE SIGNAL ;
    ANTENNADIFFAREA 1.182800 ;
    PORT
      LAYER Metal2 ;
        RECT 604.800 0.000 605.360 0.560 ;
    END
  END t1_out[7]
  PIN t1_out[8]
    DIRECTION OUTPUT ;
    USE SIGNAL ;
    ANTENNADIFFAREA 1.182800 ;
    PORT
      LAYER Metal3 ;
        RECT 849.440 322.560 850.000 323.120 ;
    END
  END t1_out[8]
  PIN t1_out[9]
    DIRECTION OUTPUT ;
    USE SIGNAL ;
    ANTENNADIFFAREA 1.182800 ;
    PORT
      LAYER Metal2 ;
        RECT 612.640 0.000 613.200 0.560 ;
    END
  END t1_out[9]
  PIN tag0_in[0]
    DIRECTION INPUT ;
    USE SIGNAL ;
    ANTENNAGATEAREA 1.102000 ;
    PORT
      LAYER Metal2 ;
        RECT 507.360 0.000 507.920 0.560 ;
    END
  END tag0_in[0]
  PIN tag0_in[10]
    DIRECTION INPUT ;
    USE SIGNAL ;
    ANTENNAGATEAREA 1.102000 ;
    PORT
      LAYER Metal3 ;
        RECT 849.440 358.400 850.000 358.960 ;
    END
  END tag0_in[10]
  PIN tag0_in[11]
    DIRECTION INPUT ;
    USE SIGNAL ;
    ANTENNAGATEAREA 1.102000 ;
    PORT
      LAYER Metal3 ;
        RECT 849.440 303.520 850.000 304.080 ;
    END
  END tag0_in[11]
  PIN tag0_in[12]
    DIRECTION INPUT ;
    USE SIGNAL ;
    ANTENNAGATEAREA 1.102000 ;
    PORT
      LAYER Metal3 ;
        RECT 849.440 294.560 850.000 295.120 ;
    END
  END tag0_in[12]
  PIN tag0_in[13]
    DIRECTION INPUT ;
    USE SIGNAL ;
    ANTENNAGATEAREA 1.102000 ;
    PORT
      LAYER Metal3 ;
        RECT 849.440 353.920 850.000 354.480 ;
    END
  END tag0_in[13]
  PIN tag0_in[14]
    DIRECTION INPUT ;
    USE SIGNAL ;
    ANTENNAGATEAREA 1.102000 ;
    PORT
      LAYER Metal3 ;
        RECT 849.440 283.360 850.000 283.920 ;
    END
  END tag0_in[14]
  PIN tag0_in[15]
    DIRECTION INPUT ;
    USE SIGNAL ;
    ANTENNAGATEAREA 1.102000 ;
    PORT
      LAYER Metal3 ;
        RECT 849.440 478.240 850.000 478.800 ;
    END
  END tag0_in[15]
  PIN tag0_in[16]
    DIRECTION INPUT ;
    USE SIGNAL ;
    ANTENNAGATEAREA 1.102000 ;
    PORT
      LAYER Metal3 ;
        RECT 849.440 331.520 850.000 332.080 ;
    END
  END tag0_in[16]
  PIN tag0_in[17]
    DIRECTION INPUT ;
    USE SIGNAL ;
    ANTENNAGATEAREA 1.102000 ;
    PORT
      LAYER Metal2 ;
        RECT 590.240 0.000 590.800 0.560 ;
    END
  END tag0_in[17]
  PIN tag0_in[18]
    DIRECTION INPUT ;
    USE SIGNAL ;
    ANTENNAGATEAREA 1.102000 ;
    PORT
      LAYER Metal2 ;
        RECT 543.200 0.000 543.760 0.560 ;
    END
  END tag0_in[18]
  PIN tag0_in[19]
    DIRECTION INPUT ;
    USE SIGNAL ;
    ANTENNAGATEAREA 1.102000 ;
    PORT
      LAYER Metal2 ;
        RECT 591.360 0.000 591.920 0.560 ;
    END
  END tag0_in[19]
  PIN tag0_in[1]
    DIRECTION INPUT ;
    USE SIGNAL ;
    ANTENNAGATEAREA 1.102000 ;
    PORT
      LAYER Metal2 ;
        RECT 549.920 0.000 550.480 0.560 ;
    END
  END tag0_in[1]
  PIN tag0_in[20]
    DIRECTION INPUT ;
    USE SIGNAL ;
    ANTENNAGATEAREA 1.102000 ;
    PORT
      LAYER Metal3 ;
        RECT 849.440 228.480 850.000 229.040 ;
    END
  END tag0_in[20]
  PIN tag0_in[21]
    DIRECTION INPUT ;
    USE SIGNAL ;
    ANTENNAGATEAREA 1.102000 ;
    PORT
      LAYER Metal2 ;
        RECT 498.400 0.000 498.960 0.560 ;
    END
  END tag0_in[21]
  PIN tag0_in[22]
    DIRECTION INPUT ;
    USE SIGNAL ;
    ANTENNAGATEAREA 1.102000 ;
    PORT
      LAYER Metal2 ;
        RECT 338.240 0.000 338.800 0.560 ;
    END
  END tag0_in[22]
  PIN tag0_in[23]
    DIRECTION INPUT ;
    USE SIGNAL ;
    ANTENNAGATEAREA 1.102000 ;
    PORT
      LAYER Metal2 ;
        RECT 500.640 0.000 501.200 0.560 ;
    END
  END tag0_in[23]
  PIN tag0_in[24]
    DIRECTION INPUT ;
    USE SIGNAL ;
    ANTENNAGATEAREA 1.102000 ;
    PORT
      LAYER Metal3 ;
        RECT 849.440 342.720 850.000 343.280 ;
    END
  END tag0_in[24]
  PIN tag0_in[25]
    DIRECTION INPUT ;
    USE SIGNAL ;
    ANTENNAGATEAREA 1.102000 ;
    PORT
      LAYER Metal2 ;
        RECT 292.320 0.000 292.880 0.560 ;
    END
  END tag0_in[25]
  PIN tag0_in[26]
    DIRECTION INPUT ;
    USE SIGNAL ;
    ANTENNAGATEAREA 1.102000 ;
    PORT
      LAYER Metal3 ;
        RECT 0.000 301.280 0.560 301.840 ;
    END
  END tag0_in[26]
  PIN tag0_in[27]
    DIRECTION INPUT ;
    USE SIGNAL ;
    ANTENNAGATEAREA 1.102000 ;
    PORT
      LAYER Metal2 ;
        RECT 311.360 0.000 311.920 0.560 ;
    END
  END tag0_in[27]
  PIN tag0_in[28]
    DIRECTION INPUT ;
    USE SIGNAL ;
    ANTENNAGATEAREA 1.102000 ;
    PORT
      LAYER Metal3 ;
        RECT 0.000 294.560 0.560 295.120 ;
    END
  END tag0_in[28]
  PIN tag0_in[29]
    DIRECTION INPUT ;
    USE SIGNAL ;
    ANTENNAGATEAREA 1.102000 ;
    PORT
      LAYER Metal3 ;
        RECT 0.000 227.360 0.560 227.920 ;
    END
  END tag0_in[29]
  PIN tag0_in[2]
    DIRECTION INPUT ;
    USE SIGNAL ;
    ANTENNAGATEAREA 1.102000 ;
    PORT
      LAYER Metal2 ;
        RECT 553.280 0.000 553.840 0.560 ;
    END
  END tag0_in[2]
  PIN tag0_in[30]
    DIRECTION INPUT ;
    USE SIGNAL ;
    ANTENNAGATEAREA 1.102000 ;
    PORT
      LAYER Metal3 ;
        RECT 0.000 264.320 0.560 264.880 ;
    END
  END tag0_in[30]
  PIN tag0_in[31]
    DIRECTION INPUT ;
    USE SIGNAL ;
    ANTENNAGATEAREA 1.102000 ;
    PORT
      LAYER Metal2 ;
        RECT 392.000 0.000 392.560 0.560 ;
    END
  END tag0_in[31]
  PIN tag0_in[32]
    DIRECTION INPUT ;
    USE SIGNAL ;
    ANTENNAGATEAREA 1.102000 ;
    PORT
      LAYER Metal3 ;
        RECT 0.000 534.240 0.560 534.800 ;
    END
  END tag0_in[32]
  PIN tag0_in[33]
    DIRECTION INPUT ;
    USE SIGNAL ;
    ANTENNAGATEAREA 1.102000 ;
    PORT
      LAYER Metal3 ;
        RECT 0.000 389.760 0.560 390.320 ;
    END
  END tag0_in[33]
  PIN tag0_in[34]
    DIRECTION INPUT ;
    USE SIGNAL ;
    ANTENNAGATEAREA 1.102000 ;
    PORT
      LAYER Metal3 ;
        RECT 0.000 506.240 0.560 506.800 ;
    END
  END tag0_in[34]
  PIN tag0_in[35]
    DIRECTION INPUT ;
    USE SIGNAL ;
    ANTENNAGATEAREA 1.102000 ;
    PORT
      LAYER Metal3 ;
        RECT 0.000 337.120 0.560 337.680 ;
    END
  END tag0_in[35]
  PIN tag0_in[36]
    DIRECTION INPUT ;
    USE SIGNAL ;
    ANTENNAGATEAREA 1.102000 ;
    PORT
      LAYER Metal3 ;
        RECT 0.000 371.840 0.560 372.400 ;
    END
  END tag0_in[36]
  PIN tag0_in[37]
    DIRECTION INPUT ;
    USE SIGNAL ;
    ANTENNAGATEAREA 1.102000 ;
    PORT
      LAYER Metal3 ;
        RECT 0.000 486.080 0.560 486.640 ;
    END
  END tag0_in[37]
  PIN tag0_in[38]
    DIRECTION INPUT ;
    USE SIGNAL ;
    ANTENNAGATEAREA 1.102000 ;
    PORT
      LAYER Metal3 ;
        RECT 0.000 492.800 0.560 493.360 ;
    END
  END tag0_in[38]
  PIN tag0_in[39]
    DIRECTION INPUT ;
    USE SIGNAL ;
    ANTENNAGATEAREA 1.102000 ;
    PORT
      LAYER Metal3 ;
        RECT 0.000 487.200 0.560 487.760 ;
    END
  END tag0_in[39]
  PIN tag0_in[3]
    DIRECTION INPUT ;
    USE SIGNAL ;
    ANTENNAGATEAREA 1.102000 ;
    PORT
      LAYER Metal3 ;
        RECT 849.440 229.600 850.000 230.160 ;
    END
  END tag0_in[3]
  PIN tag0_in[40]
    DIRECTION INPUT ;
    USE SIGNAL ;
    ANTENNAGATEAREA 1.102000 ;
    PORT
      LAYER Metal2 ;
        RECT 315.840 849.440 316.400 850.000 ;
    END
  END tag0_in[40]
  PIN tag0_in[41]
    DIRECTION INPUT ;
    USE SIGNAL ;
    ANTENNAGATEAREA 1.102000 ;
    PORT
      LAYER Metal3 ;
        RECT 0.000 544.320 0.560 544.880 ;
    END
  END tag0_in[41]
  PIN tag0_in[42]
    DIRECTION INPUT ;
    USE SIGNAL ;
    ANTENNAGATEAREA 1.102000 ;
    PORT
      LAYER Metal2 ;
        RECT 297.920 849.440 298.480 850.000 ;
    END
  END tag0_in[42]
  PIN tag0_in[43]
    DIRECTION INPUT ;
    USE SIGNAL ;
    ANTENNAGATEAREA 1.102000 ;
    PORT
      LAYER Metal2 ;
        RECT 347.200 849.440 347.760 850.000 ;
    END
  END tag0_in[43]
  PIN tag0_in[44]
    DIRECTION INPUT ;
    USE SIGNAL ;
    ANTENNAGATEAREA 1.102000 ;
    PORT
      LAYER Metal2 ;
        RECT 211.680 849.440 212.240 850.000 ;
    END
  END tag0_in[44]
  PIN tag0_in[45]
    DIRECTION INPUT ;
    USE SIGNAL ;
    ANTENNAGATEAREA 1.102000 ;
    PORT
      LAYER Metal3 ;
        RECT 0.000 580.160 0.560 580.720 ;
    END
  END tag0_in[45]
  PIN tag0_in[46]
    DIRECTION INPUT ;
    USE SIGNAL ;
    ANTENNAGATEAREA 1.102000 ;
    PORT
      LAYER Metal2 ;
        RECT 284.480 849.440 285.040 850.000 ;
    END
  END tag0_in[46]
  PIN tag0_in[47]
    DIRECTION INPUT ;
    USE SIGNAL ;
    ANTENNAGATEAREA 1.102000 ;
    PORT
      LAYER Metal3 ;
        RECT 0.000 574.560 0.560 575.120 ;
    END
  END tag0_in[47]
  PIN tag0_in[48]
    DIRECTION INPUT ;
    USE SIGNAL ;
    ANTENNAGATEAREA 1.102000 ;
    PORT
      LAYER Metal2 ;
        RECT 425.600 849.440 426.160 850.000 ;
    END
  END tag0_in[48]
  PIN tag0_in[49]
    DIRECTION INPUT ;
    USE SIGNAL ;
    ANTENNAGATEAREA 1.102000 ;
    PORT
      LAYER Metal2 ;
        RECT 224.000 849.440 224.560 850.000 ;
    END
  END tag0_in[49]
  PIN tag0_in[4]
    DIRECTION INPUT ;
    USE SIGNAL ;
    ANTENNAGATEAREA 1.102000 ;
    PORT
      LAYER Metal2 ;
        RECT 610.400 0.000 610.960 0.560 ;
    END
  END tag0_in[4]
  PIN tag0_in[50]
    DIRECTION INPUT ;
    USE SIGNAL ;
    ANTENNAGATEAREA 1.102000 ;
    PORT
      LAYER Metal2 ;
        RECT 337.120 849.440 337.680 850.000 ;
    END
  END tag0_in[50]
  PIN tag0_in[51]
    DIRECTION INPUT ;
    USE SIGNAL ;
    ANTENNAGATEAREA 1.102000 ;
    PORT
      LAYER Metal2 ;
        RECT 221.760 849.440 222.320 850.000 ;
    END
  END tag0_in[51]
  PIN tag0_in[52]
    DIRECTION INPUT ;
    USE SIGNAL ;
    ANTENNAGATEAREA 1.102000 ;
    PORT
      LAYER Metal2 ;
        RECT 222.880 849.440 223.440 850.000 ;
    END
  END tag0_in[52]
  PIN tag0_in[53]
    DIRECTION INPUT ;
    USE SIGNAL ;
    ANTENNAGATEAREA 1.102000 ;
    PORT
      LAYER Metal2 ;
        RECT 367.360 849.440 367.920 850.000 ;
    END
  END tag0_in[53]
  PIN tag0_in[54]
    DIRECTION INPUT ;
    USE SIGNAL ;
    ANTENNAGATEAREA 1.102000 ;
    PORT
      LAYER Metal2 ;
        RECT 455.840 849.440 456.400 850.000 ;
    END
  END tag0_in[54]
  PIN tag0_in[55]
    DIRECTION INPUT ;
    USE SIGNAL ;
    ANTENNAGATEAREA 1.102000 ;
    PORT
      LAYER Metal2 ;
        RECT 365.120 849.440 365.680 850.000 ;
    END
  END tag0_in[55]
  PIN tag0_in[56]
    DIRECTION INPUT ;
    USE SIGNAL ;
    ANTENNAGATEAREA 1.102000 ;
    PORT
      LAYER Metal3 ;
        RECT 0.000 575.680 0.560 576.240 ;
    END
  END tag0_in[56]
  PIN tag0_in[57]
    DIRECTION INPUT ;
    USE SIGNAL ;
    ANTENNAGATEAREA 1.102000 ;
    PORT
      LAYER Metal2 ;
        RECT 514.080 849.440 514.640 850.000 ;
    END
  END tag0_in[57]
  PIN tag0_in[58]
    DIRECTION INPUT ;
    USE SIGNAL ;
    ANTENNAGATEAREA 1.102000 ;
    PORT
      LAYER Metal3 ;
        RECT 849.440 523.040 850.000 523.600 ;
    END
  END tag0_in[58]
  PIN tag0_in[59]
    DIRECTION INPUT ;
    USE SIGNAL ;
    ANTENNAGATEAREA 1.102000 ;
    PORT
      LAYER Metal2 ;
        RECT 537.600 849.440 538.160 850.000 ;
    END
  END tag0_in[59]
  PIN tag0_in[5]
    DIRECTION INPUT ;
    USE SIGNAL ;
    ANTENNAGATEAREA 1.102000 ;
    PORT
      LAYER Metal2 ;
        RECT 556.640 0.000 557.200 0.560 ;
    END
  END tag0_in[5]
  PIN tag0_in[60]
    DIRECTION INPUT ;
    USE SIGNAL ;
    ANTENNAGATEAREA 1.102000 ;
    PORT
      LAYER Metal3 ;
        RECT 849.440 602.560 850.000 603.120 ;
    END
  END tag0_in[60]
  PIN tag0_in[61]
    DIRECTION INPUT ;
    USE SIGNAL ;
    ANTENNAGATEAREA 1.102000 ;
    PORT
      LAYER Metal3 ;
        RECT 849.440 558.880 850.000 559.440 ;
    END
  END tag0_in[61]
  PIN tag0_in[62]
    DIRECTION INPUT ;
    USE SIGNAL ;
    ANTENNAGATEAREA 1.102000 ;
    PORT
      LAYER Metal3 ;
        RECT 849.440 549.920 850.000 550.480 ;
    END
  END tag0_in[62]
  PIN tag0_in[63]
    DIRECTION INPUT ;
    USE SIGNAL ;
    ANTENNAGATEAREA 1.102000 ;
    PORT
      LAYER Metal3 ;
        RECT 849.440 501.760 850.000 502.320 ;
    END
  END tag0_in[63]
  PIN tag0_in[6]
    DIRECTION INPUT ;
    USE SIGNAL ;
    ANTENNAGATEAREA 1.102000 ;
    PORT
      LAYER Metal3 ;
        RECT 849.440 226.240 850.000 226.800 ;
    END
  END tag0_in[6]
  PIN tag0_in[7]
    DIRECTION INPUT ;
    USE SIGNAL ;
    ANTENNAGATEAREA 1.102000 ;
    PORT
      LAYER Metal2 ;
        RECT 568.960 0.000 569.520 0.560 ;
    END
  END tag0_in[7]
  PIN tag0_in[8]
    DIRECTION INPUT ;
    USE SIGNAL ;
    ANTENNAGATEAREA 1.102000 ;
    PORT
      LAYER Metal3 ;
        RECT 849.440 352.800 850.000 353.360 ;
    END
  END tag0_in[8]
  PIN tag0_in[9]
    DIRECTION INPUT ;
    USE SIGNAL ;
    ANTENNAGATEAREA 1.102000 ;
    PORT
      LAYER Metal3 ;
        RECT 849.440 408.800 850.000 409.360 ;
    END
  END tag0_in[9]
  PIN tag1_in[0]
    DIRECTION INPUT ;
    USE SIGNAL ;
    ANTENNAGATEAREA 1.102000 ;
    PORT
      LAYER Metal3 ;
        RECT 849.440 334.880 850.000 335.440 ;
    END
  END tag1_in[0]
  PIN tag1_in[10]
    DIRECTION INPUT ;
    USE SIGNAL ;
    ANTENNAGATEAREA 1.102000 ;
    PORT
      LAYER Metal3 ;
        RECT 849.440 351.680 850.000 352.240 ;
    END
  END tag1_in[10]
  PIN tag1_in[11]
    DIRECTION INPUT ;
    USE SIGNAL ;
    ANTENNAGATEAREA 1.102000 ;
    PORT
      LAYER Metal2 ;
        RECT 351.680 0.000 352.240 0.560 ;
    END
  END tag1_in[11]
  PIN tag1_in[12]
    DIRECTION INPUT ;
    USE SIGNAL ;
    ANTENNAGATEAREA 1.102000 ;
    PORT
      LAYER Metal2 ;
        RECT 431.200 0.000 431.760 0.560 ;
    END
  END tag1_in[12]
  PIN tag1_in[13]
    DIRECTION INPUT ;
    USE SIGNAL ;
    ANTENNAGATEAREA 1.102000 ;
    PORT
      LAYER Metal3 ;
        RECT 849.440 339.360 850.000 339.920 ;
    END
  END tag1_in[13]
  PIN tag1_in[14]
    DIRECTION INPUT ;
    USE SIGNAL ;
    ANTENNAGATEAREA 1.102000 ;
    PORT
      LAYER Metal2 ;
        RECT 428.960 0.000 429.520 0.560 ;
    END
  END tag1_in[14]
  PIN tag1_in[15]
    DIRECTION INPUT ;
    USE SIGNAL ;
    ANTENNAGATEAREA 1.102000 ;
    PORT
      LAYER Metal3 ;
        RECT 849.440 500.640 850.000 501.200 ;
    END
  END tag1_in[15]
  PIN tag1_in[16]
    DIRECTION INPUT ;
    USE SIGNAL ;
    ANTENNAGATEAREA 1.102000 ;
    PORT
      LAYER Metal2 ;
        RECT 437.920 0.000 438.480 0.560 ;
    END
  END tag1_in[16]
  PIN tag1_in[17]
    DIRECTION INPUT ;
    USE SIGNAL ;
    ANTENNAGATEAREA 1.102000 ;
    PORT
      LAYER Metal3 ;
        RECT 0.000 483.840 0.560 484.400 ;
    END
  END tag1_in[17]
  PIN tag1_in[18]
    DIRECTION INPUT ;
    USE SIGNAL ;
    ANTENNAGATEAREA 1.102000 ;
    PORT
      LAYER Metal2 ;
        RECT 442.400 0.000 442.960 0.560 ;
    END
  END tag1_in[18]
  PIN tag1_in[19]
    DIRECTION INPUT ;
    USE SIGNAL ;
    ANTENNAGATEAREA 1.102000 ;
    PORT
      LAYER Metal2 ;
        RECT 423.360 0.000 423.920 0.560 ;
    END
  END tag1_in[19]
  PIN tag1_in[1]
    DIRECTION INPUT ;
    USE SIGNAL ;
    ANTENNAGATEAREA 1.102000 ;
    PORT
      LAYER Metal3 ;
        RECT 849.440 329.280 850.000 329.840 ;
    END
  END tag1_in[1]
  PIN tag1_in[20]
    DIRECTION INPUT ;
    USE SIGNAL ;
    ANTENNAGATEAREA 1.102000 ;
    PORT
      LAYER Metal2 ;
        RECT 502.880 0.000 503.440 0.560 ;
    END
  END tag1_in[20]
  PIN tag1_in[21]
    DIRECTION INPUT ;
    USE SIGNAL ;
    ANTENNAGATEAREA 1.102000 ;
    PORT
      LAYER Metal2 ;
        RECT 440.160 0.000 440.720 0.560 ;
    END
  END tag1_in[21]
  PIN tag1_in[22]
    DIRECTION INPUT ;
    USE SIGNAL ;
    ANTENNAGATEAREA 1.102000 ;
    PORT
      LAYER Metal2 ;
        RECT 342.720 0.000 343.280 0.560 ;
    END
  END tag1_in[22]
  PIN tag1_in[23]
    DIRECTION INPUT ;
    USE SIGNAL ;
    ANTENNAGATEAREA 1.102000 ;
    PORT
      LAYER Metal2 ;
        RECT 421.120 0.000 421.680 0.560 ;
    END
  END tag1_in[23]
  PIN tag1_in[24]
    DIRECTION INPUT ;
    USE SIGNAL ;
    ANTENNAGATEAREA 1.102000 ;
    PORT
      LAYER Metal2 ;
        RECT 347.200 0.000 347.760 0.560 ;
    END
  END tag1_in[24]
  PIN tag1_in[25]
    DIRECTION INPUT ;
    USE SIGNAL ;
    ANTENNAGATEAREA 1.102000 ;
    PORT
      LAYER Metal2 ;
        RECT 310.240 0.000 310.800 0.560 ;
    END
  END tag1_in[25]
  PIN tag1_in[26]
    DIRECTION INPUT ;
    USE SIGNAL ;
    ANTENNAGATEAREA 1.102000 ;
    PORT
      LAYER Metal3 ;
        RECT 0.000 388.640 0.560 389.200 ;
    END
  END tag1_in[26]
  PIN tag1_in[27]
    DIRECTION INPUT ;
    USE SIGNAL ;
    ANTENNAGATEAREA 1.102000 ;
    PORT
      LAYER Metal3 ;
        RECT 849.440 327.040 850.000 327.600 ;
    END
  END tag1_in[27]
  PIN tag1_in[28]
    DIRECTION INPUT ;
    USE SIGNAL ;
    ANTENNAGATEAREA 1.102000 ;
    PORT
      LAYER Metal3 ;
        RECT 0.000 228.480 0.560 229.040 ;
    END
  END tag1_in[28]
  PIN tag1_in[29]
    DIRECTION INPUT ;
    USE SIGNAL ;
    ANTENNAGATEAREA 1.102000 ;
    PORT
      LAYER Metal3 ;
        RECT 0.000 230.720 0.560 231.280 ;
    END
  END tag1_in[29]
  PIN tag1_in[2]
    DIRECTION INPUT ;
    USE SIGNAL ;
    ANTENNAGATEAREA 1.102000 ;
    PORT
      LAYER Metal2 ;
        RECT 497.280 0.000 497.840 0.560 ;
    END
  END tag1_in[2]
  PIN tag1_in[30]
    DIRECTION INPUT ;
    USE SIGNAL ;
    ANTENNAGATEAREA 1.102000 ;
    PORT
      LAYER Metal2 ;
        RECT 312.480 0.000 313.040 0.560 ;
    END
  END tag1_in[30]
  PIN tag1_in[31]
    DIRECTION INPUT ;
    USE SIGNAL ;
    ANTENNAGATEAREA 1.102000 ;
    PORT
      LAYER Metal2 ;
        RECT 418.880 0.000 419.440 0.560 ;
    END
  END tag1_in[31]
  PIN tag1_in[32]
    DIRECTION INPUT ;
    USE SIGNAL ;
    ANTENNAGATEAREA 1.102000 ;
    PORT
      LAYER Metal2 ;
        RECT 403.200 849.440 403.760 850.000 ;
    END
  END tag1_in[32]
  PIN tag1_in[33]
    DIRECTION INPUT ;
    USE SIGNAL ;
    ANTENNAGATEAREA 1.102000 ;
    PORT
      LAYER Metal2 ;
        RECT 421.120 849.440 421.680 850.000 ;
    END
  END tag1_in[33]
  PIN tag1_in[34]
    DIRECTION INPUT ;
    USE SIGNAL ;
    ANTENNAGATEAREA 1.102000 ;
    PORT
      LAYER Metal3 ;
        RECT 0.000 426.720 0.560 427.280 ;
    END
  END tag1_in[34]
  PIN tag1_in[35]
    DIRECTION INPUT ;
    USE SIGNAL ;
    ANTENNAGATEAREA 1.102000 ;
    PORT
      LAYER Metal3 ;
        RECT 0.000 339.360 0.560 339.920 ;
    END
  END tag1_in[35]
  PIN tag1_in[36]
    DIRECTION INPUT ;
    USE SIGNAL ;
    ANTENNAGATEAREA 1.102000 ;
    PORT
      LAYER Metal3 ;
        RECT 0.000 387.520 0.560 388.080 ;
    END
  END tag1_in[36]
  PIN tag1_in[37]
    DIRECTION INPUT ;
    USE SIGNAL ;
    ANTENNAGATEAREA 1.102000 ;
    PORT
      LAYER Metal2 ;
        RECT 314.720 849.440 315.280 850.000 ;
    END
  END tag1_in[37]
  PIN tag1_in[38]
    DIRECTION INPUT ;
    USE SIGNAL ;
    ANTENNAGATEAREA 1.102000 ;
    PORT
      LAYER Metal3 ;
        RECT 0.000 571.200 0.560 571.760 ;
    END
  END tag1_in[38]
  PIN tag1_in[39]
    DIRECTION INPUT ;
    USE SIGNAL ;
    ANTENNAGATEAREA 1.102000 ;
    PORT
      LAYER Metal3 ;
        RECT 849.440 502.880 850.000 503.440 ;
    END
  END tag1_in[39]
  PIN tag1_in[3]
    DIRECTION INPUT ;
    USE SIGNAL ;
    ANTENNAGATEAREA 1.102000 ;
    PORT
      LAYER Metal2 ;
        RECT 647.360 0.000 647.920 0.560 ;
    END
  END tag1_in[3]
  PIN tag1_in[40]
    DIRECTION INPUT ;
    USE SIGNAL ;
    ANTENNAGATEAREA 0.741000 ;
    PORT
      LAYER Metal2 ;
        RECT 344.960 849.440 345.520 850.000 ;
    END
  END tag1_in[40]
  PIN tag1_in[41]
    DIRECTION INPUT ;
    USE SIGNAL ;
    ANTENNAGATEAREA 1.102000 ;
    PORT
      LAYER Metal3 ;
        RECT 0.000 537.600 0.560 538.160 ;
    END
  END tag1_in[41]
  PIN tag1_in[42]
    DIRECTION INPUT ;
    USE SIGNAL ;
    ANTENNAGATEAREA 1.102000 ;
    PORT
      LAYER Metal2 ;
        RECT 302.400 849.440 302.960 850.000 ;
    END
  END tag1_in[42]
  PIN tag1_in[43]
    DIRECTION INPUT ;
    USE SIGNAL ;
    ANTENNAGATEAREA 1.102000 ;
    PORT
      LAYER Metal2 ;
        RECT 497.280 849.440 497.840 850.000 ;
    END
  END tag1_in[43]
  PIN tag1_in[44]
    DIRECTION INPUT ;
    USE SIGNAL ;
    ANTENNAGATEAREA 1.102000 ;
    PORT
      LAYER Metal3 ;
        RECT 0.000 613.760 0.560 614.320 ;
    END
  END tag1_in[44]
  PIN tag1_in[45]
    DIRECTION INPUT ;
    USE SIGNAL ;
    ANTENNAGATEAREA 1.102000 ;
    PORT
      LAYER Metal3 ;
        RECT 0.000 604.800 0.560 605.360 ;
    END
  END tag1_in[45]
  PIN tag1_in[46]
    DIRECTION INPUT ;
    USE SIGNAL ;
    ANTENNAGATEAREA 1.102000 ;
    PORT
      LAYER Metal2 ;
        RECT 299.040 849.440 299.600 850.000 ;
    END
  END tag1_in[46]
  PIN tag1_in[47]
    DIRECTION INPUT ;
    USE SIGNAL ;
    ANTENNAGATEAREA 1.102000 ;
    PORT
      LAYER Metal3 ;
        RECT 0.000 573.440 0.560 574.000 ;
    END
  END tag1_in[47]
  PIN tag1_in[48]
    DIRECTION INPUT ;
    USE SIGNAL ;
    ANTENNAGATEAREA 1.102000 ;
    PORT
      LAYER Metal2 ;
        RECT 409.920 849.440 410.480 850.000 ;
    END
  END tag1_in[48]
  PIN tag1_in[49]
    DIRECTION INPUT ;
    USE SIGNAL ;
    ANTENNAGATEAREA 1.102000 ;
    PORT
      LAYER Metal2 ;
        RECT 238.560 849.440 239.120 850.000 ;
    END
  END tag1_in[49]
  PIN tag1_in[4]
    DIRECTION INPUT ;
    USE SIGNAL ;
    ANTENNAGATEAREA 1.102000 ;
    PORT
      LAYER Metal3 ;
        RECT 849.440 321.440 850.000 322.000 ;
    END
  END tag1_in[4]
  PIN tag1_in[50]
    DIRECTION INPUT ;
    USE SIGNAL ;
    ANTENNAGATEAREA 1.102000 ;
    PORT
      LAYER Metal2 ;
        RECT 400.960 849.440 401.520 850.000 ;
    END
  END tag1_in[50]
  PIN tag1_in[51]
    DIRECTION INPUT ;
    USE SIGNAL ;
    ANTENNAGATEAREA 1.102000 ;
    PORT
      LAYER Metal2 ;
        RECT 215.040 849.440 215.600 850.000 ;
    END
  END tag1_in[51]
  PIN tag1_in[52]
    DIRECTION INPUT ;
    USE SIGNAL ;
    ANTENNAGATEAREA 1.102000 ;
    PORT
      LAYER Metal2 ;
        RECT 413.280 849.440 413.840 850.000 ;
    END
  END tag1_in[52]
  PIN tag1_in[53]
    DIRECTION INPUT ;
    USE SIGNAL ;
    ANTENNAGATEAREA 1.102000 ;
    PORT
      LAYER Metal2 ;
        RECT 423.360 849.440 423.920 850.000 ;
    END
  END tag1_in[53]
  PIN tag1_in[54]
    DIRECTION INPUT ;
    USE SIGNAL ;
    ANTENNAGATEAREA 1.102000 ;
    PORT
      LAYER Metal2 ;
        RECT 469.280 849.440 469.840 850.000 ;
    END
  END tag1_in[54]
  PIN tag1_in[55]
    DIRECTION INPUT ;
    USE SIGNAL ;
    ANTENNAGATEAREA 1.102000 ;
    PORT
      LAYER Metal2 ;
        RECT 404.320 849.440 404.880 850.000 ;
    END
  END tag1_in[55]
  PIN tag1_in[56]
    DIRECTION INPUT ;
    USE SIGNAL ;
    ANTENNAGATEAREA 1.102000 ;
    PORT
      LAYER Metal2 ;
        RECT 434.560 849.440 435.120 850.000 ;
    END
  END tag1_in[56]
  PIN tag1_in[57]
    DIRECTION INPUT ;
    USE SIGNAL ;
    ANTENNAGATEAREA 1.102000 ;
    PORT
      LAYER Metal2 ;
        RECT 504.000 849.440 504.560 850.000 ;
    END
  END tag1_in[57]
  PIN tag1_in[58]
    DIRECTION INPUT ;
    USE SIGNAL ;
    ANTENNAGATEAREA 1.102000 ;
    PORT
      LAYER Metal2 ;
        RECT 505.120 849.440 505.680 850.000 ;
    END
  END tag1_in[58]
  PIN tag1_in[59]
    DIRECTION INPUT ;
    USE SIGNAL ;
    ANTENNAGATEAREA 1.102000 ;
    PORT
      LAYER Metal2 ;
        RECT 426.720 849.440 427.280 850.000 ;
    END
  END tag1_in[59]
  PIN tag1_in[5]
    DIRECTION INPUT ;
    USE SIGNAL ;
    ANTENNAGATEAREA 1.102000 ;
    PORT
      LAYER Metal2 ;
        RECT 444.640 0.000 445.200 0.560 ;
    END
  END tag1_in[5]
  PIN tag1_in[60]
    DIRECTION INPUT ;
    USE SIGNAL ;
    ANTENNAGATEAREA 1.102000 ;
    PORT
      LAYER Metal2 ;
        RECT 496.160 849.440 496.720 850.000 ;
    END
  END tag1_in[60]
  PIN tag1_in[61]
    DIRECTION INPUT ;
    USE SIGNAL ;
    ANTENNAGATEAREA 1.102000 ;
    PORT
      LAYER Metal3 ;
        RECT 849.440 533.120 850.000 533.680 ;
    END
  END tag1_in[61]
  PIN tag1_in[62]
    DIRECTION INPUT ;
    USE SIGNAL ;
    ANTENNAGATEAREA 1.102000 ;
    PORT
      LAYER Metal2 ;
        RECT 313.600 849.440 314.160 850.000 ;
    END
  END tag1_in[62]
  PIN tag1_in[63]
    DIRECTION INPUT ;
    USE SIGNAL ;
    ANTENNAGATEAREA 1.102000 ;
    PORT
      LAYER Metal3 ;
        RECT 849.440 517.440 850.000 518.000 ;
    END
  END tag1_in[63]
  PIN tag1_in[6]
    DIRECTION INPUT ;
    USE SIGNAL ;
    ANTENNAGATEAREA 1.102000 ;
    PORT
      LAYER Metal2 ;
        RECT 480.480 0.000 481.040 0.560 ;
    END
  END tag1_in[6]
  PIN tag1_in[7]
    DIRECTION INPUT ;
    USE SIGNAL ;
    ANTENNAGATEAREA 1.102000 ;
    PORT
      LAYER Metal2 ;
        RECT 595.840 0.000 596.400 0.560 ;
    END
  END tag1_in[7]
  PIN tag1_in[8]
    DIRECTION INPUT ;
    USE SIGNAL ;
    ANTENNAGATEAREA 1.102000 ;
    PORT
      LAYER Metal2 ;
        RECT 520.800 0.000 521.360 0.560 ;
    END
  END tag1_in[8]
  PIN tag1_in[9]
    DIRECTION INPUT ;
    USE SIGNAL ;
    ANTENNAGATEAREA 1.102000 ;
    PORT
      LAYER Metal2 ;
        RECT 596.960 0.000 597.520 0.560 ;
    END
  END tag1_in[9]
  OBS
      LAYER Nwell ;
        RECT 0.690 7.410 848.830 839.310 ;
      LAYER Metal1 ;
        RECT 1.120 7.540 848.400 839.180 ;
      LAYER Metal2 ;
        RECT 0.140 849.140 205.780 849.940 ;
        RECT 206.940 849.140 211.380 849.940 ;
        RECT 212.540 849.140 214.740 849.940 ;
        RECT 215.900 849.140 221.460 849.940 ;
        RECT 225.980 849.140 230.420 849.940 ;
        RECT 231.580 849.140 232.660 849.940 ;
        RECT 233.820 849.140 236.020 849.940 ;
        RECT 239.420 849.140 244.980 849.940 ;
        RECT 248.380 849.140 250.580 849.940 ;
        RECT 251.740 849.140 256.180 849.940 ;
        RECT 257.340 849.140 258.420 849.940 ;
        RECT 259.580 849.140 265.140 849.940 ;
        RECT 266.300 849.140 268.500 849.940 ;
        RECT 270.780 849.140 274.100 849.940 ;
        RECT 275.260 849.140 280.820 849.940 ;
        RECT 288.700 849.140 289.780 849.940 ;
        RECT 290.940 849.140 293.140 849.940 ;
        RECT 304.380 849.140 305.460 849.940 ;
        RECT 307.740 849.140 308.820 849.940 ;
        RECT 309.980 849.140 312.180 849.940 ;
        RECT 318.940 849.140 323.380 849.940 ;
        RECT 324.540 849.140 325.620 849.940 ;
        RECT 329.020 849.140 330.100 849.940 ;
        RECT 331.260 849.140 335.700 849.940 ;
        RECT 340.220 849.140 341.300 849.940 ;
        RECT 342.460 849.140 344.660 849.940 ;
        RECT 349.180 849.140 352.500 849.940 ;
        RECT 354.780 849.140 355.860 849.940 ;
        RECT 357.020 849.140 358.100 849.940 ;
        RECT 361.500 849.140 362.580 849.940 ;
        RECT 368.220 849.140 370.420 849.940 ;
        RECT 383.900 849.140 386.100 849.940 ;
        RECT 387.260 849.140 388.340 849.940 ;
        RECT 389.500 849.140 391.700 849.940 ;
        RECT 396.220 849.140 398.420 849.940 ;
        RECT 490.300 849.140 491.380 849.940 ;
        RECT 507.100 849.140 509.300 849.940 ;
        RECT 531.740 849.140 535.060 849.940 ;
        RECT 536.220 849.140 537.300 849.940 ;
        RECT 539.580 849.140 540.660 849.940 ;
        RECT 542.940 849.140 547.380 849.940 ;
        RECT 549.660 849.140 550.740 849.940 ;
        RECT 553.020 849.140 556.340 849.940 ;
        RECT 560.860 849.140 564.180 849.940 ;
        RECT 565.340 849.140 568.660 849.940 ;
        RECT 569.820 849.140 572.020 849.940 ;
        RECT 573.180 849.140 574.260 849.940 ;
        RECT 575.420 849.140 578.740 849.940 ;
        RECT 579.900 849.140 585.460 849.940 ;
        RECT 586.620 849.140 596.660 849.940 ;
        RECT 597.820 849.140 600.020 849.940 ;
        RECT 602.300 849.140 606.740 849.940 ;
        RECT 607.900 849.140 612.340 849.940 ;
        RECT 614.620 849.140 619.060 849.940 ;
        RECT 620.220 849.140 622.420 849.940 ;
        RECT 624.700 849.140 629.140 849.940 ;
        RECT 630.300 849.140 634.740 849.940 ;
        RECT 635.900 849.140 650.420 849.940 ;
        RECT 651.580 849.140 849.940 849.940 ;
        RECT 0.140 0.860 849.940 849.140 ;
        RECT 0.140 0.140 206.900 0.860 ;
        RECT 210.300 0.140 229.300 0.860 ;
        RECT 230.460 0.140 232.660 0.860 ;
        RECT 233.820 0.140 234.900 0.860 ;
        RECT 236.060 0.140 247.220 0.860 ;
        RECT 257.340 0.140 261.780 0.860 ;
        RECT 262.940 0.140 266.260 0.860 ;
        RECT 267.420 0.140 277.460 0.860 ;
        RECT 283.100 0.140 284.180 0.860 ;
        RECT 286.460 0.140 289.780 0.860 ;
        RECT 290.940 0.140 292.020 0.860 ;
        RECT 293.180 0.140 295.380 0.860 ;
        RECT 296.540 0.140 304.340 0.860 ;
        RECT 305.500 0.140 307.700 0.860 ;
        RECT 316.700 0.140 318.900 0.860 ;
        RECT 320.060 0.140 321.140 0.860 ;
        RECT 330.140 0.140 331.220 0.860 ;
        RECT 340.220 0.140 342.420 0.860 ;
        RECT 361.500 0.140 363.700 0.860 ;
        RECT 365.980 0.140 367.060 0.860 ;
        RECT 368.220 0.140 369.300 0.860 ;
        RECT 370.460 0.140 371.540 0.860 ;
        RECT 373.820 0.140 374.900 0.860 ;
        RECT 377.180 0.140 378.260 0.860 ;
        RECT 396.220 0.140 399.540 0.860 ;
        RECT 400.700 0.140 402.900 0.860 ;
        RECT 405.180 0.140 407.380 0.860 ;
        RECT 408.540 0.140 416.340 0.860 ;
        RECT 446.620 0.140 448.820 0.860 ;
        RECT 457.820 0.140 458.900 0.860 ;
        RECT 464.540 0.140 468.980 0.860 ;
        RECT 471.260 0.140 473.460 0.860 ;
        RECT 481.340 0.140 483.540 0.860 ;
        RECT 488.060 0.140 492.500 0.860 ;
        RECT 495.900 0.140 496.980 0.860 ;
        RECT 499.260 0.140 500.340 0.860 ;
        RECT 501.500 0.140 502.580 0.860 ;
        RECT 504.860 0.140 507.060 0.860 ;
        RECT 512.700 0.140 514.900 0.860 ;
        RECT 522.780 0.140 523.860 0.860 ;
        RECT 531.740 0.140 537.300 0.860 ;
        RECT 538.460 0.140 542.900 0.860 ;
        RECT 565.340 0.140 568.660 0.860 ;
        RECT 569.820 0.140 570.900 0.860 ;
        RECT 574.300 0.140 576.500 0.860 ;
        RECT 583.260 0.140 584.340 0.860 ;
        RECT 585.500 0.140 589.940 0.860 ;
        RECT 593.340 0.140 595.540 0.860 ;
        RECT 598.940 0.140 604.500 0.860 ;
        RECT 605.660 0.140 607.860 0.860 ;
        RECT 609.020 0.140 610.100 0.860 ;
        RECT 613.500 0.140 616.820 0.860 ;
        RECT 619.100 0.140 622.420 0.860 ;
        RECT 623.580 0.140 628.020 0.860 ;
        RECT 629.180 0.140 635.860 0.860 ;
        RECT 639.260 0.140 640.340 0.860 ;
        RECT 642.620 0.140 647.060 0.860 ;
        RECT 648.220 0.140 849.940 0.860 ;
      LAYER Metal3 ;
        RECT 0.090 666.140 849.440 849.380 ;
        RECT 0.860 664.980 849.440 666.140 ;
        RECT 0.090 661.660 849.440 664.980 ;
        RECT 0.860 659.380 849.440 661.660 ;
        RECT 0.090 650.460 849.440 659.380 ;
        RECT 0.860 649.300 849.440 650.460 ;
        RECT 0.090 648.220 849.440 649.300 ;
        RECT 0.860 647.060 849.440 648.220 ;
        RECT 0.090 632.540 849.440 647.060 ;
        RECT 0.090 631.420 849.140 632.540 ;
        RECT 0.860 631.380 849.140 631.420 ;
        RECT 0.860 630.260 849.440 631.380 ;
        RECT 0.090 629.180 849.440 630.260 ;
        RECT 0.090 628.020 849.140 629.180 ;
        RECT 0.090 626.940 849.440 628.020 ;
        RECT 0.860 625.780 849.440 626.940 ;
        RECT 0.090 624.700 849.440 625.780 ;
        RECT 0.860 623.540 849.440 624.700 ;
        RECT 0.090 622.460 849.440 623.540 ;
        RECT 0.860 621.300 849.140 622.460 ;
        RECT 0.090 620.220 849.440 621.300 ;
        RECT 0.860 619.100 849.440 620.220 ;
        RECT 0.860 619.060 849.140 619.100 ;
        RECT 0.090 616.820 849.140 619.060 ;
        RECT 0.090 615.740 849.440 616.820 ;
        RECT 0.860 613.500 849.440 615.740 ;
        RECT 0.860 612.340 849.140 613.500 ;
        RECT 0.860 611.260 849.440 612.340 ;
        RECT 0.860 610.100 849.140 611.260 ;
        RECT 0.090 609.020 849.440 610.100 ;
        RECT 0.860 607.860 849.140 609.020 ;
        RECT 0.860 606.740 849.440 607.860 ;
        RECT 0.090 605.660 849.440 606.740 ;
        RECT 0.860 604.500 849.440 605.660 ;
        RECT 0.090 603.420 849.440 604.500 ;
        RECT 0.860 602.260 849.140 603.420 ;
        RECT 0.090 601.180 849.440 602.260 ;
        RECT 0.860 598.900 849.440 601.180 ;
        RECT 0.090 597.820 849.440 598.900 ;
        RECT 0.090 596.660 849.140 597.820 ;
        RECT 0.090 591.100 849.440 596.660 ;
        RECT 0.090 589.940 849.140 591.100 ;
        RECT 0.090 587.740 849.440 589.940 ;
        RECT 0.090 586.620 849.140 587.740 ;
        RECT 0.860 585.460 849.140 586.620 ;
        RECT 0.860 584.380 849.440 585.460 ;
        RECT 0.860 584.340 849.140 584.380 ;
        RECT 0.090 583.260 849.140 584.340 ;
        RECT 0.860 582.100 849.140 583.260 ;
        RECT 0.090 581.020 849.140 582.100 ;
        RECT 0.860 580.980 849.140 581.020 ;
        RECT 0.860 578.780 849.440 580.980 ;
        RECT 0.860 578.740 849.140 578.780 ;
        RECT 0.090 577.660 849.140 578.740 ;
        RECT 0.860 577.620 849.140 577.660 ;
        RECT 0.860 576.540 849.440 577.620 ;
        RECT 0.860 575.380 849.140 576.540 ;
        RECT 0.860 569.820 849.440 575.380 ;
        RECT 0.860 568.660 849.140 569.820 ;
        RECT 0.860 567.580 849.440 568.660 ;
        RECT 0.860 567.540 849.140 567.580 ;
        RECT 0.090 566.420 849.140 567.540 ;
        RECT 0.090 565.340 849.440 566.420 ;
        RECT 0.860 563.100 849.440 565.340 ;
        RECT 0.860 556.340 849.140 563.100 ;
        RECT 0.860 555.260 849.440 556.340 ;
        RECT 0.860 555.220 849.140 555.260 ;
        RECT 0.090 554.100 849.140 555.220 ;
        RECT 0.090 550.780 849.440 554.100 ;
        RECT 0.860 547.380 849.140 550.780 ;
        RECT 0.090 546.300 849.140 547.380 ;
        RECT 0.860 546.260 849.140 546.300 ;
        RECT 0.860 545.180 849.440 546.260 ;
        RECT 0.860 544.020 849.140 545.180 ;
        RECT 0.860 542.940 849.440 544.020 ;
        RECT 0.860 541.780 849.140 542.940 ;
        RECT 0.860 540.700 849.440 541.780 ;
        RECT 0.860 539.540 849.140 540.700 ;
        RECT 0.090 538.460 849.140 539.540 ;
        RECT 0.860 538.420 849.140 538.460 ;
        RECT 0.860 537.340 849.440 538.420 ;
        RECT 0.860 537.300 849.140 537.340 ;
        RECT 0.090 536.220 849.140 537.300 ;
        RECT 0.860 535.060 849.140 536.220 ;
        RECT 0.860 533.980 849.440 535.060 ;
        RECT 0.860 532.820 849.140 533.980 ;
        RECT 0.860 529.500 849.440 532.820 ;
        RECT 0.860 528.340 849.140 529.500 ;
        RECT 0.860 527.260 849.440 528.340 ;
        RECT 0.860 526.100 849.140 527.260 ;
        RECT 0.090 525.020 849.440 526.100 ;
        RECT 0.090 523.900 849.140 525.020 ;
        RECT 0.860 521.620 849.140 523.900 ;
        RECT 0.090 520.540 849.440 521.620 ;
        RECT 0.860 518.300 849.440 520.540 ;
        RECT 0.860 517.140 849.140 518.300 ;
        RECT 0.090 516.060 849.140 517.140 ;
        RECT 0.860 514.900 849.140 516.060 ;
        RECT 0.090 513.820 849.440 514.900 ;
        RECT 0.090 512.700 849.140 513.820 ;
        RECT 0.860 511.540 849.140 512.700 ;
        RECT 0.860 510.420 849.440 511.540 ;
        RECT 0.090 507.100 849.440 510.420 ;
        RECT 0.860 502.580 849.140 507.100 ;
        RECT 0.090 500.380 849.140 502.580 ;
        RECT 0.860 493.620 849.140 500.380 ;
        RECT 0.860 491.420 849.440 493.620 ;
        RECT 0.860 481.300 849.140 491.420 ;
        RECT 0.860 479.100 849.440 481.300 ;
        RECT 0.860 473.460 849.140 479.100 ;
        RECT 0.860 470.140 849.440 473.460 ;
        RECT 0.860 468.980 849.140 470.140 ;
        RECT 0.090 467.860 849.140 468.980 ;
        RECT 0.090 466.780 849.440 467.860 ;
        RECT 0.090 465.660 849.140 466.780 ;
        RECT 0.860 461.140 849.140 465.660 ;
        RECT 0.090 460.020 849.140 461.140 ;
        RECT 0.090 458.940 849.440 460.020 ;
        RECT 0.860 452.180 849.440 458.940 ;
        RECT 0.090 451.100 849.440 452.180 ;
        RECT 0.860 448.820 849.140 451.100 ;
        RECT 0.090 447.740 849.440 448.820 ;
        RECT 0.860 446.620 849.440 447.740 ;
        RECT 0.860 443.220 849.140 446.620 ;
        RECT 0.860 440.980 849.440 443.220 ;
        RECT 0.090 439.900 849.440 440.980 ;
        RECT 0.860 438.740 849.440 439.900 ;
        RECT 0.090 437.660 849.440 438.740 ;
        RECT 0.090 435.380 849.140 437.660 ;
        RECT 0.090 433.180 849.440 435.380 ;
        RECT 0.860 432.060 849.440 433.180 ;
        RECT 0.860 411.860 849.140 432.060 ;
        RECT 0.090 410.780 849.140 411.860 ;
        RECT 0.860 409.620 849.140 410.780 ;
        RECT 0.090 408.540 849.140 409.620 ;
        RECT 0.860 407.380 849.140 408.540 ;
        RECT 0.090 404.060 849.140 407.380 ;
        RECT 0.860 404.020 849.140 404.060 ;
        RECT 0.860 402.940 849.440 404.020 ;
        RECT 0.860 401.780 849.140 402.940 ;
        RECT 0.090 400.700 849.140 401.780 ;
        RECT 0.860 397.300 849.140 400.700 ;
        RECT 0.860 395.100 849.440 397.300 ;
        RECT 0.860 391.700 849.140 395.100 ;
        RECT 0.860 389.500 849.440 391.700 ;
        RECT 0.860 387.220 849.140 389.500 ;
        RECT 0.860 382.740 849.440 387.220 ;
        RECT 0.090 381.660 849.440 382.740 ;
        RECT 0.090 380.540 849.140 381.660 ;
        RECT 0.860 379.380 849.140 380.540 ;
        RECT 0.090 376.060 849.140 379.380 ;
        RECT 0.860 369.300 849.140 376.060 ;
        RECT 0.090 368.220 849.140 369.300 ;
        RECT 0.860 367.060 849.140 368.220 ;
        RECT 0.090 363.740 849.140 367.060 ;
        RECT 0.860 355.860 849.140 363.740 ;
        RECT 0.090 354.780 849.140 355.860 ;
        RECT 0.860 353.620 849.140 354.780 ;
        RECT 0.090 348.060 849.140 353.620 ;
        RECT 0.860 343.540 849.140 348.060 ;
        RECT 0.090 341.340 849.140 343.540 ;
        RECT 0.860 339.060 849.140 341.340 ;
        RECT 0.090 337.980 849.140 339.060 ;
        RECT 0.860 333.460 849.140 337.980 ;
        RECT 0.090 330.140 849.140 333.460 ;
        RECT 0.860 325.620 849.140 330.140 ;
        RECT 0.090 323.420 849.140 325.620 ;
        RECT 0.860 321.140 849.140 323.420 ;
        RECT 0.090 315.580 849.140 321.140 ;
        RECT 0.860 311.060 849.140 315.580 ;
        RECT 0.090 309.940 849.140 311.060 ;
        RECT 0.090 308.860 849.440 309.940 ;
        RECT 0.860 307.700 849.140 308.860 ;
        RECT 0.860 306.580 849.440 307.700 ;
        RECT 0.090 305.500 849.440 306.580 ;
        RECT 0.090 303.220 849.140 305.500 ;
        RECT 0.090 302.140 849.440 303.220 ;
        RECT 0.860 299.860 849.140 302.140 ;
        RECT 0.090 298.780 849.440 299.860 ;
        RECT 0.090 295.420 849.140 298.780 ;
        RECT 0.860 293.140 849.140 295.420 ;
        RECT 0.860 292.020 849.440 293.140 ;
        RECT 0.090 290.940 849.440 292.020 ;
        RECT 0.090 289.780 849.140 290.940 ;
        RECT 0.090 287.580 849.440 289.780 ;
        RECT 0.860 286.420 849.140 287.580 ;
        RECT 0.860 284.220 849.440 286.420 ;
        RECT 0.860 283.060 849.140 284.220 ;
        RECT 0.860 281.940 849.440 283.060 ;
        RECT 0.090 279.740 849.440 281.940 ;
        RECT 0.860 278.580 849.140 279.740 ;
        RECT 0.860 277.500 849.440 278.580 ;
        RECT 0.860 277.460 849.140 277.500 ;
        RECT 0.090 276.340 849.140 277.460 ;
        RECT 0.090 273.020 849.440 276.340 ;
        RECT 0.860 271.860 849.440 273.020 ;
        RECT 0.090 268.540 849.440 271.860 ;
        RECT 0.860 266.260 849.440 268.540 ;
        RECT 0.090 265.180 849.440 266.260 ;
        RECT 0.860 264.020 849.440 265.180 ;
        RECT 0.090 261.820 849.440 264.020 ;
        RECT 0.860 259.540 849.440 261.820 ;
        RECT 0.090 258.460 849.440 259.540 ;
        RECT 0.090 257.300 849.140 258.460 ;
        RECT 0.090 255.100 849.440 257.300 ;
        RECT 0.860 252.820 849.440 255.100 ;
        RECT 0.090 251.740 849.440 252.820 ;
        RECT 0.090 248.380 849.140 251.740 ;
        RECT 0.860 248.340 849.140 248.380 ;
        RECT 0.860 247.220 849.440 248.340 ;
        RECT 0.090 246.140 849.440 247.220 ;
        RECT 0.860 244.980 849.140 246.140 ;
        RECT 0.090 243.900 849.440 244.980 ;
        RECT 0.090 242.740 849.140 243.900 ;
        RECT 0.090 241.660 849.440 242.740 ;
        RECT 0.090 240.500 849.140 241.660 ;
        RECT 0.090 239.420 849.440 240.500 ;
        RECT 0.090 238.260 849.140 239.420 ;
        RECT 0.090 233.820 849.440 238.260 ;
        RECT 0.860 232.660 849.140 233.820 ;
        RECT 0.860 231.580 849.440 232.660 ;
        RECT 0.860 228.180 849.140 231.580 ;
        RECT 0.860 227.100 849.440 228.180 ;
        RECT 0.860 227.060 849.140 227.100 ;
        RECT 0.090 225.980 849.140 227.060 ;
        RECT 0.860 224.820 849.140 225.980 ;
        RECT 0.090 222.620 849.440 224.820 ;
        RECT 0.090 220.380 849.140 222.620 ;
        RECT 0.860 220.340 849.140 220.380 ;
        RECT 0.860 219.220 849.440 220.340 ;
        RECT 0.090 214.780 849.440 219.220 ;
        RECT 0.090 213.620 849.140 214.780 ;
        RECT 0.090 211.420 849.440 213.620 ;
        RECT 0.860 209.180 849.440 211.420 ;
        RECT 0.860 209.140 849.140 209.180 ;
        RECT 0.090 208.020 849.140 209.140 ;
        RECT 0.090 205.820 849.440 208.020 ;
        RECT 0.090 204.660 849.140 205.820 ;
        RECT 0.090 194.620 849.440 204.660 ;
        RECT 0.090 193.460 849.140 194.620 ;
        RECT 0.090 192.380 849.440 193.460 ;
        RECT 0.090 191.220 849.140 192.380 ;
        RECT 0.090 161.020 849.440 191.220 ;
        RECT 0.090 159.860 849.140 161.020 ;
        RECT 0.090 144.220 849.440 159.860 ;
        RECT 0.090 143.060 849.140 144.220 ;
        RECT 0.090 0.700 849.440 143.060 ;
      LAYER Metal4 ;
        RECT 0.700 0.650 14.640 849.430 ;
        RECT 20.240 0.650 20.640 849.430 ;
        RECT 26.240 0.650 64.640 849.430 ;
        RECT 70.240 0.650 70.640 849.430 ;
        RECT 76.240 0.650 114.640 849.430 ;
        RECT 120.240 0.650 120.640 849.430 ;
        RECT 126.240 0.650 164.640 849.430 ;
        RECT 170.240 0.650 170.640 849.430 ;
        RECT 176.240 0.650 214.640 849.430 ;
        RECT 220.240 0.650 220.640 849.430 ;
        RECT 226.240 0.650 264.640 849.430 ;
        RECT 270.240 0.650 270.640 849.430 ;
        RECT 276.240 0.650 314.640 849.430 ;
        RECT 320.240 0.650 320.640 849.430 ;
        RECT 326.240 0.650 364.640 849.430 ;
        RECT 370.240 0.650 370.640 849.430 ;
        RECT 376.240 0.650 414.640 849.430 ;
        RECT 420.240 0.650 420.640 849.430 ;
        RECT 426.240 0.650 464.640 849.430 ;
        RECT 470.240 0.650 470.640 849.430 ;
        RECT 476.240 0.650 514.640 849.430 ;
        RECT 520.240 0.650 520.640 849.430 ;
        RECT 526.240 0.650 564.640 849.430 ;
        RECT 570.240 0.650 570.640 849.430 ;
        RECT 576.240 0.650 614.640 849.430 ;
        RECT 620.240 0.650 620.640 849.430 ;
        RECT 626.240 0.650 664.640 849.430 ;
        RECT 670.240 0.650 670.640 849.430 ;
        RECT 676.240 0.650 714.640 849.430 ;
        RECT 720.240 0.650 720.640 849.430 ;
        RECT 726.240 0.650 764.640 849.430 ;
        RECT 770.240 0.650 770.640 849.430 ;
        RECT 776.240 0.650 814.640 849.430 ;
        RECT 820.240 0.650 820.640 849.430 ;
        RECT 826.240 0.650 849.380 849.430 ;
      LAYER Metal5 ;
        RECT 1.180 20.930 847.780 836.770 ;
  END
END ascon_core_adpt_encdec
END LIBRARY

